VERSION 5.7 ;
  NOWIREEXTENSIONATPIN ON ;
  DIVIDERCHAR "/" ;
  BUSBITCHARS "[]" ;
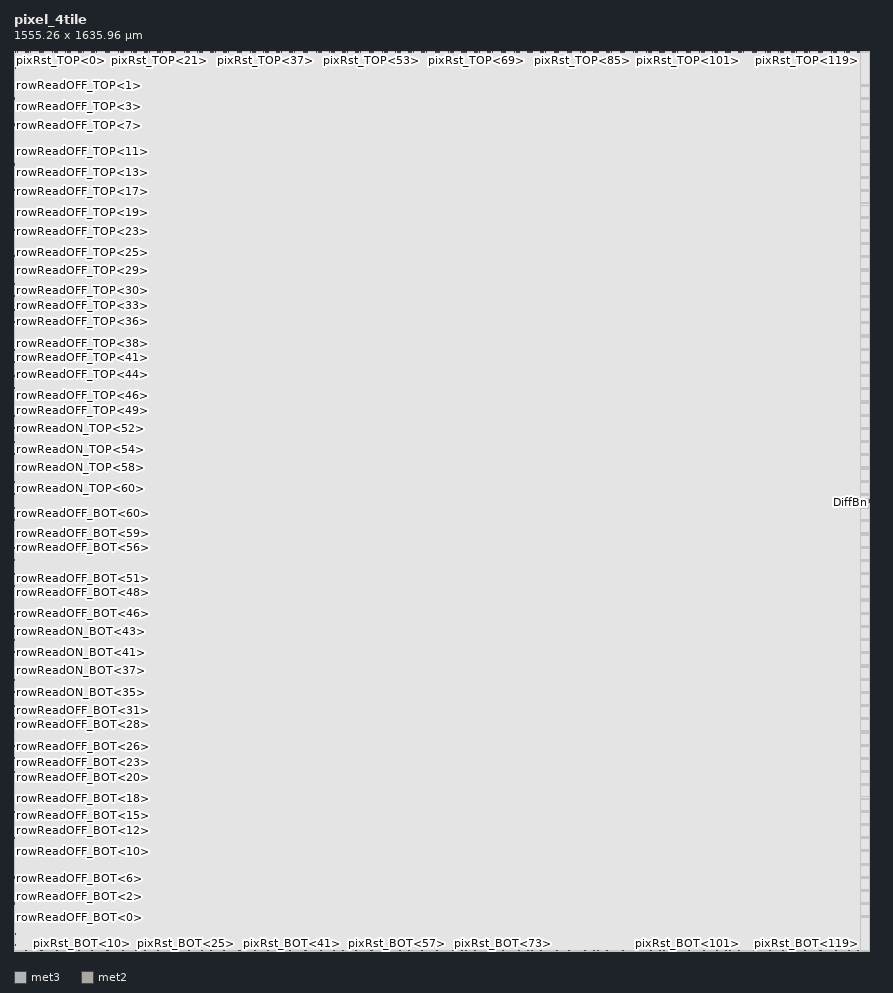
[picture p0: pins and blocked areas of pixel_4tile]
MACRO pixel_4tile
  CLASS BLOCK ;
  FOREIGN pixel_4tile ;
  ORIGIN -278.615 708.105 ;
  SIZE 1555.255 BY 1635.965 ;
  PIN OnBn
    ANTENNAGATEAREA 36864.000000 ;
    PORT
      LAYER met3 ;
        RECT 1832.880 113.885 1833.380 114.885 ;
    END
  END OnBn
  PIN PrBp
    ANTENNAGATEAREA 1228.799927 ;
    PORT
      LAYER met3 ;
        RECT 1832.880 110.885 1833.380 111.885 ;
    END
  END PrBp
  PIN RefrBp
    ANTENNAGATEAREA 10321.919922 ;
    PORT
      LAYER met3 ;
        RECT 1832.880 112.385 1833.380 113.385 ;
    END
  END RefrBp
  PIN OffBn
    ANTENNAGATEAREA 36864.000000 ;
    PORT
      LAYER met3 ;
        RECT 1832.880 107.885 1833.380 108.885 ;
    END
  END OffBn
  PIN PrSFBp
    ANTENNAGATEAREA 10321.919922 ;
    PORT
      LAYER met3 ;
        RECT 1832.880 109.385 1833.380 110.385 ;
    END
  END PrSFBp
  PIN DiffBn
    ANTENNAGATEAREA 36576.000000 ;
    PORT
      LAYER met3 ;
        RECT 1832.880 106.385 1833.380 107.385 ;
    END
  END DiffBn
  PIN VTHRESH
    ANTENNAGATEAREA 38.399998 ;
    PORT
      LAYER met3 ;
        RECT 1832.880 104.885 1833.380 105.885 ;
    END
  END VTHRESH
  PIN voutn_BOT<0>
    ANTENNADIFFAREA 0.870000 ;
    PORT
      LAYER met3 ;
        RECT 284.095 -707.875 284.865 -707.575 ;
    END
  END voutn_BOT<0>
  PIN voutn_BOT<1>
    ANTENNADIFFAREA 0.870000 ;
    PORT
      LAYER met3 ;
        RECT 300.215 -707.875 300.985 -707.575 ;
    END
  END voutn_BOT<1>
  PIN voutn_BOT<2>
    ANTENNADIFFAREA 0.870000 ;
    PORT
      LAYER met3 ;
        RECT 308.095 -707.875 308.865 -707.575 ;
    END
  END voutn_BOT<2>
  PIN voutn_BOT<3>
    ANTENNADIFFAREA 0.870000 ;
    PORT
      LAYER met3 ;
        RECT 324.215 -707.875 324.985 -707.575 ;
    END
  END voutn_BOT<3>
  PIN voutn_BOT<4>
    ANTENNADIFFAREA 0.870000 ;
    PORT
      LAYER met3 ;
        RECT 332.095 -707.875 332.865 -707.575 ;
    END
  END voutn_BOT<4>
  PIN voutn_BOT<5>
    ANTENNADIFFAREA 0.870000 ;
    PORT
      LAYER met3 ;
        RECT 348.215 -707.875 348.985 -707.575 ;
    END
  END voutn_BOT<5>
  PIN voutn_BOT<6>
    ANTENNADIFFAREA 0.870000 ;
    PORT
      LAYER met3 ;
        RECT 356.095 -707.875 356.865 -707.575 ;
    END
  END voutn_BOT<6>
  PIN voutn_BOT<7>
    ANTENNADIFFAREA 0.870000 ;
    PORT
      LAYER met3 ;
        RECT 372.215 -707.875 372.985 -707.575 ;
    END
  END voutn_BOT<7>
  PIN voutn_BOT<8>
    ANTENNADIFFAREA 0.870000 ;
    PORT
      LAYER met3 ;
        RECT 380.095 -707.875 380.865 -707.575 ;
    END
  END voutn_BOT<8>
  PIN voutn_BOT<9>
    ANTENNADIFFAREA 0.870000 ;
    PORT
      LAYER met3 ;
        RECT 396.215 -707.875 396.985 -707.575 ;
    END
  END voutn_BOT<9>
  PIN voutn_BOT<10>
    ANTENNADIFFAREA 0.870000 ;
    PORT
      LAYER met3 ;
        RECT 404.095 -707.875 404.865 -707.575 ;
    END
  END voutn_BOT<10>
  PIN voutn_BOT<11>
    ANTENNADIFFAREA 0.870000 ;
    PORT
      LAYER met3 ;
        RECT 420.215 -707.875 420.985 -707.575 ;
    END
  END voutn_BOT<11>
  PIN voutn_BOT<12>
    ANTENNADIFFAREA 0.870000 ;
    PORT
      LAYER met3 ;
        RECT 428.095 -707.875 428.865 -707.575 ;
    END
  END voutn_BOT<12>
  PIN voutn_BOT<13>
    ANTENNADIFFAREA 0.870000 ;
    PORT
      LAYER met3 ;
        RECT 444.215 -707.875 444.985 -707.575 ;
    END
  END voutn_BOT<13>
  PIN voutn_BOT<14>
    ANTENNADIFFAREA 0.870000 ;
    PORT
      LAYER met3 ;
        RECT 452.095 -707.875 452.865 -707.575 ;
    END
  END voutn_BOT<14>
  PIN voutn_BOT<15>
    ANTENNADIFFAREA 0.870000 ;
    PORT
      LAYER met3 ;
        RECT 468.215 -707.875 468.985 -707.575 ;
    END
  END voutn_BOT<15>
  PIN voutn_BOT<16>
    ANTENNADIFFAREA 0.870000 ;
    PORT
      LAYER met3 ;
        RECT 476.095 -707.875 476.865 -707.575 ;
    END
  END voutn_BOT<16>
  PIN voutn_BOT<17>
    ANTENNADIFFAREA 0.870000 ;
    PORT
      LAYER met3 ;
        RECT 492.215 -707.875 492.985 -707.575 ;
    END
  END voutn_BOT<17>
  PIN voutn_BOT<18>
    ANTENNADIFFAREA 0.870000 ;
    PORT
      LAYER met3 ;
        RECT 500.095 -707.875 500.865 -707.575 ;
    END
  END voutn_BOT<18>
  PIN voutn_BOT<19>
    ANTENNADIFFAREA 0.870000 ;
    PORT
      LAYER met3 ;
        RECT 516.215 -707.875 516.985 -707.575 ;
    END
  END voutn_BOT<19>
  PIN voutn_BOT<20>
    ANTENNADIFFAREA 0.870000 ;
    PORT
      LAYER met3 ;
        RECT 524.095 -707.875 524.865 -707.575 ;
    END
  END voutn_BOT<20>
  PIN voutn_BOT<21>
    ANTENNADIFFAREA 0.870000 ;
    PORT
      LAYER met3 ;
        RECT 540.215 -707.875 540.985 -707.575 ;
    END
  END voutn_BOT<21>
  PIN voutn_BOT<22>
    ANTENNADIFFAREA 0.870000 ;
    PORT
      LAYER met3 ;
        RECT 548.095 -707.875 548.865 -707.575 ;
    END
  END voutn_BOT<22>
  PIN voutn_BOT<23>
    ANTENNADIFFAREA 0.870000 ;
    PORT
      LAYER met3 ;
        RECT 564.215 -707.875 564.985 -707.575 ;
    END
  END voutn_BOT<23>
  PIN voutn_BOT<24>
    ANTENNADIFFAREA 0.870000 ;
    PORT
      LAYER met3 ;
        RECT 572.095 -707.875 572.865 -707.575 ;
    END
  END voutn_BOT<24>
  PIN voutn_BOT<25>
    ANTENNADIFFAREA 0.870000 ;
    PORT
      LAYER met3 ;
        RECT 588.215 -707.875 588.985 -707.575 ;
    END
  END voutn_BOT<25>
  PIN voutn_BOT<26>
    ANTENNADIFFAREA 0.870000 ;
    PORT
      LAYER met3 ;
        RECT 596.095 -707.875 596.865 -707.575 ;
    END
  END voutn_BOT<26>
  PIN voutn_BOT<27>
    ANTENNADIFFAREA 0.870000 ;
    PORT
      LAYER met3 ;
        RECT 612.215 -707.875 612.985 -707.575 ;
    END
  END voutn_BOT<27>
  PIN voutn_BOT<28>
    ANTENNADIFFAREA 0.870000 ;
    PORT
      LAYER met3 ;
        RECT 620.095 -707.875 620.865 -707.575 ;
    END
  END voutn_BOT<28>
  PIN voutn_BOT<29>
    ANTENNADIFFAREA 0.870000 ;
    PORT
      LAYER met3 ;
        RECT 636.215 -707.875 636.985 -707.575 ;
    END
  END voutn_BOT<29>
  PIN voutn_BOT<30>
    ANTENNADIFFAREA 0.870000 ;
    PORT
      LAYER met3 ;
        RECT 644.095 -707.875 644.865 -707.575 ;
    END
  END voutn_BOT<30>
  PIN voutn_BOT<31>
    ANTENNADIFFAREA 0.870000 ;
    PORT
      LAYER met3 ;
        RECT 660.215 -707.875 660.985 -707.575 ;
    END
  END voutn_BOT<31>
  PIN voutn_BOT<32>
    ANTENNADIFFAREA 0.870000 ;
    PORT
      LAYER met3 ;
        RECT 668.095 -707.875 668.865 -707.575 ;
    END
  END voutn_BOT<32>
  PIN voutn_BOT<33>
    ANTENNADIFFAREA 0.870000 ;
    PORT
      LAYER met3 ;
        RECT 684.215 -707.875 684.985 -707.575 ;
    END
  END voutn_BOT<33>
  PIN voutn_BOT<34>
    ANTENNADIFFAREA 0.870000 ;
    PORT
      LAYER met3 ;
        RECT 692.095 -707.875 692.865 -707.575 ;
    END
  END voutn_BOT<34>
  PIN voutn_BOT<35>
    ANTENNADIFFAREA 0.870000 ;
    PORT
      LAYER met3 ;
        RECT 708.215 -707.875 708.985 -707.575 ;
    END
  END voutn_BOT<35>
  PIN voutn_BOT<36>
    ANTENNADIFFAREA 0.870000 ;
    PORT
      LAYER met3 ;
        RECT 716.095 -707.875 716.865 -707.575 ;
    END
  END voutn_BOT<36>
  PIN voutn_BOT<37>
    ANTENNADIFFAREA 0.870000 ;
    PORT
      LAYER met3 ;
        RECT 732.215 -707.875 732.985 -707.575 ;
    END
  END voutn_BOT<37>
  PIN voutn_BOT<38>
    ANTENNADIFFAREA 0.870000 ;
    PORT
      LAYER met3 ;
        RECT 740.095 -707.875 740.865 -707.575 ;
    END
  END voutn_BOT<38>
  PIN voutn_BOT<39>
    ANTENNADIFFAREA 0.870000 ;
    PORT
      LAYER met3 ;
        RECT 756.215 -707.875 756.985 -707.575 ;
    END
  END voutn_BOT<39>
  PIN voutn_BOT<40>
    ANTENNADIFFAREA 0.870000 ;
    PORT
      LAYER met3 ;
        RECT 764.095 -707.875 764.865 -707.575 ;
    END
  END voutn_BOT<40>
  PIN voutn_BOT<41>
    ANTENNADIFFAREA 0.870000 ;
    PORT
      LAYER met3 ;
        RECT 780.215 -707.875 780.985 -707.575 ;
    END
  END voutn_BOT<41>
  PIN voutn_BOT<42>
    ANTENNADIFFAREA 0.870000 ;
    PORT
      LAYER met3 ;
        RECT 788.095 -707.875 788.865 -707.575 ;
    END
  END voutn_BOT<42>
  PIN voutn_BOT<43>
    ANTENNADIFFAREA 0.870000 ;
    PORT
      LAYER met3 ;
        RECT 804.215 -707.875 804.985 -707.575 ;
    END
  END voutn_BOT<43>
  PIN voutn_BOT<44>
    ANTENNADIFFAREA 0.870000 ;
    PORT
      LAYER met3 ;
        RECT 812.095 -707.875 812.865 -707.575 ;
    END
  END voutn_BOT<44>
  PIN voutn_BOT<45>
    ANTENNADIFFAREA 0.870000 ;
    PORT
      LAYER met3 ;
        RECT 828.215 -707.875 828.985 -707.575 ;
    END
  END voutn_BOT<45>
  PIN voutn_BOT<46>
    ANTENNADIFFAREA 0.870000 ;
    PORT
      LAYER met3 ;
        RECT 836.095 -707.875 836.865 -707.575 ;
    END
  END voutn_BOT<46>
  PIN voutn_BOT<47>
    ANTENNADIFFAREA 0.870000 ;
    PORT
      LAYER met3 ;
        RECT 852.215 -707.875 852.985 -707.575 ;
    END
  END voutn_BOT<47>
  PIN voutn_BOT<48>
    ANTENNADIFFAREA 0.870000 ;
    PORT
      LAYER met3 ;
        RECT 860.095 -707.875 860.865 -707.575 ;
    END
  END voutn_BOT<48>
  PIN voutn_BOT<49>
    ANTENNADIFFAREA 0.870000 ;
    PORT
      LAYER met3 ;
        RECT 876.215 -707.875 876.985 -707.575 ;
    END
  END voutn_BOT<49>
  PIN voutn_BOT<50>
    ANTENNADIFFAREA 0.870000 ;
    PORT
      LAYER met3 ;
        RECT 884.095 -707.875 884.865 -707.575 ;
    END
  END voutn_BOT<50>
  PIN voutn_BOT<51>
    ANTENNADIFFAREA 0.870000 ;
    PORT
      LAYER met3 ;
        RECT 900.215 -707.875 900.985 -707.575 ;
    END
  END voutn_BOT<51>
  PIN voutn_BOT<52>
    ANTENNADIFFAREA 0.870000 ;
    PORT
      LAYER met3 ;
        RECT 908.095 -707.875 908.865 -707.575 ;
    END
  END voutn_BOT<52>
  PIN voutn_BOT<53>
    ANTENNADIFFAREA 0.870000 ;
    PORT
      LAYER met3 ;
        RECT 924.215 -707.875 924.985 -707.575 ;
    END
  END voutn_BOT<53>
  PIN voutn_BOT<54>
    ANTENNADIFFAREA 0.870000 ;
    PORT
      LAYER met3 ;
        RECT 932.095 -707.875 932.865 -707.575 ;
    END
  END voutn_BOT<54>
  PIN voutn_BOT<55>
    ANTENNADIFFAREA 0.870000 ;
    PORT
      LAYER met3 ;
        RECT 948.215 -707.875 948.985 -707.575 ;
    END
  END voutn_BOT<55>
  PIN voutn_BOT<56>
    ANTENNADIFFAREA 0.870000 ;
    PORT
      LAYER met3 ;
        RECT 956.095 -707.875 956.865 -707.575 ;
    END
  END voutn_BOT<56>
  PIN voutn_BOT<57>
    ANTENNADIFFAREA 0.870000 ;
    PORT
      LAYER met3 ;
        RECT 972.215 -707.875 972.985 -707.575 ;
    END
  END voutn_BOT<57>
  PIN voutn_BOT<58>
    ANTENNADIFFAREA 0.870000 ;
    PORT
      LAYER met3 ;
        RECT 980.095 -707.875 980.865 -707.575 ;
    END
  END voutn_BOT<58>
  PIN voutn_BOT<59>
    ANTENNADIFFAREA 0.870000 ;
    PORT
      LAYER met3 ;
        RECT 996.215 -707.875 996.985 -707.575 ;
    END
  END voutn_BOT<59>
  PIN voutn_BOT<60>
    ANTENNADIFFAREA 0.870000 ;
    PORT
      LAYER met3 ;
        RECT 1004.095 -707.875 1004.865 -707.575 ;
    END
  END voutn_BOT<60>
  PIN voutn_BOT<61>
    ANTENNADIFFAREA 0.870000 ;
    PORT
      LAYER met3 ;
        RECT 1020.215 -707.875 1020.985 -707.575 ;
    END
  END voutn_BOT<61>
  PIN voutn_BOT<62>
    ANTENNADIFFAREA 0.870000 ;
    PORT
      LAYER met3 ;
        RECT 1028.095 -707.875 1028.865 -707.575 ;
    END
  END voutn_BOT<62>
  PIN voutn_BOT<63>
    ANTENNADIFFAREA 0.870000 ;
    PORT
      LAYER met3 ;
        RECT 1044.215 -707.875 1044.985 -707.575 ;
    END
  END voutn_BOT<63>
  PIN voutn_BOT<64>
    ANTENNADIFFAREA 0.870000 ;
    PORT
      LAYER met3 ;
        RECT 1052.095 -707.875 1052.865 -707.575 ;
    END
  END voutn_BOT<64>
  PIN voutn_BOT<65>
    ANTENNADIFFAREA 0.870000 ;
    PORT
      LAYER met3 ;
        RECT 1068.215 -707.875 1068.985 -707.575 ;
    END
  END voutn_BOT<65>
  PIN voutn_BOT<66>
    ANTENNADIFFAREA 0.870000 ;
    PORT
      LAYER met3 ;
        RECT 1076.095 -707.875 1076.865 -707.575 ;
    END
  END voutn_BOT<66>
  PIN voutn_BOT<67>
    ANTENNADIFFAREA 0.870000 ;
    PORT
      LAYER met3 ;
        RECT 1092.215 -707.875 1092.985 -707.575 ;
    END
  END voutn_BOT<67>
  PIN voutn_BOT<68>
    ANTENNADIFFAREA 0.870000 ;
    PORT
      LAYER met3 ;
        RECT 1100.095 -707.875 1100.865 -707.575 ;
    END
  END voutn_BOT<68>
  PIN voutn_BOT<69>
    ANTENNADIFFAREA 0.870000 ;
    PORT
      LAYER met3 ;
        RECT 1116.215 -707.875 1116.985 -707.575 ;
    END
  END voutn_BOT<69>
  PIN voutn_BOT<70>
    ANTENNADIFFAREA 0.870000 ;
    PORT
      LAYER met3 ;
        RECT 1124.095 -707.875 1124.865 -707.575 ;
    END
  END voutn_BOT<70>
  PIN voutn_BOT<71>
    ANTENNADIFFAREA 0.870000 ;
    PORT
      LAYER met3 ;
        RECT 1140.215 -707.875 1140.985 -707.575 ;
    END
  END voutn_BOT<71>
  PIN voutn_BOT<72>
    ANTENNADIFFAREA 0.870000 ;
    PORT
      LAYER met3 ;
        RECT 1148.095 -707.875 1148.865 -707.575 ;
    END
  END voutn_BOT<72>
  PIN voutn_BOT<73>
    ANTENNADIFFAREA 0.870000 ;
    PORT
      LAYER met3 ;
        RECT 1164.215 -707.875 1164.985 -707.575 ;
    END
  END voutn_BOT<73>
  PIN voutn_BOT<74>
    ANTENNADIFFAREA 0.870000 ;
    PORT
      LAYER met3 ;
        RECT 1172.095 -707.875 1172.865 -707.575 ;
    END
  END voutn_BOT<74>
  PIN voutn_BOT<75>
    ANTENNADIFFAREA 0.870000 ;
    PORT
      LAYER met3 ;
        RECT 1188.215 -707.875 1188.985 -707.575 ;
    END
  END voutn_BOT<75>
  PIN voutn_BOT<76>
    ANTENNADIFFAREA 0.870000 ;
    PORT
      LAYER met3 ;
        RECT 1196.095 -707.875 1196.865 -707.575 ;
    END
  END voutn_BOT<76>
  PIN voutn_BOT<77>
    ANTENNADIFFAREA 0.870000 ;
    PORT
      LAYER met3 ;
        RECT 1212.215 -707.875 1212.985 -707.575 ;
    END
  END voutn_BOT<77>
  PIN voutn_BOT<78>
    ANTENNADIFFAREA 0.870000 ;
    PORT
      LAYER met3 ;
        RECT 1220.095 -707.875 1220.865 -707.575 ;
    END
  END voutn_BOT<78>
  PIN voutn_BOT<79>
    ANTENNADIFFAREA 0.870000 ;
    PORT
      LAYER met3 ;
        RECT 1236.215 -707.875 1236.985 -707.575 ;
    END
  END voutn_BOT<79>
  PIN voutn_BOT<80>
    ANTENNADIFFAREA 0.870000 ;
    PORT
      LAYER met3 ;
        RECT 1244.095 -707.875 1244.865 -707.575 ;
    END
  END voutn_BOT<80>
  PIN voutn_BOT<81>
    ANTENNADIFFAREA 0.870000 ;
    PORT
      LAYER met3 ;
        RECT 1260.215 -707.875 1260.985 -707.575 ;
    END
  END voutn_BOT<81>
  PIN voutn_BOT<82>
    ANTENNADIFFAREA 0.870000 ;
    PORT
      LAYER met3 ;
        RECT 1268.095 -707.875 1268.865 -707.575 ;
    END
  END voutn_BOT<82>
  PIN voutn_BOT<83>
    ANTENNADIFFAREA 0.870000 ;
    PORT
      LAYER met3 ;
        RECT 1284.215 -707.875 1284.985 -707.575 ;
    END
  END voutn_BOT<83>
  PIN voutn_BOT<84>
    ANTENNADIFFAREA 0.870000 ;
    PORT
      LAYER met3 ;
        RECT 1292.095 -707.875 1292.865 -707.575 ;
    END
  END voutn_BOT<84>
  PIN voutn_BOT<85>
    ANTENNADIFFAREA 0.870000 ;
    PORT
      LAYER met3 ;
        RECT 1308.215 -707.875 1308.985 -707.575 ;
    END
  END voutn_BOT<85>
  PIN voutn_BOT<86>
    ANTENNADIFFAREA 0.870000 ;
    PORT
      LAYER met3 ;
        RECT 1316.095 -707.875 1316.865 -707.575 ;
    END
  END voutn_BOT<86>
  PIN voutn_BOT<87>
    ANTENNADIFFAREA 0.870000 ;
    PORT
      LAYER met3 ;
        RECT 1332.215 -707.875 1332.985 -707.575 ;
    END
  END voutn_BOT<87>
  PIN voutn_BOT<88>
    ANTENNADIFFAREA 0.870000 ;
    PORT
      LAYER met3 ;
        RECT 1340.095 -707.875 1340.865 -707.575 ;
    END
  END voutn_BOT<88>
  PIN voutn_BOT<89>
    ANTENNADIFFAREA 0.870000 ;
    PORT
      LAYER met3 ;
        RECT 1356.215 -707.875 1356.985 -707.575 ;
    END
  END voutn_BOT<89>
  PIN voutn_BOT<90>
    ANTENNADIFFAREA 0.870000 ;
    PORT
      LAYER met3 ;
        RECT 1364.095 -707.875 1364.865 -707.575 ;
    END
  END voutn_BOT<90>
  PIN voutn_BOT<91>
    ANTENNADIFFAREA 0.870000 ;
    PORT
      LAYER met3 ;
        RECT 1380.215 -707.875 1380.985 -707.575 ;
    END
  END voutn_BOT<91>
  PIN voutn_BOT<92>
    ANTENNADIFFAREA 0.870000 ;
    PORT
      LAYER met3 ;
        RECT 1388.095 -707.875 1388.865 -707.575 ;
    END
  END voutn_BOT<92>
  PIN voutn_BOT<93>
    ANTENNADIFFAREA 0.870000 ;
    PORT
      LAYER met3 ;
        RECT 1404.215 -707.875 1404.985 -707.575 ;
    END
  END voutn_BOT<93>
  PIN voutn_BOT<94>
    ANTENNADIFFAREA 0.870000 ;
    PORT
      LAYER met3 ;
        RECT 1412.095 -707.875 1412.865 -707.575 ;
    END
  END voutn_BOT<94>
  PIN voutn_BOT<95>
    ANTENNADIFFAREA 0.870000 ;
    PORT
      LAYER met3 ;
        RECT 1428.215 -707.875 1428.985 -707.575 ;
    END
  END voutn_BOT<95>
  PIN voutn_BOT<96>
    ANTENNADIFFAREA 0.870000 ;
    PORT
      LAYER met3 ;
        RECT 1436.095 -707.875 1436.865 -707.575 ;
    END
  END voutn_BOT<96>
  PIN voutn_BOT<97>
    ANTENNADIFFAREA 0.870000 ;
    PORT
      LAYER met3 ;
        RECT 1452.215 -707.875 1452.985 -707.575 ;
    END
  END voutn_BOT<97>
  PIN voutn_BOT<98>
    ANTENNADIFFAREA 0.870000 ;
    PORT
      LAYER met3 ;
        RECT 1460.095 -707.875 1460.865 -707.575 ;
    END
  END voutn_BOT<98>
  PIN voutn_BOT<99>
    ANTENNADIFFAREA 0.870000 ;
    PORT
      LAYER met3 ;
        RECT 1476.215 -707.875 1476.985 -707.575 ;
    END
  END voutn_BOT<99>
  PIN voutn_BOT<100>
    ANTENNADIFFAREA 0.870000 ;
    PORT
      LAYER met3 ;
        RECT 1484.095 -707.875 1484.865 -707.575 ;
    END
  END voutn_BOT<100>
  PIN voutn_BOT<101>
    ANTENNADIFFAREA 0.870000 ;
    PORT
      LAYER met3 ;
        RECT 1500.215 -707.875 1500.985 -707.575 ;
    END
  END voutn_BOT<101>
  PIN voutn_BOT<102>
    ANTENNADIFFAREA 0.870000 ;
    PORT
      LAYER met3 ;
        RECT 1508.095 -707.875 1508.865 -707.575 ;
    END
  END voutn_BOT<102>
  PIN voutn_BOT<103>
    ANTENNADIFFAREA 0.870000 ;
    PORT
      LAYER met3 ;
        RECT 1524.215 -707.875 1524.985 -707.575 ;
    END
  END voutn_BOT<103>
  PIN voutn_BOT<104>
    ANTENNADIFFAREA 0.870000 ;
    PORT
      LAYER met3 ;
        RECT 1532.095 -707.875 1532.865 -707.575 ;
    END
  END voutn_BOT<104>
  PIN voutn_BOT<105>
    ANTENNADIFFAREA 0.870000 ;
    PORT
      LAYER met3 ;
        RECT 1548.215 -707.875 1548.985 -707.575 ;
    END
  END voutn_BOT<105>
  PIN voutn_BOT<106>
    ANTENNADIFFAREA 0.870000 ;
    PORT
      LAYER met3 ;
        RECT 1556.095 -707.875 1556.865 -707.575 ;
    END
  END voutn_BOT<106>
  PIN voutn_BOT<107>
    ANTENNADIFFAREA 0.870000 ;
    PORT
      LAYER met3 ;
        RECT 1572.215 -707.875 1572.985 -707.575 ;
    END
  END voutn_BOT<107>
  PIN voutn_BOT<108>
    ANTENNADIFFAREA 0.870000 ;
    PORT
      LAYER met3 ;
        RECT 1580.095 -707.875 1580.865 -707.575 ;
    END
  END voutn_BOT<108>
  PIN voutn_BOT<109>
    ANTENNADIFFAREA 0.870000 ;
    PORT
      LAYER met3 ;
        RECT 1596.215 -707.875 1596.985 -707.575 ;
    END
  END voutn_BOT<109>
  PIN voutn_BOT<110>
    ANTENNADIFFAREA 0.870000 ;
    PORT
      LAYER met3 ;
        RECT 1604.095 -707.875 1604.865 -707.575 ;
    END
  END voutn_BOT<110>
  PIN voutn_BOT<111>
    ANTENNADIFFAREA 0.870000 ;
    PORT
      LAYER met3 ;
        RECT 1620.215 -707.875 1620.985 -707.575 ;
    END
  END voutn_BOT<111>
  PIN voutn_BOT<112>
    ANTENNADIFFAREA 0.870000 ;
    PORT
      LAYER met3 ;
        RECT 1628.095 -707.875 1628.865 -707.575 ;
    END
  END voutn_BOT<112>
  PIN voutn_BOT<113>
    ANTENNADIFFAREA 0.870000 ;
    PORT
      LAYER met3 ;
        RECT 1644.215 -707.875 1644.985 -707.575 ;
    END
  END voutn_BOT<113>
  PIN voutn_BOT<114>
    ANTENNADIFFAREA 0.870000 ;
    PORT
      LAYER met3 ;
        RECT 1652.095 -707.875 1652.865 -707.575 ;
    END
  END voutn_BOT<114>
  PIN voutn_BOT<115>
    ANTENNADIFFAREA 0.870000 ;
    PORT
      LAYER met3 ;
        RECT 1668.215 -707.875 1668.985 -707.575 ;
    END
  END voutn_BOT<115>
  PIN voutn_BOT<116>
    ANTENNADIFFAREA 0.870000 ;
    PORT
      LAYER met3 ;
        RECT 1676.095 -707.875 1676.865 -707.575 ;
    END
  END voutn_BOT<116>
  PIN voutn_BOT<117>
    ANTENNADIFFAREA 0.870000 ;
    PORT
      LAYER met3 ;
        RECT 1692.215 -707.875 1692.985 -707.575 ;
    END
  END voutn_BOT<117>
  PIN voutn_BOT<118>
    ANTENNADIFFAREA 0.870000 ;
    PORT
      LAYER met3 ;
        RECT 1700.095 -707.875 1700.865 -707.575 ;
    END
  END voutn_BOT<118>
  PIN voutn_BOT<119>
    ANTENNADIFFAREA 0.870000 ;
    PORT
      LAYER met3 ;
        RECT 1716.215 -707.875 1716.985 -707.575 ;
    END
  END voutn_BOT<119>
  PIN voutn_BOT<120>
    ANTENNADIFFAREA 0.870000 ;
    PORT
      LAYER met3 ;
        RECT 1724.095 -707.875 1724.865 -707.575 ;
    END
  END voutn_BOT<120>
  PIN voutn_BOT<121>
    ANTENNADIFFAREA 0.870000 ;
    PORT
      LAYER met3 ;
        RECT 1740.215 -707.875 1740.985 -707.575 ;
    END
  END voutn_BOT<121>
  PIN voutn_BOT<122>
    ANTENNADIFFAREA 0.870000 ;
    PORT
      LAYER met3 ;
        RECT 1748.095 -707.875 1748.865 -707.575 ;
    END
  END voutn_BOT<122>
  PIN voutn_BOT<123>
    ANTENNADIFFAREA 0.870000 ;
    PORT
      LAYER met3 ;
        RECT 1764.215 -707.875 1764.985 -707.575 ;
    END
  END voutn_BOT<123>
  PIN voutn_BOT<124>
    ANTENNADIFFAREA 0.870000 ;
    PORT
      LAYER met3 ;
        RECT 1772.095 -707.875 1772.865 -707.575 ;
    END
  END voutn_BOT<124>
  PIN voutn_BOT<125>
    ANTENNADIFFAREA 0.870000 ;
    PORT
      LAYER met3 ;
        RECT 1788.215 -707.875 1788.985 -707.575 ;
    END
  END voutn_BOT<125>
  PIN voutn_BOT<126>
    ANTENNADIFFAREA 0.870000 ;
    PORT
      LAYER met3 ;
        RECT 1796.095 -707.875 1796.865 -707.575 ;
    END
  END voutn_BOT<126>
  PIN voutn_BOT<127>
    ANTENNADIFFAREA 0.870000 ;
    PORT
      LAYER met3 ;
        RECT 1812.215 -707.875 1812.985 -707.575 ;
    END
  END voutn_BOT<127>
  PIN pixRst_BOT<0>
    ANTENNAGATEAREA 4.032000 ;
    PORT
      LAYER met3 ;
        RECT 281.350 -707.840 281.650 -707.540 ;
    END
  END pixRst_BOT<0>
  PIN pixRst_BOT<1>
    ANTENNAGATEAREA 4.032000 ;
    PORT
      LAYER met3 ;
        RECT 303.445 -707.755 303.745 -707.455 ;
    END
  END pixRst_BOT<1>
  PIN pixRst_BOT<2>
    ANTENNAGATEAREA 4.032000 ;
    PORT
      LAYER met3 ;
        RECT 305.350 -707.755 305.650 -707.455 ;
    END
  END pixRst_BOT<2>
  PIN pixRst_BOT<3>
    ANTENNAGATEAREA 4.032000 ;
    PORT
      LAYER met3 ;
        RECT 327.445 -707.755 327.745 -707.455 ;
    END
  END pixRst_BOT<3>
  PIN pixRst_BOT<4>
    ANTENNAGATEAREA 4.032000 ;
    PORT
      LAYER met3 ;
        RECT 329.350 -707.755 329.650 -707.455 ;
    END
  END pixRst_BOT<4>
  PIN pixRst_BOT<5>
    ANTENNAGATEAREA 4.032000 ;
    PORT
      LAYER met3 ;
        RECT 351.445 -707.755 351.745 -707.455 ;
    END
  END pixRst_BOT<5>
  PIN pixRst_BOT<6>
    ANTENNAGATEAREA 4.032000 ;
    PORT
      LAYER met3 ;
        RECT 353.350 -707.755 353.650 -707.455 ;
    END
  END pixRst_BOT<6>
  PIN pixRst_BOT<7>
    ANTENNAGATEAREA 4.032000 ;
    PORT
      LAYER met3 ;
        RECT 375.445 -707.755 375.745 -707.455 ;
    END
  END pixRst_BOT<7>
  PIN pixRst_BOT<8>
    ANTENNAGATEAREA 4.032000 ;
    PORT
      LAYER met3 ;
        RECT 377.350 -707.755 377.650 -707.455 ;
    END
  END pixRst_BOT<8>
  PIN pixRst_BOT<9>
    ANTENNAGATEAREA 4.032000 ;
    PORT
      LAYER met3 ;
        RECT 399.445 -707.755 399.745 -707.455 ;
    END
  END pixRst_BOT<9>
  PIN pixRst_BOT<10>
    ANTENNAGATEAREA 4.032000 ;
    PORT
      LAYER met3 ;
        RECT 401.350 -707.755 401.650 -707.455 ;
    END
  END pixRst_BOT<10>
  PIN pixRst_BOT<11>
    ANTENNAGATEAREA 4.032000 ;
    PORT
      LAYER met3 ;
        RECT 423.445 -707.755 423.745 -707.455 ;
    END
  END pixRst_BOT<11>
  PIN pixRst_BOT<12>
    ANTENNAGATEAREA 4.032000 ;
    PORT
      LAYER met3 ;
        RECT 425.350 -707.755 425.650 -707.455 ;
    END
  END pixRst_BOT<12>
  PIN pixRst_BOT<13>
    ANTENNAGATEAREA 4.032000 ;
    PORT
      LAYER met3 ;
        RECT 447.445 -707.755 447.745 -707.455 ;
    END
  END pixRst_BOT<13>
  PIN pixRst_BOT<14>
    ANTENNAGATEAREA 4.032000 ;
    PORT
      LAYER met3 ;
        RECT 449.350 -707.755 449.650 -707.455 ;
    END
  END pixRst_BOT<14>
  PIN pixRst_BOT<15>
    ANTENNAGATEAREA 4.032000 ;
    PORT
      LAYER met3 ;
        RECT 471.445 -707.755 471.745 -707.455 ;
    END
  END pixRst_BOT<15>
  PIN pixRst_BOT<16>
    ANTENNAGATEAREA 4.032000 ;
    PORT
      LAYER met3 ;
        RECT 473.350 -707.755 473.650 -707.455 ;
    END
  END pixRst_BOT<16>
  PIN pixRst_BOT<17>
    ANTENNAGATEAREA 4.032000 ;
    PORT
      LAYER met3 ;
        RECT 495.445 -707.755 495.745 -707.455 ;
    END
  END pixRst_BOT<17>
  PIN pixRst_BOT<18>
    ANTENNAGATEAREA 4.032000 ;
    PORT
      LAYER met3 ;
        RECT 497.350 -707.755 497.650 -707.455 ;
    END
  END pixRst_BOT<18>
  PIN pixRst_BOT<19>
    ANTENNAGATEAREA 4.032000 ;
    PORT
      LAYER met3 ;
        RECT 519.445 -707.755 519.745 -707.455 ;
    END
  END pixRst_BOT<19>
  PIN pixRst_BOT<20>
    ANTENNAGATEAREA 4.032000 ;
    PORT
      LAYER met3 ;
        RECT 521.350 -707.755 521.650 -707.455 ;
    END
  END pixRst_BOT<20>
  PIN pixRst_BOT<21>
    ANTENNAGATEAREA 4.032000 ;
    PORT
      LAYER met3 ;
        RECT 543.445 -707.755 543.745 -707.455 ;
    END
  END pixRst_BOT<21>
  PIN pixRst_BOT<22>
    ANTENNAGATEAREA 4.032000 ;
    PORT
      LAYER met3 ;
        RECT 545.350 -707.755 545.650 -707.455 ;
    END
  END pixRst_BOT<22>
  PIN pixRst_BOT<23>
    ANTENNAGATEAREA 4.032000 ;
    PORT
      LAYER met3 ;
        RECT 567.445 -707.755 567.745 -707.455 ;
    END
  END pixRst_BOT<23>
  PIN pixRst_BOT<24>
    ANTENNAGATEAREA 4.032000 ;
    PORT
      LAYER met3 ;
        RECT 569.350 -707.755 569.650 -707.455 ;
    END
  END pixRst_BOT<24>
  PIN pixRst_BOT<25>
    ANTENNAGATEAREA 4.032000 ;
    PORT
      LAYER met3 ;
        RECT 591.445 -707.755 591.745 -707.455 ;
    END
  END pixRst_BOT<25>
  PIN pixRst_BOT<26>
    ANTENNAGATEAREA 4.032000 ;
    PORT
      LAYER met3 ;
        RECT 593.350 -707.755 593.650 -707.455 ;
    END
  END pixRst_BOT<26>
  PIN pixRst_BOT<27>
    ANTENNAGATEAREA 4.032000 ;
    PORT
      LAYER met3 ;
        RECT 615.445 -707.755 615.745 -707.455 ;
    END
  END pixRst_BOT<27>
  PIN pixRst_BOT<28>
    ANTENNAGATEAREA 4.032000 ;
    PORT
      LAYER met3 ;
        RECT 617.350 -707.755 617.650 -707.455 ;
    END
  END pixRst_BOT<28>
  PIN pixRst_BOT<29>
    ANTENNAGATEAREA 4.032000 ;
    PORT
      LAYER met3 ;
        RECT 639.445 -707.755 639.745 -707.455 ;
    END
  END pixRst_BOT<29>
  PIN pixRst_BOT<30>
    ANTENNAGATEAREA 4.032000 ;
    PORT
      LAYER met3 ;
        RECT 641.350 -707.755 641.650 -707.455 ;
    END
  END pixRst_BOT<30>
  PIN pixRst_BOT<31>
    ANTENNAGATEAREA 4.032000 ;
    PORT
      LAYER met3 ;
        RECT 663.445 -707.755 663.745 -707.455 ;
    END
  END pixRst_BOT<31>
  PIN pixRst_BOT<32>
    ANTENNAGATEAREA 4.032000 ;
    PORT
      LAYER met3 ;
        RECT 665.350 -707.755 665.650 -707.455 ;
    END
  END pixRst_BOT<32>
  PIN pixRst_BOT<33>
    ANTENNAGATEAREA 4.032000 ;
    PORT
      LAYER met3 ;
        RECT 687.445 -707.755 687.745 -707.455 ;
    END
  END pixRst_BOT<33>
  PIN pixRst_BOT<34>
    ANTENNAGATEAREA 4.032000 ;
    PORT
      LAYER met3 ;
        RECT 689.350 -707.755 689.650 -707.455 ;
    END
  END pixRst_BOT<34>
  PIN pixRst_BOT<35>
    ANTENNAGATEAREA 4.032000 ;
    PORT
      LAYER met3 ;
        RECT 711.445 -707.755 711.745 -707.455 ;
    END
  END pixRst_BOT<35>
  PIN pixRst_BOT<36>
    ANTENNAGATEAREA 4.032000 ;
    PORT
      LAYER met3 ;
        RECT 713.350 -707.755 713.650 -707.455 ;
    END
  END pixRst_BOT<36>
  PIN pixRst_BOT<37>
    ANTENNAGATEAREA 4.032000 ;
    PORT
      LAYER met3 ;
        RECT 735.445 -707.755 735.745 -707.455 ;
    END
  END pixRst_BOT<37>
  PIN pixRst_BOT<38>
    ANTENNAGATEAREA 4.032000 ;
    PORT
      LAYER met3 ;
        RECT 737.350 -707.755 737.650 -707.455 ;
    END
  END pixRst_BOT<38>
  PIN pixRst_BOT<39>
    ANTENNAGATEAREA 4.032000 ;
    PORT
      LAYER met3 ;
        RECT 759.445 -707.755 759.745 -707.455 ;
    END
  END pixRst_BOT<39>
  PIN pixRst_BOT<40>
    ANTENNAGATEAREA 4.032000 ;
    PORT
      LAYER met3 ;
        RECT 761.350 -707.755 761.650 -707.455 ;
    END
  END pixRst_BOT<40>
  PIN pixRst_BOT<41>
    ANTENNAGATEAREA 4.032000 ;
    PORT
      LAYER met3 ;
        RECT 783.445 -707.755 783.745 -707.455 ;
    END
  END pixRst_BOT<41>
  PIN pixRst_BOT<42>
    ANTENNAGATEAREA 4.032000 ;
    PORT
      LAYER met3 ;
        RECT 785.350 -707.755 785.650 -707.455 ;
    END
  END pixRst_BOT<42>
  PIN pixRst_BOT<43>
    ANTENNAGATEAREA 4.032000 ;
    PORT
      LAYER met3 ;
        RECT 807.445 -707.755 807.745 -707.455 ;
    END
  END pixRst_BOT<43>
  PIN pixRst_BOT<44>
    ANTENNAGATEAREA 4.032000 ;
    PORT
      LAYER met3 ;
        RECT 809.350 -707.755 809.650 -707.455 ;
    END
  END pixRst_BOT<44>
  PIN pixRst_BOT<45>
    ANTENNAGATEAREA 4.032000 ;
    PORT
      LAYER met3 ;
        RECT 831.445 -707.755 831.745 -707.455 ;
    END
  END pixRst_BOT<45>
  PIN pixRst_BOT<46>
    ANTENNAGATEAREA 4.032000 ;
    PORT
      LAYER met3 ;
        RECT 833.350 -707.755 833.650 -707.455 ;
    END
  END pixRst_BOT<46>
  PIN pixRst_BOT<47>
    ANTENNAGATEAREA 4.032000 ;
    PORT
      LAYER met3 ;
        RECT 855.445 -707.755 855.745 -707.455 ;
    END
  END pixRst_BOT<47>
  PIN pixRst_BOT<48>
    ANTENNAGATEAREA 4.032000 ;
    PORT
      LAYER met3 ;
        RECT 857.350 -707.755 857.650 -707.455 ;
    END
  END pixRst_BOT<48>
  PIN pixRst_BOT<49>
    ANTENNAGATEAREA 4.032000 ;
    PORT
      LAYER met3 ;
        RECT 879.445 -707.755 879.745 -707.455 ;
    END
  END pixRst_BOT<49>
  PIN pixRst_BOT<50>
    ANTENNAGATEAREA 4.032000 ;
    PORT
      LAYER met3 ;
        RECT 881.350 -707.755 881.650 -707.455 ;
    END
  END pixRst_BOT<50>
  PIN pixRst_BOT<51>
    ANTENNAGATEAREA 4.032000 ;
    PORT
      LAYER met3 ;
        RECT 903.445 -707.755 903.745 -707.455 ;
    END
  END pixRst_BOT<51>
  PIN pixRst_BOT<52>
    ANTENNAGATEAREA 4.032000 ;
    PORT
      LAYER met3 ;
        RECT 905.350 -707.755 905.650 -707.455 ;
    END
  END pixRst_BOT<52>
  PIN pixRst_BOT<53>
    ANTENNAGATEAREA 4.032000 ;
    PORT
      LAYER met3 ;
        RECT 927.445 -707.755 927.745 -707.455 ;
    END
  END pixRst_BOT<53>
  PIN pixRst_BOT<54>
    ANTENNAGATEAREA 4.032000 ;
    PORT
      LAYER met3 ;
        RECT 929.350 -707.755 929.650 -707.455 ;
    END
  END pixRst_BOT<54>
  PIN pixRst_BOT<55>
    ANTENNAGATEAREA 4.032000 ;
    PORT
      LAYER met3 ;
        RECT 951.445 -707.755 951.745 -707.455 ;
    END
  END pixRst_BOT<55>
  PIN pixRst_BOT<56>
    ANTENNAGATEAREA 4.032000 ;
    PORT
      LAYER met3 ;
        RECT 953.350 -707.755 953.650 -707.455 ;
    END
  END pixRst_BOT<56>
  PIN pixRst_BOT<57>
    ANTENNAGATEAREA 4.032000 ;
    PORT
      LAYER met3 ;
        RECT 975.445 -707.755 975.745 -707.455 ;
    END
  END pixRst_BOT<57>
  PIN pixRst_BOT<58>
    ANTENNAGATEAREA 4.032000 ;
    PORT
      LAYER met3 ;
        RECT 977.350 -707.755 977.650 -707.455 ;
    END
  END pixRst_BOT<58>
  PIN pixRst_BOT<59>
    ANTENNAGATEAREA 4.032000 ;
    PORT
      LAYER met3 ;
        RECT 999.445 -707.755 999.745 -707.455 ;
    END
  END pixRst_BOT<59>
  PIN pixRst_BOT<60>
    ANTENNAGATEAREA 4.032000 ;
    PORT
      LAYER met3 ;
        RECT 1001.350 -707.755 1001.650 -707.455 ;
    END
  END pixRst_BOT<60>
  PIN pixRst_BOT<61>
    ANTENNAGATEAREA 4.032000 ;
    PORT
      LAYER met3 ;
        RECT 1023.445 -707.755 1023.745 -707.455 ;
    END
  END pixRst_BOT<61>
  PIN pixRst_BOT<62>
    ANTENNAGATEAREA 4.032000 ;
    PORT
      LAYER met3 ;
        RECT 1025.350 -707.755 1025.650 -707.455 ;
    END
  END pixRst_BOT<62>
  PIN pixRst_BOT<63>
    ANTENNAGATEAREA 4.032000 ;
    PORT
      LAYER met3 ;
        RECT 1047.445 -707.755 1047.745 -707.455 ;
    END
  END pixRst_BOT<63>
  PIN pixRst_BOT<64>
    ANTENNAGATEAREA 4.032000 ;
    PORT
      LAYER met3 ;
        RECT 1049.350 -707.840 1049.650 -707.540 ;
    END
  END pixRst_BOT<64>
  PIN pixRst_BOT<65>
    ANTENNAGATEAREA 4.032000 ;
    PORT
      LAYER met3 ;
        RECT 1071.445 -707.755 1071.745 -707.455 ;
    END
  END pixRst_BOT<65>
  PIN pixRst_BOT<66>
    ANTENNAGATEAREA 4.032000 ;
    PORT
      LAYER met3 ;
        RECT 1073.350 -707.755 1073.650 -707.455 ;
    END
  END pixRst_BOT<66>
  PIN pixRst_BOT<67>
    ANTENNAGATEAREA 4.032000 ;
    PORT
      LAYER met3 ;
        RECT 1095.445 -707.755 1095.745 -707.455 ;
    END
  END pixRst_BOT<67>
  PIN pixRst_BOT<68>
    ANTENNAGATEAREA 4.032000 ;
    PORT
      LAYER met3 ;
        RECT 1097.350 -707.755 1097.650 -707.455 ;
    END
  END pixRst_BOT<68>
  PIN pixRst_BOT<69>
    ANTENNAGATEAREA 4.032000 ;
    PORT
      LAYER met3 ;
        RECT 1119.445 -707.755 1119.745 -707.455 ;
    END
  END pixRst_BOT<69>
  PIN pixRst_BOT<70>
    ANTENNAGATEAREA 4.032000 ;
    PORT
      LAYER met3 ;
        RECT 1121.350 -707.755 1121.650 -707.455 ;
    END
  END pixRst_BOT<70>
  PIN pixRst_BOT<71>
    ANTENNAGATEAREA 4.032000 ;
    PORT
      LAYER met3 ;
        RECT 1143.445 -707.755 1143.745 -707.455 ;
    END
  END pixRst_BOT<71>
  PIN pixRst_BOT<72>
    ANTENNAGATEAREA 4.032000 ;
    PORT
      LAYER met3 ;
        RECT 1145.350 -707.755 1145.650 -707.455 ;
    END
  END pixRst_BOT<72>
  PIN pixRst_BOT<73>
    ANTENNAGATEAREA 4.032000 ;
    PORT
      LAYER met3 ;
        RECT 1167.445 -707.755 1167.745 -707.455 ;
    END
  END pixRst_BOT<73>
  PIN pixRst_BOT<74>
    ANTENNAGATEAREA 4.032000 ;
    PORT
      LAYER met3 ;
        RECT 1169.350 -707.755 1169.650 -707.455 ;
    END
  END pixRst_BOT<74>
  PIN pixRst_BOT<75>
    ANTENNAGATEAREA 4.032000 ;
    PORT
      LAYER met3 ;
        RECT 1191.445 -707.755 1191.745 -707.455 ;
    END
  END pixRst_BOT<75>
  PIN pixRst_BOT<76>
    ANTENNAGATEAREA 4.032000 ;
    PORT
      LAYER met3 ;
        RECT 1193.350 -707.755 1193.650 -707.455 ;
    END
  END pixRst_BOT<76>
  PIN pixRst_BOT<77>
    ANTENNAGATEAREA 4.032000 ;
    PORT
      LAYER met3 ;
        RECT 1215.445 -707.755 1215.745 -707.455 ;
    END
  END pixRst_BOT<77>
  PIN pixRst_BOT<78>
    ANTENNAGATEAREA 4.032000 ;
    PORT
      LAYER met3 ;
        RECT 1217.350 -707.755 1217.650 -707.455 ;
    END
  END pixRst_BOT<78>
  PIN pixRst_BOT<79>
    ANTENNAGATEAREA 4.032000 ;
    PORT
      LAYER met3 ;
        RECT 1239.445 -707.755 1239.745 -707.455 ;
    END
  END pixRst_BOT<79>
  PIN pixRst_BOT<80>
    ANTENNAGATEAREA 4.032000 ;
    PORT
      LAYER met3 ;
        RECT 1241.350 -707.755 1241.650 -707.455 ;
    END
  END pixRst_BOT<80>
  PIN pixRst_BOT<81>
    ANTENNAGATEAREA 4.032000 ;
    PORT
      LAYER met3 ;
        RECT 1263.445 -707.755 1263.745 -707.455 ;
    END
  END pixRst_BOT<81>
  PIN pixRst_BOT<82>
    ANTENNAGATEAREA 4.032000 ;
    PORT
      LAYER met3 ;
        RECT 1265.350 -707.755 1265.650 -707.455 ;
    END
  END pixRst_BOT<82>
  PIN pixRst_BOT<83>
    ANTENNAGATEAREA 4.032000 ;
    PORT
      LAYER met3 ;
        RECT 1287.445 -707.755 1287.745 -707.455 ;
    END
  END pixRst_BOT<83>
  PIN pixRst_BOT<84>
    ANTENNAGATEAREA 4.032000 ;
    PORT
      LAYER met3 ;
        RECT 1289.350 -707.755 1289.650 -707.455 ;
    END
  END pixRst_BOT<84>
  PIN pixRst_BOT<85>
    ANTENNAGATEAREA 4.032000 ;
    PORT
      LAYER met3 ;
        RECT 1311.445 -707.755 1311.745 -707.455 ;
    END
  END pixRst_BOT<85>
  PIN pixRst_BOT<86>
    ANTENNAGATEAREA 4.032000 ;
    PORT
      LAYER met3 ;
        RECT 1313.350 -707.755 1313.650 -707.455 ;
    END
  END pixRst_BOT<86>
  PIN pixRst_BOT<87>
    ANTENNAGATEAREA 4.032000 ;
    PORT
      LAYER met3 ;
        RECT 1335.445 -707.755 1335.745 -707.455 ;
    END
  END pixRst_BOT<87>
  PIN pixRst_BOT<88>
    ANTENNAGATEAREA 4.032000 ;
    PORT
      LAYER met3 ;
        RECT 1337.350 -707.755 1337.650 -707.455 ;
    END
  END pixRst_BOT<88>
  PIN pixRst_BOT<89>
    ANTENNAGATEAREA 4.032000 ;
    PORT
      LAYER met3 ;
        RECT 1359.445 -707.755 1359.745 -707.455 ;
    END
  END pixRst_BOT<89>
  PIN pixRst_BOT<90>
    ANTENNAGATEAREA 4.032000 ;
    PORT
      LAYER met3 ;
        RECT 1361.350 -707.755 1361.650 -707.455 ;
    END
  END pixRst_BOT<90>
  PIN pixRst_BOT<91>
    ANTENNAGATEAREA 4.032000 ;
    PORT
      LAYER met3 ;
        RECT 1383.445 -707.755 1383.745 -707.455 ;
    END
  END pixRst_BOT<91>
  PIN pixRst_BOT<92>
    ANTENNAGATEAREA 4.032000 ;
    PORT
      LAYER met3 ;
        RECT 1385.350 -707.755 1385.650 -707.455 ;
    END
  END pixRst_BOT<92>
  PIN pixRst_BOT<93>
    ANTENNAGATEAREA 4.032000 ;
    PORT
      LAYER met3 ;
        RECT 1407.445 -707.755 1407.745 -707.455 ;
    END
  END pixRst_BOT<93>
  PIN pixRst_BOT<94>
    ANTENNAGATEAREA 4.032000 ;
    PORT
      LAYER met3 ;
        RECT 1409.350 -707.755 1409.650 -707.455 ;
    END
  END pixRst_BOT<94>
  PIN pixRst_BOT<95>
    ANTENNAGATEAREA 4.032000 ;
    PORT
      LAYER met3 ;
        RECT 1431.445 -707.755 1431.745 -707.455 ;
    END
  END pixRst_BOT<95>
  PIN pixRst_BOT<96>
    ANTENNAGATEAREA 4.032000 ;
    PORT
      LAYER met3 ;
        RECT 1433.350 -707.755 1433.650 -707.455 ;
    END
  END pixRst_BOT<96>
  PIN pixRst_BOT<97>
    ANTENNAGATEAREA 4.032000 ;
    PORT
      LAYER met3 ;
        RECT 1455.445 -707.755 1455.745 -707.455 ;
    END
  END pixRst_BOT<97>
  PIN pixRst_BOT<98>
    ANTENNAGATEAREA 4.032000 ;
    PORT
      LAYER met3 ;
        RECT 1457.350 -707.755 1457.650 -707.455 ;
    END
  END pixRst_BOT<98>
  PIN pixRst_BOT<99>
    ANTENNAGATEAREA 4.032000 ;
    PORT
      LAYER met3 ;
        RECT 1479.445 -707.755 1479.745 -707.455 ;
    END
  END pixRst_BOT<99>
  PIN pixRst_BOT<100>
    ANTENNAGATEAREA 4.032000 ;
    PORT
      LAYER met3 ;
        RECT 1481.350 -707.755 1481.650 -707.455 ;
    END
  END pixRst_BOT<100>
  PIN pixRst_BOT<101>
    ANTENNAGATEAREA 4.032000 ;
    PORT
      LAYER met3 ;
        RECT 1503.445 -707.755 1503.745 -707.455 ;
    END
  END pixRst_BOT<101>
  PIN pixRst_BOT<102>
    ANTENNAGATEAREA 4.032000 ;
    PORT
      LAYER met3 ;
        RECT 1505.350 -707.755 1505.650 -707.455 ;
    END
  END pixRst_BOT<102>
  PIN pixRst_BOT<103>
    ANTENNAGATEAREA 4.032000 ;
    PORT
      LAYER met3 ;
        RECT 1527.445 -707.755 1527.745 -707.455 ;
    END
  END pixRst_BOT<103>
  PIN pixRst_BOT<104>
    ANTENNAGATEAREA 4.032000 ;
    PORT
      LAYER met3 ;
        RECT 1529.350 -707.755 1529.650 -707.455 ;
    END
  END pixRst_BOT<104>
  PIN pixRst_BOT<105>
    ANTENNAGATEAREA 4.032000 ;
    PORT
      LAYER met3 ;
        RECT 1551.445 -707.755 1551.745 -707.455 ;
    END
  END pixRst_BOT<105>
  PIN pixRst_BOT<106>
    ANTENNAGATEAREA 4.032000 ;
    PORT
      LAYER met3 ;
        RECT 1553.350 -707.755 1553.650 -707.455 ;
    END
  END pixRst_BOT<106>
  PIN pixRst_BOT<107>
    ANTENNAGATEAREA 4.032000 ;
    PORT
      LAYER met3 ;
        RECT 1575.445 -707.755 1575.745 -707.455 ;
    END
  END pixRst_BOT<107>
  PIN pixRst_BOT<108>
    ANTENNAGATEAREA 4.032000 ;
    PORT
      LAYER met3 ;
        RECT 1577.350 -707.755 1577.650 -707.455 ;
    END
  END pixRst_BOT<108>
  PIN pixRst_BOT<109>
    ANTENNAGATEAREA 4.032000 ;
    PORT
      LAYER met3 ;
        RECT 1599.445 -707.755 1599.745 -707.455 ;
    END
  END pixRst_BOT<109>
  PIN pixRst_BOT<110>
    ANTENNAGATEAREA 4.032000 ;
    PORT
      LAYER met3 ;
        RECT 1601.350 -707.755 1601.650 -707.455 ;
    END
  END pixRst_BOT<110>
  PIN pixRst_BOT<111>
    ANTENNAGATEAREA 4.032000 ;
    PORT
      LAYER met3 ;
        RECT 1623.445 -707.755 1623.745 -707.455 ;
    END
  END pixRst_BOT<111>
  PIN pixRst_BOT<112>
    ANTENNAGATEAREA 4.032000 ;
    PORT
      LAYER met3 ;
        RECT 1625.350 -707.755 1625.650 -707.455 ;
    END
  END pixRst_BOT<112>
  PIN pixRst_BOT<113>
    ANTENNAGATEAREA 4.032000 ;
    PORT
      LAYER met3 ;
        RECT 1647.445 -707.755 1647.745 -707.455 ;
    END
  END pixRst_BOT<113>
  PIN pixRst_BOT<114>
    ANTENNAGATEAREA 4.032000 ;
    PORT
      LAYER met3 ;
        RECT 1649.350 -707.755 1649.650 -707.455 ;
    END
  END pixRst_BOT<114>
  PIN pixRst_BOT<115>
    ANTENNAGATEAREA 4.032000 ;
    PORT
      LAYER met3 ;
        RECT 1671.445 -707.755 1671.745 -707.455 ;
    END
  END pixRst_BOT<115>
  PIN pixRst_BOT<116>
    ANTENNAGATEAREA 4.032000 ;
    PORT
      LAYER met3 ;
        RECT 1673.350 -707.755 1673.650 -707.455 ;
    END
  END pixRst_BOT<116>
  PIN pixRst_BOT<117>
    ANTENNAGATEAREA 4.032000 ;
    PORT
      LAYER met3 ;
        RECT 1695.445 -707.755 1695.745 -707.455 ;
    END
  END pixRst_BOT<117>
  PIN pixRst_BOT<118>
    ANTENNAGATEAREA 4.032000 ;
    PORT
      LAYER met3 ;
        RECT 1697.350 -707.755 1697.650 -707.455 ;
    END
  END pixRst_BOT<118>
  PIN pixRst_BOT<119>
    ANTENNAGATEAREA 4.032000 ;
    PORT
      LAYER met3 ;
        RECT 1719.445 -707.755 1719.745 -707.455 ;
    END
  END pixRst_BOT<119>
  PIN pixRst_BOT<120>
    ANTENNAGATEAREA 4.032000 ;
    PORT
      LAYER met3 ;
        RECT 1721.350 -707.755 1721.650 -707.455 ;
    END
  END pixRst_BOT<120>
  PIN pixRst_BOT<121>
    ANTENNAGATEAREA 4.032000 ;
    PORT
      LAYER met3 ;
        RECT 1743.445 -707.755 1743.745 -707.455 ;
    END
  END pixRst_BOT<121>
  PIN pixRst_BOT<122>
    ANTENNAGATEAREA 4.032000 ;
    PORT
      LAYER met3 ;
        RECT 1745.350 -707.755 1745.650 -707.455 ;
    END
  END pixRst_BOT<122>
  PIN pixRst_BOT<123>
    ANTENNAGATEAREA 4.032000 ;
    PORT
      LAYER met3 ;
        RECT 1767.445 -707.755 1767.745 -707.455 ;
    END
  END pixRst_BOT<123>
  PIN pixRst_BOT<124>
    ANTENNAGATEAREA 4.032000 ;
    PORT
      LAYER met3 ;
        RECT 1769.350 -707.755 1769.650 -707.455 ;
    END
  END pixRst_BOT<124>
  PIN pixRst_BOT<125>
    ANTENNAGATEAREA 4.032000 ;
    PORT
      LAYER met3 ;
        RECT 1791.445 -707.755 1791.745 -707.455 ;
    END
  END pixRst_BOT<125>
  PIN pixRst_BOT<126>
    ANTENNAGATEAREA 4.032000 ;
    PORT
      LAYER met3 ;
        RECT 1793.350 -707.755 1793.650 -707.455 ;
    END
  END pixRst_BOT<126>
  PIN pixRst_BOT<127>
    ANTENNAGATEAREA 4.032000 ;
    PORT
      LAYER met3 ;
        RECT 1815.445 -707.755 1815.745 -707.455 ;
    END
  END pixRst_BOT<127>
  PIN voutn_TOP<0>
    ANTENNADIFFAREA 0.870000 ;
    PORT
      LAYER met3 ;
        RECT 284.095 926.010 284.865 926.310 ;
    END
  END voutn_TOP<0>
  PIN voutn_TOP<1>
    ANTENNADIFFAREA 0.870000 ;
    PORT
      LAYER met3 ;
        RECT 300.215 926.010 300.985 926.310 ;
    END
  END voutn_TOP<1>
  PIN voutn_TOP<2>
    ANTENNADIFFAREA 0.870000 ;
    PORT
      LAYER met3 ;
        RECT 308.095 926.010 308.865 926.310 ;
    END
  END voutn_TOP<2>
  PIN voutn_TOP<3>
    ANTENNADIFFAREA 0.870000 ;
    PORT
      LAYER met3 ;
        RECT 324.215 926.010 324.985 926.310 ;
    END
  END voutn_TOP<3>
  PIN voutn_TOP<4>
    ANTENNADIFFAREA 0.870000 ;
    PORT
      LAYER met3 ;
        RECT 332.095 926.010 332.865 926.310 ;
    END
  END voutn_TOP<4>
  PIN voutn_TOP<5>
    ANTENNADIFFAREA 0.870000 ;
    PORT
      LAYER met3 ;
        RECT 348.215 926.010 348.985 926.310 ;
    END
  END voutn_TOP<5>
  PIN voutn_TOP<6>
    ANTENNADIFFAREA 0.870000 ;
    PORT
      LAYER met3 ;
        RECT 356.095 926.010 356.865 926.310 ;
    END
  END voutn_TOP<6>
  PIN voutn_TOP<7>
    ANTENNADIFFAREA 0.870000 ;
    PORT
      LAYER met3 ;
        RECT 372.215 926.010 372.985 926.310 ;
    END
  END voutn_TOP<7>
  PIN voutn_TOP<8>
    ANTENNADIFFAREA 0.870000 ;
    PORT
      LAYER met3 ;
        RECT 380.095 926.010 380.865 926.310 ;
    END
  END voutn_TOP<8>
  PIN voutn_TOP<9>
    ANTENNADIFFAREA 0.870000 ;
    PORT
      LAYER met3 ;
        RECT 396.215 926.010 396.985 926.310 ;
    END
  END voutn_TOP<9>
  PIN voutn_TOP<10>
    ANTENNADIFFAREA 0.870000 ;
    PORT
      LAYER met3 ;
        RECT 404.095 926.010 404.865 926.310 ;
    END
  END voutn_TOP<10>
  PIN voutn_TOP<11>
    ANTENNADIFFAREA 0.870000 ;
    PORT
      LAYER met3 ;
        RECT 420.215 926.010 420.985 926.310 ;
    END
  END voutn_TOP<11>
  PIN voutn_TOP<12>
    ANTENNADIFFAREA 0.870000 ;
    PORT
      LAYER met3 ;
        RECT 428.095 926.010 428.865 926.310 ;
    END
  END voutn_TOP<12>
  PIN voutn_TOP<13>
    ANTENNADIFFAREA 0.870000 ;
    PORT
      LAYER met3 ;
        RECT 444.215 926.010 444.985 926.310 ;
    END
  END voutn_TOP<13>
  PIN voutn_TOP<14>
    ANTENNADIFFAREA 0.870000 ;
    PORT
      LAYER met3 ;
        RECT 452.095 926.010 452.865 926.310 ;
    END
  END voutn_TOP<14>
  PIN voutn_TOP<15>
    ANTENNADIFFAREA 0.870000 ;
    PORT
      LAYER met3 ;
        RECT 468.215 926.010 468.985 926.310 ;
    END
  END voutn_TOP<15>
  PIN voutn_TOP<16>
    ANTENNADIFFAREA 0.870000 ;
    PORT
      LAYER met3 ;
        RECT 476.095 926.010 476.865 926.310 ;
    END
  END voutn_TOP<16>
  PIN voutn_TOP<17>
    ANTENNADIFFAREA 0.870000 ;
    PORT
      LAYER met3 ;
        RECT 492.215 926.010 492.985 926.310 ;
    END
  END voutn_TOP<17>
  PIN voutn_TOP<18>
    ANTENNADIFFAREA 0.870000 ;
    PORT
      LAYER met3 ;
        RECT 500.095 926.010 500.865 926.310 ;
    END
  END voutn_TOP<18>
  PIN voutn_TOP<19>
    ANTENNADIFFAREA 0.870000 ;
    PORT
      LAYER met3 ;
        RECT 516.215 926.010 516.985 926.310 ;
    END
  END voutn_TOP<19>
  PIN voutn_TOP<20>
    ANTENNADIFFAREA 0.870000 ;
    PORT
      LAYER met3 ;
        RECT 524.095 926.010 524.865 926.310 ;
    END
  END voutn_TOP<20>
  PIN voutn_TOP<21>
    ANTENNADIFFAREA 0.870000 ;
    PORT
      LAYER met3 ;
        RECT 540.215 926.010 540.985 926.310 ;
    END
  END voutn_TOP<21>
  PIN voutn_TOP<22>
    ANTENNADIFFAREA 0.870000 ;
    PORT
      LAYER met3 ;
        RECT 548.095 926.010 548.865 926.310 ;
    END
  END voutn_TOP<22>
  PIN voutn_TOP<23>
    ANTENNADIFFAREA 0.870000 ;
    PORT
      LAYER met3 ;
        RECT 564.215 926.010 564.985 926.310 ;
    END
  END voutn_TOP<23>
  PIN voutn_TOP<24>
    ANTENNADIFFAREA 0.870000 ;
    PORT
      LAYER met3 ;
        RECT 572.095 926.010 572.865 926.310 ;
    END
  END voutn_TOP<24>
  PIN voutn_TOP<25>
    ANTENNADIFFAREA 0.870000 ;
    PORT
      LAYER met3 ;
        RECT 588.215 926.010 588.985 926.310 ;
    END
  END voutn_TOP<25>
  PIN voutn_TOP<26>
    ANTENNADIFFAREA 0.870000 ;
    PORT
      LAYER met3 ;
        RECT 596.095 926.010 596.865 926.310 ;
    END
  END voutn_TOP<26>
  PIN voutn_TOP<27>
    ANTENNADIFFAREA 0.870000 ;
    PORT
      LAYER met3 ;
        RECT 612.215 926.010 612.985 926.310 ;
    END
  END voutn_TOP<27>
  PIN voutn_TOP<28>
    ANTENNADIFFAREA 0.870000 ;
    PORT
      LAYER met3 ;
        RECT 620.095 926.010 620.865 926.310 ;
    END
  END voutn_TOP<28>
  PIN voutn_TOP<29>
    ANTENNADIFFAREA 0.870000 ;
    PORT
      LAYER met3 ;
        RECT 636.215 926.010 636.985 926.310 ;
    END
  END voutn_TOP<29>
  PIN voutn_TOP<30>
    ANTENNADIFFAREA 0.870000 ;
    PORT
      LAYER met3 ;
        RECT 644.095 926.010 644.865 926.310 ;
    END
  END voutn_TOP<30>
  PIN voutn_TOP<31>
    ANTENNADIFFAREA 0.870000 ;
    PORT
      LAYER met3 ;
        RECT 660.215 926.010 660.985 926.310 ;
    END
  END voutn_TOP<31>
  PIN voutn_TOP<32>
    ANTENNADIFFAREA 0.870000 ;
    PORT
      LAYER met3 ;
        RECT 668.095 926.010 668.865 926.310 ;
    END
  END voutn_TOP<32>
  PIN voutn_TOP<33>
    ANTENNADIFFAREA 0.870000 ;
    PORT
      LAYER met3 ;
        RECT 684.215 926.010 684.985 926.310 ;
    END
  END voutn_TOP<33>
  PIN voutn_TOP<34>
    ANTENNADIFFAREA 0.870000 ;
    PORT
      LAYER met3 ;
        RECT 692.095 926.010 692.865 926.310 ;
    END
  END voutn_TOP<34>
  PIN voutn_TOP<35>
    ANTENNADIFFAREA 0.870000 ;
    PORT
      LAYER met3 ;
        RECT 708.215 926.010 708.985 926.310 ;
    END
  END voutn_TOP<35>
  PIN voutn_TOP<36>
    ANTENNADIFFAREA 0.870000 ;
    PORT
      LAYER met3 ;
        RECT 716.095 926.010 716.865 926.310 ;
    END
  END voutn_TOP<36>
  PIN voutn_TOP<37>
    ANTENNADIFFAREA 0.870000 ;
    PORT
      LAYER met3 ;
        RECT 732.215 926.010 732.985 926.310 ;
    END
  END voutn_TOP<37>
  PIN voutn_TOP<38>
    ANTENNADIFFAREA 0.870000 ;
    PORT
      LAYER met3 ;
        RECT 740.095 926.010 740.865 926.310 ;
    END
  END voutn_TOP<38>
  PIN voutn_TOP<39>
    ANTENNADIFFAREA 0.870000 ;
    PORT
      LAYER met3 ;
        RECT 756.215 926.010 756.985 926.310 ;
    END
  END voutn_TOP<39>
  PIN voutn_TOP<40>
    ANTENNADIFFAREA 0.870000 ;
    PORT
      LAYER met3 ;
        RECT 764.095 926.010 764.865 926.310 ;
    END
  END voutn_TOP<40>
  PIN voutn_TOP<41>
    ANTENNADIFFAREA 0.870000 ;
    PORT
      LAYER met3 ;
        RECT 780.215 926.010 780.985 926.310 ;
    END
  END voutn_TOP<41>
  PIN voutn_TOP<42>
    ANTENNADIFFAREA 0.870000 ;
    PORT
      LAYER met3 ;
        RECT 788.095 926.010 788.865 926.310 ;
    END
  END voutn_TOP<42>
  PIN voutn_TOP<43>
    ANTENNADIFFAREA 0.870000 ;
    PORT
      LAYER met3 ;
        RECT 804.215 926.010 804.985 926.310 ;
    END
  END voutn_TOP<43>
  PIN voutn_TOP<44>
    ANTENNADIFFAREA 0.870000 ;
    PORT
      LAYER met3 ;
        RECT 812.095 926.010 812.865 926.310 ;
    END
  END voutn_TOP<44>
  PIN voutn_TOP<45>
    ANTENNADIFFAREA 0.870000 ;
    PORT
      LAYER met3 ;
        RECT 828.215 926.010 828.985 926.310 ;
    END
  END voutn_TOP<45>
  PIN voutn_TOP<46>
    ANTENNADIFFAREA 0.870000 ;
    PORT
      LAYER met3 ;
        RECT 836.095 926.010 836.865 926.310 ;
    END
  END voutn_TOP<46>
  PIN voutn_TOP<47>
    ANTENNADIFFAREA 0.870000 ;
    PORT
      LAYER met3 ;
        RECT 852.215 926.010 852.985 926.310 ;
    END
  END voutn_TOP<47>
  PIN voutn_TOP<48>
    ANTENNADIFFAREA 0.870000 ;
    PORT
      LAYER met3 ;
        RECT 860.095 926.010 860.865 926.310 ;
    END
  END voutn_TOP<48>
  PIN voutn_TOP<49>
    ANTENNADIFFAREA 0.870000 ;
    PORT
      LAYER met3 ;
        RECT 876.215 926.010 876.985 926.310 ;
    END
  END voutn_TOP<49>
  PIN voutn_TOP<50>
    ANTENNADIFFAREA 0.870000 ;
    PORT
      LAYER met3 ;
        RECT 884.095 926.010 884.865 926.310 ;
    END
  END voutn_TOP<50>
  PIN voutn_TOP<51>
    ANTENNADIFFAREA 0.870000 ;
    PORT
      LAYER met3 ;
        RECT 900.215 926.010 900.985 926.310 ;
    END
  END voutn_TOP<51>
  PIN voutn_TOP<52>
    ANTENNADIFFAREA 0.870000 ;
    PORT
      LAYER met3 ;
        RECT 908.095 926.010 908.865 926.310 ;
    END
  END voutn_TOP<52>
  PIN voutn_TOP<53>
    ANTENNADIFFAREA 0.870000 ;
    PORT
      LAYER met3 ;
        RECT 924.215 926.010 924.985 926.310 ;
    END
  END voutn_TOP<53>
  PIN voutn_TOP<54>
    ANTENNADIFFAREA 0.870000 ;
    PORT
      LAYER met3 ;
        RECT 932.095 926.010 932.865 926.310 ;
    END
  END voutn_TOP<54>
  PIN voutn_TOP<55>
    ANTENNADIFFAREA 0.870000 ;
    PORT
      LAYER met3 ;
        RECT 948.215 926.010 948.985 926.310 ;
    END
  END voutn_TOP<55>
  PIN voutn_TOP<56>
    ANTENNADIFFAREA 0.870000 ;
    PORT
      LAYER met3 ;
        RECT 956.095 926.010 956.865 926.310 ;
    END
  END voutn_TOP<56>
  PIN voutn_TOP<57>
    ANTENNADIFFAREA 0.870000 ;
    PORT
      LAYER met3 ;
        RECT 972.215 926.010 972.985 926.310 ;
    END
  END voutn_TOP<57>
  PIN voutn_TOP<58>
    ANTENNADIFFAREA 0.870000 ;
    PORT
      LAYER met3 ;
        RECT 980.095 926.010 980.865 926.310 ;
    END
  END voutn_TOP<58>
  PIN voutn_TOP<59>
    ANTENNADIFFAREA 0.870000 ;
    PORT
      LAYER met3 ;
        RECT 996.215 926.010 996.985 926.310 ;
    END
  END voutn_TOP<59>
  PIN voutn_TOP<60>
    ANTENNADIFFAREA 0.870000 ;
    PORT
      LAYER met3 ;
        RECT 1004.095 926.010 1004.865 926.310 ;
    END
  END voutn_TOP<60>
  PIN voutn_TOP<61>
    ANTENNADIFFAREA 0.870000 ;
    PORT
      LAYER met3 ;
        RECT 1020.215 926.010 1020.985 926.310 ;
    END
  END voutn_TOP<61>
  PIN voutn_TOP<62>
    ANTENNADIFFAREA 0.870000 ;
    PORT
      LAYER met3 ;
        RECT 1028.095 926.010 1028.865 926.310 ;
    END
  END voutn_TOP<62>
  PIN voutn_TOP<63>
    ANTENNADIFFAREA 0.870000 ;
    PORT
      LAYER met3 ;
        RECT 1044.215 926.010 1044.985 926.310 ;
    END
  END voutn_TOP<63>
  PIN voutn_TOP<64>
    ANTENNADIFFAREA 0.870000 ;
    PORT
      LAYER met3 ;
        RECT 1052.095 926.010 1052.865 926.310 ;
    END
  END voutn_TOP<64>
  PIN voutn_TOP<65>
    ANTENNADIFFAREA 0.870000 ;
    PORT
      LAYER met3 ;
        RECT 1068.215 926.010 1068.985 926.310 ;
    END
  END voutn_TOP<65>
  PIN voutn_TOP<66>
    ANTENNADIFFAREA 0.870000 ;
    PORT
      LAYER met3 ;
        RECT 1076.095 926.010 1076.865 926.310 ;
    END
  END voutn_TOP<66>
  PIN voutn_TOP<67>
    ANTENNADIFFAREA 0.870000 ;
    PORT
      LAYER met3 ;
        RECT 1092.215 926.010 1092.985 926.310 ;
    END
  END voutn_TOP<67>
  PIN voutn_TOP<68>
    ANTENNADIFFAREA 0.870000 ;
    PORT
      LAYER met3 ;
        RECT 1100.095 926.010 1100.865 926.310 ;
    END
  END voutn_TOP<68>
  PIN voutn_TOP<69>
    ANTENNADIFFAREA 0.870000 ;
    PORT
      LAYER met3 ;
        RECT 1116.215 926.010 1116.985 926.310 ;
    END
  END voutn_TOP<69>
  PIN voutn_TOP<70>
    ANTENNADIFFAREA 0.870000 ;
    PORT
      LAYER met3 ;
        RECT 1124.095 926.010 1124.865 926.310 ;
    END
  END voutn_TOP<70>
  PIN voutn_TOP<71>
    ANTENNADIFFAREA 0.870000 ;
    PORT
      LAYER met3 ;
        RECT 1140.215 926.010 1140.985 926.310 ;
    END
  END voutn_TOP<71>
  PIN voutn_TOP<72>
    ANTENNADIFFAREA 0.870000 ;
    PORT
      LAYER met3 ;
        RECT 1148.095 926.010 1148.865 926.310 ;
    END
  END voutn_TOP<72>
  PIN voutn_TOP<73>
    ANTENNADIFFAREA 0.870000 ;
    PORT
      LAYER met3 ;
        RECT 1164.215 926.010 1164.985 926.310 ;
    END
  END voutn_TOP<73>
  PIN voutn_TOP<74>
    ANTENNADIFFAREA 0.870000 ;
    PORT
      LAYER met3 ;
        RECT 1172.095 926.010 1172.865 926.310 ;
    END
  END voutn_TOP<74>
  PIN voutn_TOP<75>
    ANTENNADIFFAREA 0.870000 ;
    PORT
      LAYER met3 ;
        RECT 1188.215 926.010 1188.985 926.310 ;
    END
  END voutn_TOP<75>
  PIN voutn_TOP<76>
    ANTENNADIFFAREA 0.870000 ;
    PORT
      LAYER met3 ;
        RECT 1196.095 926.010 1196.865 926.310 ;
    END
  END voutn_TOP<76>
  PIN voutn_TOP<77>
    ANTENNADIFFAREA 0.870000 ;
    PORT
      LAYER met3 ;
        RECT 1212.215 926.010 1212.985 926.310 ;
    END
  END voutn_TOP<77>
  PIN voutn_TOP<78>
    ANTENNADIFFAREA 0.870000 ;
    PORT
      LAYER met3 ;
        RECT 1220.095 926.010 1220.865 926.310 ;
    END
  END voutn_TOP<78>
  PIN voutn_TOP<79>
    ANTENNADIFFAREA 0.870000 ;
    PORT
      LAYER met3 ;
        RECT 1236.215 926.010 1236.985 926.310 ;
    END
  END voutn_TOP<79>
  PIN voutn_TOP<80>
    ANTENNADIFFAREA 0.870000 ;
    PORT
      LAYER met3 ;
        RECT 1244.095 926.010 1244.865 926.310 ;
    END
  END voutn_TOP<80>
  PIN voutn_TOP<81>
    ANTENNADIFFAREA 0.870000 ;
    PORT
      LAYER met3 ;
        RECT 1260.215 926.010 1260.985 926.310 ;
    END
  END voutn_TOP<81>
  PIN voutn_TOP<82>
    ANTENNADIFFAREA 0.870000 ;
    PORT
      LAYER met3 ;
        RECT 1268.095 926.010 1268.865 926.310 ;
    END
  END voutn_TOP<82>
  PIN voutn_TOP<83>
    ANTENNADIFFAREA 0.870000 ;
    PORT
      LAYER met3 ;
        RECT 1284.215 926.010 1284.985 926.310 ;
    END
  END voutn_TOP<83>
  PIN voutn_TOP<84>
    ANTENNADIFFAREA 0.870000 ;
    PORT
      LAYER met3 ;
        RECT 1292.095 926.010 1292.865 926.310 ;
    END
  END voutn_TOP<84>
  PIN voutn_TOP<85>
    ANTENNADIFFAREA 0.870000 ;
    PORT
      LAYER met3 ;
        RECT 1308.215 926.010 1308.985 926.310 ;
    END
  END voutn_TOP<85>
  PIN voutn_TOP<86>
    ANTENNADIFFAREA 0.870000 ;
    PORT
      LAYER met3 ;
        RECT 1316.095 926.010 1316.865 926.310 ;
    END
  END voutn_TOP<86>
  PIN voutn_TOP<87>
    ANTENNADIFFAREA 0.870000 ;
    PORT
      LAYER met3 ;
        RECT 1332.215 926.010 1332.985 926.310 ;
    END
  END voutn_TOP<87>
  PIN voutn_TOP<88>
    ANTENNADIFFAREA 0.870000 ;
    PORT
      LAYER met3 ;
        RECT 1340.095 926.010 1340.865 926.310 ;
    END
  END voutn_TOP<88>
  PIN voutn_TOP<89>
    ANTENNADIFFAREA 0.870000 ;
    PORT
      LAYER met3 ;
        RECT 1356.215 926.010 1356.985 926.310 ;
    END
  END voutn_TOP<89>
  PIN voutn_TOP<90>
    ANTENNADIFFAREA 0.870000 ;
    PORT
      LAYER met3 ;
        RECT 1364.095 926.010 1364.865 926.310 ;
    END
  END voutn_TOP<90>
  PIN voutn_TOP<91>
    ANTENNADIFFAREA 0.870000 ;
    PORT
      LAYER met3 ;
        RECT 1380.215 926.010 1380.985 926.310 ;
    END
  END voutn_TOP<91>
  PIN voutn_TOP<92>
    ANTENNADIFFAREA 0.870000 ;
    PORT
      LAYER met3 ;
        RECT 1388.095 926.010 1388.865 926.310 ;
    END
  END voutn_TOP<92>
  PIN voutn_TOP<93>
    ANTENNADIFFAREA 0.870000 ;
    PORT
      LAYER met3 ;
        RECT 1404.215 926.010 1404.985 926.310 ;
    END
  END voutn_TOP<93>
  PIN voutn_TOP<94>
    ANTENNADIFFAREA 0.870000 ;
    PORT
      LAYER met3 ;
        RECT 1412.095 926.010 1412.865 926.310 ;
    END
  END voutn_TOP<94>
  PIN voutn_TOP<95>
    ANTENNADIFFAREA 0.870000 ;
    PORT
      LAYER met3 ;
        RECT 1428.215 926.010 1428.985 926.310 ;
    END
  END voutn_TOP<95>
  PIN voutn_TOP<96>
    ANTENNADIFFAREA 0.870000 ;
    PORT
      LAYER met3 ;
        RECT 1436.095 926.010 1436.865 926.310 ;
    END
  END voutn_TOP<96>
  PIN voutn_TOP<97>
    ANTENNADIFFAREA 0.870000 ;
    PORT
      LAYER met3 ;
        RECT 1452.215 926.010 1452.985 926.310 ;
    END
  END voutn_TOP<97>
  PIN voutn_TOP<98>
    ANTENNADIFFAREA 0.870000 ;
    PORT
      LAYER met3 ;
        RECT 1460.095 926.010 1460.865 926.310 ;
    END
  END voutn_TOP<98>
  PIN voutn_TOP<99>
    ANTENNADIFFAREA 0.870000 ;
    PORT
      LAYER met3 ;
        RECT 1476.215 926.010 1476.985 926.310 ;
    END
  END voutn_TOP<99>
  PIN voutn_TOP<100>
    ANTENNADIFFAREA 0.870000 ;
    PORT
      LAYER met3 ;
        RECT 1484.095 926.010 1484.865 926.310 ;
    END
  END voutn_TOP<100>
  PIN voutn_TOP<101>
    ANTENNADIFFAREA 0.870000 ;
    PORT
      LAYER met3 ;
        RECT 1500.215 926.010 1500.985 926.310 ;
    END
  END voutn_TOP<101>
  PIN voutn_TOP<102>
    ANTENNADIFFAREA 0.870000 ;
    PORT
      LAYER met3 ;
        RECT 1508.095 926.010 1508.865 926.310 ;
    END
  END voutn_TOP<102>
  PIN voutn_TOP<103>
    ANTENNADIFFAREA 0.870000 ;
    PORT
      LAYER met3 ;
        RECT 1524.215 926.010 1524.985 926.310 ;
    END
  END voutn_TOP<103>
  PIN voutn_TOP<104>
    ANTENNADIFFAREA 0.870000 ;
    PORT
      LAYER met3 ;
        RECT 1532.095 926.010 1532.865 926.310 ;
    END
  END voutn_TOP<104>
  PIN voutn_TOP<105>
    ANTENNADIFFAREA 0.870000 ;
    PORT
      LAYER met3 ;
        RECT 1548.215 926.010 1548.985 926.310 ;
    END
  END voutn_TOP<105>
  PIN voutn_TOP<106>
    ANTENNADIFFAREA 0.870000 ;
    PORT
      LAYER met3 ;
        RECT 1556.095 926.010 1556.865 926.310 ;
    END
  END voutn_TOP<106>
  PIN voutn_TOP<107>
    ANTENNADIFFAREA 0.870000 ;
    PORT
      LAYER met3 ;
        RECT 1572.215 926.010 1572.985 926.310 ;
    END
  END voutn_TOP<107>
  PIN voutn_TOP<108>
    ANTENNADIFFAREA 0.870000 ;
    PORT
      LAYER met3 ;
        RECT 1580.095 926.010 1580.865 926.310 ;
    END
  END voutn_TOP<108>
  PIN voutn_TOP<109>
    ANTENNADIFFAREA 0.870000 ;
    PORT
      LAYER met3 ;
        RECT 1596.215 926.010 1596.985 926.310 ;
    END
  END voutn_TOP<109>
  PIN voutn_TOP<110>
    ANTENNADIFFAREA 0.870000 ;
    PORT
      LAYER met3 ;
        RECT 1604.095 926.010 1604.865 926.310 ;
    END
  END voutn_TOP<110>
  PIN voutn_TOP<111>
    ANTENNADIFFAREA 0.870000 ;
    PORT
      LAYER met3 ;
        RECT 1620.215 926.010 1620.985 926.310 ;
    END
  END voutn_TOP<111>
  PIN voutn_TOP<112>
    ANTENNADIFFAREA 0.870000 ;
    PORT
      LAYER met3 ;
        RECT 1628.095 926.010 1628.865 926.310 ;
    END
  END voutn_TOP<112>
  PIN voutn_TOP<113>
    ANTENNADIFFAREA 0.870000 ;
    PORT
      LAYER met3 ;
        RECT 1644.215 926.010 1644.985 926.310 ;
    END
  END voutn_TOP<113>
  PIN voutn_TOP<114>
    ANTENNADIFFAREA 0.870000 ;
    PORT
      LAYER met3 ;
        RECT 1652.095 926.010 1652.865 926.310 ;
    END
  END voutn_TOP<114>
  PIN voutn_TOP<115>
    ANTENNADIFFAREA 0.870000 ;
    PORT
      LAYER met3 ;
        RECT 1668.215 926.010 1668.985 926.310 ;
    END
  END voutn_TOP<115>
  PIN voutn_TOP<116>
    ANTENNADIFFAREA 0.870000 ;
    PORT
      LAYER met3 ;
        RECT 1676.095 926.010 1676.865 926.310 ;
    END
  END voutn_TOP<116>
  PIN voutn_TOP<117>
    ANTENNADIFFAREA 0.870000 ;
    PORT
      LAYER met3 ;
        RECT 1692.215 926.010 1692.985 926.310 ;
    END
  END voutn_TOP<117>
  PIN voutn_TOP<118>
    ANTENNADIFFAREA 0.870000 ;
    PORT
      LAYER met3 ;
        RECT 1700.095 926.010 1700.865 926.310 ;
    END
  END voutn_TOP<118>
  PIN voutn_TOP<119>
    ANTENNADIFFAREA 0.870000 ;
    PORT
      LAYER met3 ;
        RECT 1716.215 926.010 1716.985 926.310 ;
    END
  END voutn_TOP<119>
  PIN voutn_TOP<120>
    ANTENNADIFFAREA 0.870000 ;
    PORT
      LAYER met3 ;
        RECT 1724.095 926.010 1724.865 926.310 ;
    END
  END voutn_TOP<120>
  PIN voutn_TOP<121>
    ANTENNADIFFAREA 0.870000 ;
    PORT
      LAYER met3 ;
        RECT 1740.215 926.010 1740.985 926.310 ;
    END
  END voutn_TOP<121>
  PIN voutn_TOP<122>
    ANTENNADIFFAREA 0.870000 ;
    PORT
      LAYER met3 ;
        RECT 1748.095 926.010 1748.865 926.310 ;
    END
  END voutn_TOP<122>
  PIN voutn_TOP<123>
    ANTENNADIFFAREA 0.870000 ;
    PORT
      LAYER met3 ;
        RECT 1764.215 926.010 1764.985 926.310 ;
    END
  END voutn_TOP<123>
  PIN voutn_TOP<124>
    ANTENNADIFFAREA 0.870000 ;
    PORT
      LAYER met3 ;
        RECT 1772.095 926.010 1772.865 926.310 ;
    END
  END voutn_TOP<124>
  PIN voutn_TOP<125>
    ANTENNADIFFAREA 0.870000 ;
    PORT
      LAYER met3 ;
        RECT 1788.215 926.010 1788.985 926.310 ;
    END
  END voutn_TOP<125>
  PIN voutn_TOP<126>
    ANTENNADIFFAREA 0.870000 ;
    PORT
      LAYER met3 ;
        RECT 1796.095 926.010 1796.865 926.310 ;
    END
  END voutn_TOP<126>
  PIN voutn_TOP<127>
    ANTENNADIFFAREA 0.870000 ;
    PORT
      LAYER met3 ;
        RECT 1812.215 926.010 1812.985 926.310 ;
    END
  END voutn_TOP<127>
  PIN pixRst_TOP<0>
    ANTENNAGATEAREA 4.032000 ;
    PORT
      LAYER met3 ;
        RECT 281.350 925.890 281.650 926.190 ;
    END
  END pixRst_TOP<0>
  PIN pixRst_TOP<1>
    ANTENNAGATEAREA 4.032000 ;
    PORT
      LAYER met3 ;
        RECT 303.445 925.890 303.745 926.190 ;
    END
  END pixRst_TOP<1>
  PIN pixRst_TOP<2>
    ANTENNAGATEAREA 4.032000 ;
    PORT
      LAYER met3 ;
        RECT 305.350 925.890 305.650 926.190 ;
    END
  END pixRst_TOP<2>
  PIN pixRst_TOP<3>
    ANTENNAGATEAREA 4.032000 ;
    PORT
      LAYER met3 ;
        RECT 327.445 925.890 327.745 926.190 ;
    END
  END pixRst_TOP<3>
  PIN pixRst_TOP<4>
    ANTENNAGATEAREA 4.032000 ;
    PORT
      LAYER met3 ;
        RECT 329.350 925.890 329.650 926.190 ;
    END
  END pixRst_TOP<4>
  PIN pixRst_TOP<5>
    ANTENNAGATEAREA 4.032000 ;
    PORT
      LAYER met3 ;
        RECT 351.445 925.890 351.745 926.190 ;
    END
  END pixRst_TOP<5>
  PIN pixRst_TOP<6>
    ANTENNAGATEAREA 4.032000 ;
    PORT
      LAYER met3 ;
        RECT 353.350 925.890 353.650 926.190 ;
    END
  END pixRst_TOP<6>
  PIN pixRst_TOP<7>
    ANTENNAGATEAREA 4.032000 ;
    PORT
      LAYER met3 ;
        RECT 375.445 925.890 375.745 926.190 ;
    END
  END pixRst_TOP<7>
  PIN pixRst_TOP<8>
    ANTENNAGATEAREA 4.032000 ;
    PORT
      LAYER met3 ;
        RECT 377.350 925.890 377.650 926.190 ;
    END
  END pixRst_TOP<8>
  PIN pixRst_TOP<9>
    ANTENNAGATEAREA 4.032000 ;
    PORT
      LAYER met3 ;
        RECT 399.445 925.890 399.745 926.190 ;
    END
  END pixRst_TOP<9>
  PIN pixRst_TOP<10>
    ANTENNAGATEAREA 4.032000 ;
    PORT
      LAYER met3 ;
        RECT 401.350 925.890 401.650 926.190 ;
    END
  END pixRst_TOP<10>
  PIN pixRst_TOP<11>
    ANTENNAGATEAREA 4.032000 ;
    PORT
      LAYER met3 ;
        RECT 423.445 925.890 423.745 926.190 ;
    END
  END pixRst_TOP<11>
  PIN pixRst_TOP<12>
    ANTENNAGATEAREA 4.032000 ;
    PORT
      LAYER met3 ;
        RECT 425.350 925.890 425.650 926.190 ;
    END
  END pixRst_TOP<12>
  PIN pixRst_TOP<13>
    ANTENNAGATEAREA 4.032000 ;
    PORT
      LAYER met3 ;
        RECT 447.445 925.890 447.745 926.190 ;
    END
  END pixRst_TOP<13>
  PIN pixRst_TOP<14>
    ANTENNAGATEAREA 4.032000 ;
    PORT
      LAYER met3 ;
        RECT 449.350 925.890 449.650 926.190 ;
    END
  END pixRst_TOP<14>
  PIN pixRst_TOP<15>
    ANTENNAGATEAREA 4.032000 ;
    PORT
      LAYER met3 ;
        RECT 471.445 925.890 471.745 926.190 ;
    END
  END pixRst_TOP<15>
  PIN pixRst_TOP<16>
    ANTENNAGATEAREA 4.032000 ;
    PORT
      LAYER met3 ;
        RECT 473.350 925.890 473.650 926.190 ;
    END
  END pixRst_TOP<16>
  PIN pixRst_TOP<17>
    ANTENNAGATEAREA 4.032000 ;
    PORT
      LAYER met3 ;
        RECT 495.445 925.890 495.745 926.190 ;
    END
  END pixRst_TOP<17>
  PIN pixRst_TOP<18>
    ANTENNAGATEAREA 4.032000 ;
    PORT
      LAYER met3 ;
        RECT 497.350 925.890 497.650 926.190 ;
    END
  END pixRst_TOP<18>
  PIN pixRst_TOP<19>
    ANTENNAGATEAREA 4.032000 ;
    PORT
      LAYER met3 ;
        RECT 519.445 925.890 519.745 926.190 ;
    END
  END pixRst_TOP<19>
  PIN pixRst_TOP<20>
    ANTENNAGATEAREA 4.032000 ;
    PORT
      LAYER met3 ;
        RECT 521.350 925.890 521.650 926.190 ;
    END
  END pixRst_TOP<20>
  PIN pixRst_TOP<21>
    ANTENNAGATEAREA 4.032000 ;
    PORT
      LAYER met3 ;
        RECT 543.445 925.890 543.745 926.190 ;
    END
  END pixRst_TOP<21>
  PIN pixRst_TOP<22>
    ANTENNAGATEAREA 4.032000 ;
    PORT
      LAYER met3 ;
        RECT 545.350 925.890 545.650 926.190 ;
    END
  END pixRst_TOP<22>
  PIN pixRst_TOP<23>
    ANTENNAGATEAREA 4.032000 ;
    PORT
      LAYER met3 ;
        RECT 567.445 925.890 567.745 926.190 ;
    END
  END pixRst_TOP<23>
  PIN pixRst_TOP<24>
    ANTENNAGATEAREA 4.032000 ;
    PORT
      LAYER met3 ;
        RECT 569.350 925.890 569.650 926.190 ;
    END
  END pixRst_TOP<24>
  PIN pixRst_TOP<25>
    ANTENNAGATEAREA 4.032000 ;
    PORT
      LAYER met3 ;
        RECT 591.445 925.890 591.745 926.190 ;
    END
  END pixRst_TOP<25>
  PIN pixRst_TOP<26>
    ANTENNAGATEAREA 4.032000 ;
    PORT
      LAYER met3 ;
        RECT 593.350 925.890 593.650 926.190 ;
    END
  END pixRst_TOP<26>
  PIN pixRst_TOP<27>
    ANTENNAGATEAREA 4.032000 ;
    PORT
      LAYER met3 ;
        RECT 615.445 925.890 615.745 926.190 ;
    END
  END pixRst_TOP<27>
  PIN pixRst_TOP<28>
    ANTENNAGATEAREA 4.032000 ;
    PORT
      LAYER met3 ;
        RECT 617.350 925.890 617.650 926.190 ;
    END
  END pixRst_TOP<28>
  PIN pixRst_TOP<29>
    ANTENNAGATEAREA 4.032000 ;
    PORT
      LAYER met3 ;
        RECT 639.445 925.890 639.745 926.190 ;
    END
  END pixRst_TOP<29>
  PIN pixRst_TOP<30>
    ANTENNAGATEAREA 4.032000 ;
    PORT
      LAYER met3 ;
        RECT 641.350 925.890 641.650 926.190 ;
    END
  END pixRst_TOP<30>
  PIN pixRst_TOP<31>
    ANTENNAGATEAREA 4.032000 ;
    PORT
      LAYER met3 ;
        RECT 663.445 925.890 663.745 926.190 ;
    END
  END pixRst_TOP<31>
  PIN pixRst_TOP<32>
    ANTENNAGATEAREA 4.032000 ;
    PORT
      LAYER met3 ;
        RECT 665.350 925.890 665.650 926.190 ;
    END
  END pixRst_TOP<32>
  PIN pixRst_TOP<33>
    ANTENNAGATEAREA 4.032000 ;
    PORT
      LAYER met3 ;
        RECT 687.445 925.890 687.745 926.190 ;
    END
  END pixRst_TOP<33>
  PIN pixRst_TOP<34>
    ANTENNAGATEAREA 4.032000 ;
    PORT
      LAYER met3 ;
        RECT 689.350 925.890 689.650 926.190 ;
    END
  END pixRst_TOP<34>
  PIN pixRst_TOP<35>
    ANTENNAGATEAREA 4.032000 ;
    PORT
      LAYER met3 ;
        RECT 711.445 925.890 711.745 926.190 ;
    END
  END pixRst_TOP<35>
  PIN pixRst_TOP<36>
    ANTENNAGATEAREA 4.032000 ;
    PORT
      LAYER met3 ;
        RECT 713.350 925.890 713.650 926.190 ;
    END
  END pixRst_TOP<36>
  PIN pixRst_TOP<37>
    ANTENNAGATEAREA 4.032000 ;
    PORT
      LAYER met3 ;
        RECT 735.445 925.890 735.745 926.190 ;
    END
  END pixRst_TOP<37>
  PIN pixRst_TOP<38>
    ANTENNAGATEAREA 4.032000 ;
    PORT
      LAYER met3 ;
        RECT 737.350 925.890 737.650 926.190 ;
    END
  END pixRst_TOP<38>
  PIN pixRst_TOP<39>
    ANTENNAGATEAREA 4.032000 ;
    PORT
      LAYER met3 ;
        RECT 759.445 925.890 759.745 926.190 ;
    END
  END pixRst_TOP<39>
  PIN pixRst_TOP<40>
    ANTENNAGATEAREA 4.032000 ;
    PORT
      LAYER met3 ;
        RECT 761.350 925.890 761.650 926.190 ;
    END
  END pixRst_TOP<40>
  PIN pixRst_TOP<41>
    ANTENNAGATEAREA 4.032000 ;
    PORT
      LAYER met3 ;
        RECT 783.445 925.890 783.745 926.190 ;
    END
  END pixRst_TOP<41>
  PIN pixRst_TOP<42>
    ANTENNAGATEAREA 4.032000 ;
    PORT
      LAYER met3 ;
        RECT 785.350 925.890 785.650 926.190 ;
    END
  END pixRst_TOP<42>
  PIN pixRst_TOP<43>
    ANTENNAGATEAREA 4.032000 ;
    PORT
      LAYER met3 ;
        RECT 807.445 925.890 807.745 926.190 ;
    END
  END pixRst_TOP<43>
  PIN pixRst_TOP<44>
    ANTENNAGATEAREA 4.032000 ;
    PORT
      LAYER met3 ;
        RECT 809.350 925.890 809.650 926.190 ;
    END
  END pixRst_TOP<44>
  PIN pixRst_TOP<45>
    ANTENNAGATEAREA 4.032000 ;
    PORT
      LAYER met3 ;
        RECT 831.445 925.890 831.745 926.190 ;
    END
  END pixRst_TOP<45>
  PIN pixRst_TOP<46>
    ANTENNAGATEAREA 4.032000 ;
    PORT
      LAYER met3 ;
        RECT 833.350 925.890 833.650 926.190 ;
    END
  END pixRst_TOP<46>
  PIN pixRst_TOP<47>
    ANTENNAGATEAREA 4.032000 ;
    PORT
      LAYER met3 ;
        RECT 855.445 925.890 855.745 926.190 ;
    END
  END pixRst_TOP<47>
  PIN pixRst_TOP<48>
    ANTENNAGATEAREA 4.032000 ;
    PORT
      LAYER met3 ;
        RECT 857.350 925.890 857.650 926.190 ;
    END
  END pixRst_TOP<48>
  PIN pixRst_TOP<49>
    ANTENNAGATEAREA 4.032000 ;
    PORT
      LAYER met3 ;
        RECT 879.445 925.890 879.745 926.190 ;
    END
  END pixRst_TOP<49>
  PIN pixRst_TOP<50>
    ANTENNAGATEAREA 4.032000 ;
    PORT
      LAYER met3 ;
        RECT 881.350 925.890 881.650 926.190 ;
    END
  END pixRst_TOP<50>
  PIN pixRst_TOP<51>
    ANTENNAGATEAREA 4.032000 ;
    PORT
      LAYER met3 ;
        RECT 903.445 925.890 903.745 926.190 ;
    END
  END pixRst_TOP<51>
  PIN pixRst_TOP<52>
    ANTENNAGATEAREA 4.032000 ;
    PORT
      LAYER met3 ;
        RECT 905.350 925.890 905.650 926.190 ;
    END
  END pixRst_TOP<52>
  PIN pixRst_TOP<53>
    ANTENNAGATEAREA 4.032000 ;
    PORT
      LAYER met3 ;
        RECT 927.445 925.890 927.745 926.190 ;
    END
  END pixRst_TOP<53>
  PIN pixRst_TOP<54>
    ANTENNAGATEAREA 4.032000 ;
    PORT
      LAYER met3 ;
        RECT 929.350 925.890 929.650 926.190 ;
    END
  END pixRst_TOP<54>
  PIN pixRst_TOP<55>
    ANTENNAGATEAREA 4.032000 ;
    PORT
      LAYER met3 ;
        RECT 951.445 925.890 951.745 926.190 ;
    END
  END pixRst_TOP<55>
  PIN pixRst_TOP<56>
    ANTENNAGATEAREA 4.032000 ;
    PORT
      LAYER met3 ;
        RECT 953.350 925.890 953.650 926.190 ;
    END
  END pixRst_TOP<56>
  PIN pixRst_TOP<57>
    ANTENNAGATEAREA 4.032000 ;
    PORT
      LAYER met3 ;
        RECT 975.445 925.890 975.745 926.190 ;
    END
  END pixRst_TOP<57>
  PIN pixRst_TOP<58>
    ANTENNAGATEAREA 4.032000 ;
    PORT
      LAYER met3 ;
        RECT 977.350 925.890 977.650 926.190 ;
    END
  END pixRst_TOP<58>
  PIN pixRst_TOP<59>
    ANTENNAGATEAREA 4.032000 ;
    PORT
      LAYER met3 ;
        RECT 999.445 925.890 999.745 926.190 ;
    END
  END pixRst_TOP<59>
  PIN pixRst_TOP<60>
    ANTENNAGATEAREA 4.032000 ;
    PORT
      LAYER met3 ;
        RECT 1001.350 925.890 1001.650 926.190 ;
    END
  END pixRst_TOP<60>
  PIN pixRst_TOP<61>
    ANTENNAGATEAREA 4.032000 ;
    PORT
      LAYER met3 ;
        RECT 1023.445 925.890 1023.745 926.190 ;
    END
  END pixRst_TOP<61>
  PIN pixRst_TOP<62>
    ANTENNAGATEAREA 4.032000 ;
    PORT
      LAYER met3 ;
        RECT 1025.350 925.890 1025.650 926.190 ;
    END
  END pixRst_TOP<62>
  PIN pixRst_TOP<63>
    ANTENNAGATEAREA 4.032000 ;
    PORT
      LAYER met3 ;
        RECT 1047.445 925.890 1047.745 926.190 ;
    END
  END pixRst_TOP<63>
  PIN pixRst_TOP<64>
    ANTENNAGATEAREA 4.032000 ;
    PORT
      LAYER met3 ;
        RECT 1049.350 925.890 1049.650 926.190 ;
    END
  END pixRst_TOP<64>
  PIN pixRst_TOP<65>
    ANTENNAGATEAREA 4.032000 ;
    PORT
      LAYER met3 ;
        RECT 1071.445 925.890 1071.745 926.190 ;
    END
  END pixRst_TOP<65>
  PIN pixRst_TOP<66>
    ANTENNAGATEAREA 4.032000 ;
    PORT
      LAYER met3 ;
        RECT 1073.350 925.890 1073.650 926.190 ;
    END
  END pixRst_TOP<66>
  PIN pixRst_TOP<67>
    ANTENNAGATEAREA 4.032000 ;
    PORT
      LAYER met3 ;
        RECT 1095.445 925.890 1095.745 926.190 ;
    END
  END pixRst_TOP<67>
  PIN pixRst_TOP<68>
    ANTENNAGATEAREA 4.032000 ;
    PORT
      LAYER met3 ;
        RECT 1097.350 925.890 1097.650 926.190 ;
    END
  END pixRst_TOP<68>
  PIN pixRst_TOP<69>
    ANTENNAGATEAREA 4.032000 ;
    PORT
      LAYER met3 ;
        RECT 1119.445 925.890 1119.745 926.190 ;
    END
  END pixRst_TOP<69>
  PIN pixRst_TOP<70>
    ANTENNAGATEAREA 4.032000 ;
    PORT
      LAYER met3 ;
        RECT 1121.350 925.890 1121.650 926.190 ;
    END
  END pixRst_TOP<70>
  PIN pixRst_TOP<71>
    ANTENNAGATEAREA 4.032000 ;
    PORT
      LAYER met3 ;
        RECT 1143.445 925.890 1143.745 926.190 ;
    END
  END pixRst_TOP<71>
  PIN pixRst_TOP<72>
    ANTENNAGATEAREA 4.032000 ;
    PORT
      LAYER met3 ;
        RECT 1145.350 925.890 1145.650 926.190 ;
    END
  END pixRst_TOP<72>
  PIN pixRst_TOP<73>
    ANTENNAGATEAREA 4.032000 ;
    PORT
      LAYER met3 ;
        RECT 1167.445 925.890 1167.745 926.190 ;
    END
  END pixRst_TOP<73>
  PIN pixRst_TOP<74>
    ANTENNAGATEAREA 4.032000 ;
    PORT
      LAYER met3 ;
        RECT 1169.350 925.890 1169.650 926.190 ;
    END
  END pixRst_TOP<74>
  PIN pixRst_TOP<75>
    ANTENNAGATEAREA 4.032000 ;
    PORT
      LAYER met3 ;
        RECT 1191.445 925.890 1191.745 926.190 ;
    END
  END pixRst_TOP<75>
  PIN pixRst_TOP<76>
    ANTENNAGATEAREA 4.032000 ;
    PORT
      LAYER met3 ;
        RECT 1193.350 925.890 1193.650 926.190 ;
    END
  END pixRst_TOP<76>
  PIN pixRst_TOP<77>
    ANTENNAGATEAREA 4.032000 ;
    PORT
      LAYER met3 ;
        RECT 1215.445 925.890 1215.745 926.190 ;
    END
  END pixRst_TOP<77>
  PIN pixRst_TOP<78>
    ANTENNAGATEAREA 4.032000 ;
    PORT
      LAYER met3 ;
        RECT 1217.350 925.890 1217.650 926.190 ;
    END
  END pixRst_TOP<78>
  PIN pixRst_TOP<79>
    ANTENNAGATEAREA 4.032000 ;
    PORT
      LAYER met3 ;
        RECT 1239.445 925.890 1239.745 926.190 ;
    END
  END pixRst_TOP<79>
  PIN pixRst_TOP<80>
    ANTENNAGATEAREA 4.032000 ;
    PORT
      LAYER met3 ;
        RECT 1241.350 925.890 1241.650 926.190 ;
    END
  END pixRst_TOP<80>
  PIN pixRst_TOP<81>
    ANTENNAGATEAREA 4.032000 ;
    PORT
      LAYER met3 ;
        RECT 1263.445 925.890 1263.745 926.190 ;
    END
  END pixRst_TOP<81>
  PIN pixRst_TOP<82>
    ANTENNAGATEAREA 4.032000 ;
    PORT
      LAYER met3 ;
        RECT 1265.350 925.890 1265.650 926.190 ;
    END
  END pixRst_TOP<82>
  PIN pixRst_TOP<83>
    ANTENNAGATEAREA 4.032000 ;
    PORT
      LAYER met3 ;
        RECT 1287.445 925.890 1287.745 926.190 ;
    END
  END pixRst_TOP<83>
  PIN pixRst_TOP<84>
    ANTENNAGATEAREA 4.032000 ;
    PORT
      LAYER met3 ;
        RECT 1289.350 925.890 1289.650 926.190 ;
    END
  END pixRst_TOP<84>
  PIN pixRst_TOP<85>
    ANTENNAGATEAREA 4.032000 ;
    PORT
      LAYER met3 ;
        RECT 1311.445 925.890 1311.745 926.190 ;
    END
  END pixRst_TOP<85>
  PIN pixRst_TOP<86>
    ANTENNAGATEAREA 4.032000 ;
    PORT
      LAYER met3 ;
        RECT 1313.350 925.890 1313.650 926.190 ;
    END
  END pixRst_TOP<86>
  PIN pixRst_TOP<87>
    ANTENNAGATEAREA 4.032000 ;
    PORT
      LAYER met3 ;
        RECT 1335.445 925.890 1335.745 926.190 ;
    END
  END pixRst_TOP<87>
  PIN pixRst_TOP<88>
    ANTENNAGATEAREA 4.032000 ;
    PORT
      LAYER met3 ;
        RECT 1337.350 925.890 1337.650 926.190 ;
    END
  END pixRst_TOP<88>
  PIN pixRst_TOP<89>
    ANTENNAGATEAREA 4.032000 ;
    PORT
      LAYER met3 ;
        RECT 1359.445 925.890 1359.745 926.190 ;
    END
  END pixRst_TOP<89>
  PIN pixRst_TOP<90>
    ANTENNAGATEAREA 4.032000 ;
    PORT
      LAYER met3 ;
        RECT 1361.350 925.890 1361.650 926.190 ;
    END
  END pixRst_TOP<90>
  PIN pixRst_TOP<91>
    ANTENNAGATEAREA 4.032000 ;
    PORT
      LAYER met3 ;
        RECT 1383.445 925.890 1383.745 926.190 ;
    END
  END pixRst_TOP<91>
  PIN pixRst_TOP<92>
    ANTENNAGATEAREA 4.032000 ;
    PORT
      LAYER met3 ;
        RECT 1385.350 925.890 1385.650 926.190 ;
    END
  END pixRst_TOP<92>
  PIN pixRst_TOP<93>
    ANTENNAGATEAREA 4.032000 ;
    PORT
      LAYER met3 ;
        RECT 1407.445 925.890 1407.745 926.190 ;
    END
  END pixRst_TOP<93>
  PIN pixRst_TOP<94>
    ANTENNAGATEAREA 4.032000 ;
    PORT
      LAYER met3 ;
        RECT 1409.350 925.890 1409.650 926.190 ;
    END
  END pixRst_TOP<94>
  PIN pixRst_TOP<95>
    ANTENNAGATEAREA 4.032000 ;
    PORT
      LAYER met3 ;
        RECT 1431.445 925.890 1431.745 926.190 ;
    END
  END pixRst_TOP<95>
  PIN pixRst_TOP<96>
    ANTENNAGATEAREA 4.032000 ;
    PORT
      LAYER met3 ;
        RECT 1433.350 925.890 1433.650 926.190 ;
    END
  END pixRst_TOP<96>
  PIN pixRst_TOP<97>
    ANTENNAGATEAREA 4.032000 ;
    PORT
      LAYER met3 ;
        RECT 1455.445 925.890 1455.745 926.190 ;
    END
  END pixRst_TOP<97>
  PIN pixRst_TOP<98>
    ANTENNAGATEAREA 4.032000 ;
    PORT
      LAYER met3 ;
        RECT 1457.350 925.890 1457.650 926.190 ;
    END
  END pixRst_TOP<98>
  PIN pixRst_TOP<99>
    ANTENNAGATEAREA 4.032000 ;
    PORT
      LAYER met3 ;
        RECT 1479.445 925.890 1479.745 926.190 ;
    END
  END pixRst_TOP<99>
  PIN pixRst_TOP<100>
    ANTENNAGATEAREA 4.032000 ;
    PORT
      LAYER met3 ;
        RECT 1481.350 925.890 1481.650 926.190 ;
    END
  END pixRst_TOP<100>
  PIN pixRst_TOP<101>
    ANTENNAGATEAREA 4.032000 ;
    PORT
      LAYER met3 ;
        RECT 1503.445 925.890 1503.745 926.190 ;
    END
  END pixRst_TOP<101>
  PIN pixRst_TOP<102>
    ANTENNAGATEAREA 4.032000 ;
    PORT
      LAYER met3 ;
        RECT 1505.350 925.890 1505.650 926.190 ;
    END
  END pixRst_TOP<102>
  PIN pixRst_TOP<103>
    ANTENNAGATEAREA 4.032000 ;
    PORT
      LAYER met3 ;
        RECT 1527.445 925.890 1527.745 926.190 ;
    END
  END pixRst_TOP<103>
  PIN pixRst_TOP<104>
    ANTENNAGATEAREA 4.032000 ;
    PORT
      LAYER met3 ;
        RECT 1529.350 925.890 1529.650 926.190 ;
    END
  END pixRst_TOP<104>
  PIN pixRst_TOP<105>
    ANTENNAGATEAREA 4.032000 ;
    PORT
      LAYER met3 ;
        RECT 1551.445 925.890 1551.745 926.190 ;
    END
  END pixRst_TOP<105>
  PIN pixRst_TOP<106>
    ANTENNAGATEAREA 4.032000 ;
    PORT
      LAYER met3 ;
        RECT 1553.350 925.890 1553.650 926.190 ;
    END
  END pixRst_TOP<106>
  PIN pixRst_TOP<107>
    ANTENNAGATEAREA 4.032000 ;
    PORT
      LAYER met3 ;
        RECT 1575.445 925.890 1575.745 926.190 ;
    END
  END pixRst_TOP<107>
  PIN pixRst_TOP<108>
    ANTENNAGATEAREA 4.032000 ;
    PORT
      LAYER met3 ;
        RECT 1577.350 925.890 1577.650 926.190 ;
    END
  END pixRst_TOP<108>
  PIN pixRst_TOP<109>
    ANTENNAGATEAREA 4.032000 ;
    PORT
      LAYER met3 ;
        RECT 1599.445 925.890 1599.745 926.190 ;
    END
  END pixRst_TOP<109>
  PIN pixRst_TOP<110>
    ANTENNAGATEAREA 4.032000 ;
    PORT
      LAYER met3 ;
        RECT 1601.350 925.890 1601.650 926.190 ;
    END
  END pixRst_TOP<110>
  PIN pixRst_TOP<111>
    ANTENNAGATEAREA 4.032000 ;
    PORT
      LAYER met3 ;
        RECT 1623.445 925.890 1623.745 926.190 ;
    END
  END pixRst_TOP<111>
  PIN pixRst_TOP<112>
    ANTENNAGATEAREA 4.032000 ;
    PORT
      LAYER met3 ;
        RECT 1625.350 925.890 1625.650 926.190 ;
    END
  END pixRst_TOP<112>
  PIN pixRst_TOP<113>
    ANTENNAGATEAREA 4.032000 ;
    PORT
      LAYER met3 ;
        RECT 1647.445 925.890 1647.745 926.190 ;
    END
  END pixRst_TOP<113>
  PIN pixRst_TOP<114>
    ANTENNAGATEAREA 4.032000 ;
    PORT
      LAYER met3 ;
        RECT 1649.350 925.890 1649.650 926.190 ;
    END
  END pixRst_TOP<114>
  PIN pixRst_TOP<115>
    ANTENNAGATEAREA 4.032000 ;
    PORT
      LAYER met3 ;
        RECT 1671.445 925.890 1671.745 926.190 ;
    END
  END pixRst_TOP<115>
  PIN pixRst_TOP<116>
    ANTENNAGATEAREA 4.032000 ;
    PORT
      LAYER met3 ;
        RECT 1673.350 925.890 1673.650 926.190 ;
    END
  END pixRst_TOP<116>
  PIN pixRst_TOP<117>
    ANTENNAGATEAREA 4.032000 ;
    PORT
      LAYER met3 ;
        RECT 1695.445 925.890 1695.745 926.190 ;
    END
  END pixRst_TOP<117>
  PIN pixRst_TOP<118>
    ANTENNAGATEAREA 4.032000 ;
    PORT
      LAYER met3 ;
        RECT 1697.350 925.890 1697.650 926.190 ;
    END
  END pixRst_TOP<118>
  PIN pixRst_TOP<119>
    ANTENNAGATEAREA 4.032000 ;
    PORT
      LAYER met3 ;
        RECT 1719.445 925.890 1719.745 926.190 ;
    END
  END pixRst_TOP<119>
  PIN pixRst_TOP<120>
    ANTENNAGATEAREA 4.032000 ;
    PORT
      LAYER met3 ;
        RECT 1721.350 925.890 1721.650 926.190 ;
    END
  END pixRst_TOP<120>
  PIN pixRst_TOP<121>
    ANTENNAGATEAREA 4.032000 ;
    PORT
      LAYER met3 ;
        RECT 1743.445 925.890 1743.745 926.190 ;
    END
  END pixRst_TOP<121>
  PIN pixRst_TOP<122>
    ANTENNAGATEAREA 4.032000 ;
    PORT
      LAYER met3 ;
        RECT 1745.350 925.890 1745.650 926.190 ;
    END
  END pixRst_TOP<122>
  PIN pixRst_TOP<123>
    ANTENNAGATEAREA 4.032000 ;
    PORT
      LAYER met3 ;
        RECT 1767.445 925.890 1767.745 926.190 ;
    END
  END pixRst_TOP<123>
  PIN pixRst_TOP<124>
    ANTENNAGATEAREA 4.032000 ;
    PORT
      LAYER met3 ;
        RECT 1769.350 925.890 1769.650 926.190 ;
    END
  END pixRst_TOP<124>
  PIN pixRst_TOP<125>
    ANTENNAGATEAREA 4.032000 ;
    PORT
      LAYER met3 ;
        RECT 1791.445 925.890 1791.745 926.190 ;
    END
  END pixRst_TOP<125>
  PIN pixRst_TOP<126>
    ANTENNAGATEAREA 4.032000 ;
    PORT
      LAYER met3 ;
        RECT 1793.350 925.890 1793.650 926.190 ;
    END
  END pixRst_TOP<126>
  PIN pixRst_TOP<127>
    ANTENNAGATEAREA 4.032000 ;
    PORT
      LAYER met3 ;
        RECT 1815.445 925.890 1815.745 926.190 ;
    END
  END pixRst_TOP<127>
  PIN rowReadOFF_TOP<0>
    ANTENNAGATEAREA 8.064000 ;
    PORT
      LAYER met3 ;
        RECT 279.055 867.125 279.385 867.455 ;
    END
  END rowReadOFF_TOP<0>
  PIN rowReadOFF_TOP<1>
    ANTENNAGATEAREA 8.064000 ;
    PORT
      LAYER met3 ;
        RECT 279.055 864.315 279.385 864.645 ;
    END
  END rowReadOFF_TOP<1>
  PIN rowReadOFF_TOP<2>
    ANTENNAGATEAREA 8.064000 ;
    PORT
      LAYER met3 ;
        RECT 279.055 843.125 279.385 843.455 ;
    END
  END rowReadOFF_TOP<2>
  PIN rowReadOFF_TOP<3>
    ANTENNAGATEAREA 8.064000 ;
    PORT
      LAYER met3 ;
        RECT 279.055 840.315 279.385 840.645 ;
    END
  END rowReadOFF_TOP<3>
  PIN rowReadOFF_TOP<4>
    ANTENNAGATEAREA 8.064000 ;
    PORT
      LAYER met3 ;
        RECT 279.055 819.125 279.385 819.455 ;
    END
  END rowReadOFF_TOP<4>
  PIN rowReadOFF_TOP<5>
    ANTENNAGATEAREA 8.064000 ;
    PORT
      LAYER met3 ;
        RECT 279.055 816.315 279.385 816.645 ;
    END
  END rowReadOFF_TOP<5>
  PIN rowReadOFF_TOP<6>
    ANTENNAGATEAREA 8.064000 ;
    PORT
      LAYER met3 ;
        RECT 279.055 795.125 279.385 795.455 ;
    END
  END rowReadOFF_TOP<6>
  PIN rowReadOFF_TOP<7>
    ANTENNAGATEAREA 8.064000 ;
    PORT
      LAYER met3 ;
        RECT 279.055 792.315 279.385 792.645 ;
    END
  END rowReadOFF_TOP<7>
  PIN rowReadOFF_TOP<8>
    ANTENNAGATEAREA 8.064000 ;
    PORT
      LAYER met3 ;
        RECT 279.055 771.125 279.385 771.455 ;
    END
  END rowReadOFF_TOP<8>
  PIN rowReadOFF_TOP<9>
    ANTENNAGATEAREA 8.064000 ;
    PORT
      LAYER met3 ;
        RECT 279.055 768.315 279.385 768.645 ;
    END
  END rowReadOFF_TOP<9>
  PIN rowReadOFF_TOP<10>
    ANTENNAGATEAREA 8.064000 ;
    PORT
      LAYER met3 ;
        RECT 279.055 747.125 279.385 747.455 ;
    END
  END rowReadOFF_TOP<10>
  PIN rowReadOFF_TOP<11>
    ANTENNAGATEAREA 8.064000 ;
    PORT
      LAYER met3 ;
        RECT 279.055 744.315 279.385 744.645 ;
    END
  END rowReadOFF_TOP<11>
  PIN rowReadOFF_TOP<12>
    ANTENNAGATEAREA 8.064000 ;
    PORT
      LAYER met3 ;
        RECT 279.055 723.125 279.385 723.455 ;
    END
  END rowReadOFF_TOP<12>
  PIN rowReadOFF_TOP<13>
    ANTENNAGATEAREA 8.064000 ;
    PORT
      LAYER met3 ;
        RECT 279.055 720.315 279.385 720.645 ;
    END
  END rowReadOFF_TOP<13>
  PIN rowReadOFF_TOP<14>
    ANTENNAGATEAREA 8.064000 ;
    PORT
      LAYER met3 ;
        RECT 279.055 699.125 279.385 699.455 ;
    END
  END rowReadOFF_TOP<14>
  PIN rowReadOFF_TOP<15>
    ANTENNAGATEAREA 8.064000 ;
    PORT
      LAYER met3 ;
        RECT 279.055 696.315 279.385 696.645 ;
    END
  END rowReadOFF_TOP<15>
  PIN rowReadOFF_TOP<16>
    ANTENNAGATEAREA 8.064000 ;
    PORT
      LAYER met3 ;
        RECT 279.055 675.125 279.385 675.455 ;
    END
  END rowReadOFF_TOP<16>
  PIN rowReadOFF_TOP<17>
    ANTENNAGATEAREA 8.064000 ;
    PORT
      LAYER met3 ;
        RECT 279.055 672.315 279.385 672.645 ;
    END
  END rowReadOFF_TOP<17>
  PIN rowReadOFF_TOP<18>
    ANTENNAGATEAREA 8.064000 ;
    PORT
      LAYER met3 ;
        RECT 279.055 651.125 279.385 651.455 ;
    END
  END rowReadOFF_TOP<18>
  PIN rowReadOFF_TOP<19>
    ANTENNAGATEAREA 8.064000 ;
    PORT
      LAYER met3 ;
        RECT 279.055 648.315 279.385 648.645 ;
    END
  END rowReadOFF_TOP<19>
  PIN rowReadOFF_TOP<20>
    ANTENNAGATEAREA 8.064000 ;
    PORT
      LAYER met3 ;
        RECT 279.055 627.125 279.385 627.455 ;
    END
  END rowReadOFF_TOP<20>
  PIN rowReadOFF_TOP<21>
    ANTENNAGATEAREA 8.064000 ;
    PORT
      LAYER met3 ;
        RECT 279.055 624.315 279.385 624.645 ;
    END
  END rowReadOFF_TOP<21>
  PIN rowReadOFF_TOP<22>
    ANTENNAGATEAREA 8.064000 ;
    PORT
      LAYER met3 ;
        RECT 279.055 603.125 279.385 603.455 ;
    END
  END rowReadOFF_TOP<22>
  PIN rowReadOFF_TOP<23>
    ANTENNAGATEAREA 8.064000 ;
    PORT
      LAYER met3 ;
        RECT 279.055 600.315 279.385 600.645 ;
    END
  END rowReadOFF_TOP<23>
  PIN rowReadOFF_TOP<24>
    ANTENNAGATEAREA 8.064000 ;
    PORT
      LAYER met3 ;
        RECT 279.055 579.125 279.385 579.455 ;
    END
  END rowReadOFF_TOP<24>
  PIN rowReadOFF_TOP<25>
    ANTENNAGATEAREA 8.064000 ;
    PORT
      LAYER met3 ;
        RECT 279.055 576.315 279.385 576.645 ;
    END
  END rowReadOFF_TOP<25>
  PIN rowReadOFF_TOP<26>
    ANTENNAGATEAREA 8.064000 ;
    PORT
      LAYER met3 ;
        RECT 279.055 555.125 279.385 555.455 ;
    END
  END rowReadOFF_TOP<26>
  PIN rowReadOFF_TOP<27>
    ANTENNAGATEAREA 8.064000 ;
    PORT
      LAYER met3 ;
        RECT 279.055 552.315 279.385 552.645 ;
    END
  END rowReadOFF_TOP<27>
  PIN rowReadOFF_TOP<28>
    ANTENNAGATEAREA 8.064000 ;
    PORT
      LAYER met3 ;
        RECT 279.055 531.125 279.385 531.455 ;
    END
  END rowReadOFF_TOP<28>
  PIN rowReadOFF_TOP<29>
    ANTENNAGATEAREA 8.064000 ;
    PORT
      LAYER met3 ;
        RECT 279.055 528.315 279.385 528.645 ;
    END
  END rowReadOFF_TOP<29>
  PIN rowReadOFF_TOP<30>
    ANTENNAGATEAREA 8.064000 ;
    PORT
      LAYER met3 ;
        RECT 279.055 507.125 279.385 507.455 ;
    END
  END rowReadOFF_TOP<30>
  PIN rowReadOFF_TOP<31>
    ANTENNAGATEAREA 8.064000 ;
    PORT
      LAYER met3 ;
        RECT 279.055 504.315 279.385 504.645 ;
    END
  END rowReadOFF_TOP<31>
  PIN rowReadOFF_TOP<32>
    ANTENNAGATEAREA 8.064000 ;
    PORT
      LAYER met3 ;
        RECT 279.055 483.125 279.385 483.455 ;
    END
  END rowReadOFF_TOP<32>
  PIN rowReadOFF_TOP<33>
    ANTENNAGATEAREA 8.064000 ;
    PORT
      LAYER met3 ;
        RECT 279.055 480.315 279.385 480.645 ;
    END
  END rowReadOFF_TOP<33>
  PIN rowReadOFF_TOP<34>
    ANTENNAGATEAREA 8.064000 ;
    PORT
      LAYER met3 ;
        RECT 279.055 459.125 279.385 459.455 ;
    END
  END rowReadOFF_TOP<34>
  PIN rowReadOFF_TOP<35>
    ANTENNAGATEAREA 8.064000 ;
    PORT
      LAYER met3 ;
        RECT 279.055 456.315 279.385 456.645 ;
    END
  END rowReadOFF_TOP<35>
  PIN rowReadOFF_TOP<36>
    ANTENNAGATEAREA 8.064000 ;
    PORT
      LAYER met3 ;
        RECT 279.055 435.125 279.385 435.455 ;
    END
  END rowReadOFF_TOP<36>
  PIN rowReadOFF_TOP<37>
    ANTENNAGATEAREA 8.064000 ;
    PORT
      LAYER met3 ;
        RECT 279.055 432.315 279.385 432.645 ;
    END
  END rowReadOFF_TOP<37>
  PIN rowReadOFF_TOP<38>
    ANTENNAGATEAREA 8.064000 ;
    PORT
      LAYER met3 ;
        RECT 279.055 411.125 279.385 411.455 ;
    END
  END rowReadOFF_TOP<38>
  PIN rowReadOFF_TOP<39>
    ANTENNAGATEAREA 8.064000 ;
    PORT
      LAYER met3 ;
        RECT 279.055 408.315 279.385 408.645 ;
    END
  END rowReadOFF_TOP<39>
  PIN rowReadOFF_TOP<40>
    ANTENNAGATEAREA 8.064000 ;
    PORT
      LAYER met3 ;
        RECT 279.055 387.125 279.385 387.455 ;
    END
  END rowReadOFF_TOP<40>
  PIN rowReadOFF_TOP<41>
    ANTENNAGATEAREA 8.064000 ;
    PORT
      LAYER met3 ;
        RECT 279.055 384.315 279.385 384.645 ;
    END
  END rowReadOFF_TOP<41>
  PIN rowReadOFF_TOP<42>
    ANTENNAGATEAREA 8.064000 ;
    PORT
      LAYER met3 ;
        RECT 279.055 363.125 279.385 363.455 ;
    END
  END rowReadOFF_TOP<42>
  PIN rowReadOFF_TOP<43>
    ANTENNAGATEAREA 8.064000 ;
    PORT
      LAYER met3 ;
        RECT 279.055 360.315 279.385 360.645 ;
    END
  END rowReadOFF_TOP<43>
  PIN rowReadOFF_TOP<44>
    ANTENNAGATEAREA 8.064000 ;
    PORT
      LAYER met3 ;
        RECT 279.055 339.125 279.385 339.455 ;
    END
  END rowReadOFF_TOP<44>
  PIN rowReadOFF_TOP<45>
    ANTENNAGATEAREA 8.064000 ;
    PORT
      LAYER met3 ;
        RECT 279.055 336.315 279.385 336.645 ;
    END
  END rowReadOFF_TOP<45>
  PIN rowReadOFF_TOP<46>
    ANTENNAGATEAREA 8.064000 ;
    PORT
      LAYER met3 ;
        RECT 279.055 315.125 279.385 315.455 ;
    END
  END rowReadOFF_TOP<46>
  PIN rowReadOFF_TOP<47>
    ANTENNAGATEAREA 8.064000 ;
    PORT
      LAYER met3 ;
        RECT 279.055 312.315 279.385 312.645 ;
    END
  END rowReadOFF_TOP<47>
  PIN rowReadOFF_TOP<48>
    ANTENNAGATEAREA 8.064000 ;
    PORT
      LAYER met3 ;
        RECT 279.055 291.125 279.385 291.455 ;
    END
  END rowReadOFF_TOP<48>
  PIN rowReadOFF_TOP<49>
    ANTENNAGATEAREA 8.064000 ;
    PORT
      LAYER met3 ;
        RECT 279.055 288.315 279.385 288.645 ;
    END
  END rowReadOFF_TOP<49>
  PIN rowReadOFF_TOP<50>
    ANTENNAGATEAREA 8.064000 ;
    PORT
      LAYER met3 ;
        RECT 279.055 267.125 279.385 267.455 ;
    END
  END rowReadOFF_TOP<50>
  PIN rowReadOFF_TOP<51>
    ANTENNAGATEAREA 8.064000 ;
    PORT
      LAYER met3 ;
        RECT 279.055 264.315 279.385 264.645 ;
    END
  END rowReadOFF_TOP<51>
  PIN rowReadOFF_TOP<52>
    ANTENNAGATEAREA 8.064000 ;
    PORT
      LAYER met3 ;
        RECT 279.055 243.125 279.385 243.455 ;
    END
  END rowReadOFF_TOP<52>
  PIN rowReadOFF_TOP<53>
    ANTENNAGATEAREA 8.064000 ;
    PORT
      LAYER met3 ;
        RECT 279.055 240.315 279.385 240.645 ;
    END
  END rowReadOFF_TOP<53>
  PIN rowReadOFF_TOP<54>
    ANTENNAGATEAREA 8.064000 ;
    PORT
      LAYER met3 ;
        RECT 279.055 219.125 279.385 219.455 ;
    END
  END rowReadOFF_TOP<54>
  PIN rowReadOFF_TOP<55>
    ANTENNAGATEAREA 8.064000 ;
    PORT
      LAYER met3 ;
        RECT 279.055 216.315 279.385 216.645 ;
    END
  END rowReadOFF_TOP<55>
  PIN rowReadOFF_TOP<56>
    ANTENNAGATEAREA 8.064000 ;
    PORT
      LAYER met3 ;
        RECT 279.055 195.125 279.385 195.455 ;
    END
  END rowReadOFF_TOP<56>
  PIN rowReadOFF_TOP<57>
    ANTENNAGATEAREA 8.064000 ;
    PORT
      LAYER met3 ;
        RECT 279.055 192.315 279.385 192.645 ;
    END
  END rowReadOFF_TOP<57>
  PIN rowReadOFF_TOP<58>
    ANTENNAGATEAREA 8.064000 ;
    PORT
      LAYER met3 ;
        RECT 279.055 171.125 279.385 171.455 ;
    END
  END rowReadOFF_TOP<58>
  PIN rowReadOFF_TOP<59>
    ANTENNAGATEAREA 8.064000 ;
    PORT
      LAYER met3 ;
        RECT 279.055 168.315 279.385 168.645 ;
    END
  END rowReadOFF_TOP<59>
  PIN rowReadOFF_TOP<60>
    ANTENNAGATEAREA 8.064000 ;
    PORT
      LAYER met3 ;
        RECT 279.055 147.125 279.385 147.455 ;
    END
  END rowReadOFF_TOP<60>
  PIN rowReadOFF_TOP<61>
    ANTENNAGATEAREA 8.064000 ;
    PORT
      LAYER met3 ;
        RECT 279.055 144.315 279.385 144.645 ;
    END
  END rowReadOFF_TOP<61>
  PIN rowReadOFF_TOP<62>
    ANTENNAGATEAREA 8.064000 ;
    PORT
      LAYER met3 ;
        RECT 279.055 123.125 279.385 123.455 ;
    END
  END rowReadOFF_TOP<62>
  PIN rowReadOFF_TOP<63>
    ANTENNAGATEAREA 8.064000 ;
    PORT
      LAYER met3 ;
        RECT 279.055 120.315 279.385 120.645 ;
    END
  END rowReadOFF_TOP<63>
  PIN rowReadOFF_BOT<0>
    ANTENNAGATEAREA 8.064000 ;
    PORT
      LAYER met3 ;
        RECT 279.055 -647.685 279.385 -647.355 ;
    END
  END rowReadOFF_BOT<0>
  PIN rowReadOFF_BOT<1>
    ANTENNAGATEAREA 8.064000 ;
    PORT
      LAYER met3 ;
        RECT 279.055 -644.875 279.385 -644.545 ;
    END
  END rowReadOFF_BOT<1>
  PIN rowReadOFF_BOT<2>
    ANTENNAGATEAREA 8.064000 ;
    PORT
      LAYER met3 ;
        RECT 279.055 -623.685 279.385 -623.355 ;
    END
  END rowReadOFF_BOT<2>
  PIN rowReadOFF_BOT<3>
    ANTENNAGATEAREA 8.064000 ;
    PORT
      LAYER met3 ;
        RECT 279.055 -620.875 279.385 -620.545 ;
    END
  END rowReadOFF_BOT<3>
  PIN rowReadOFF_BOT<4>
    ANTENNAGATEAREA 8.064000 ;
    PORT
      LAYER met3 ;
        RECT 279.055 -599.685 279.385 -599.355 ;
    END
  END rowReadOFF_BOT<4>
  PIN rowReadOFF_BOT<5>
    ANTENNAGATEAREA 8.064000 ;
    PORT
      LAYER met3 ;
        RECT 279.055 -596.875 279.385 -596.545 ;
    END
  END rowReadOFF_BOT<5>
  PIN rowReadOFF_BOT<6>
    ANTENNAGATEAREA 8.064000 ;
    PORT
      LAYER met3 ;
        RECT 279.055 -575.685 279.385 -575.355 ;
    END
  END rowReadOFF_BOT<6>
  PIN rowReadOFF_BOT<7>
    ANTENNAGATEAREA 8.064000 ;
    PORT
      LAYER met3 ;
        RECT 279.055 -572.875 279.385 -572.545 ;
    END
  END rowReadOFF_BOT<7>
  PIN rowReadOFF_BOT<8>
    ANTENNAGATEAREA 8.064000 ;
    PORT
      LAYER met3 ;
        RECT 279.055 -551.685 279.385 -551.355 ;
    END
  END rowReadOFF_BOT<8>
  PIN rowReadOFF_BOT<9>
    ANTENNAGATEAREA 8.064000 ;
    PORT
      LAYER met3 ;
        RECT 279.055 -548.875 279.385 -548.545 ;
    END
  END rowReadOFF_BOT<9>
  PIN rowReadOFF_BOT<10>
    ANTENNAGATEAREA 8.064000 ;
    PORT
      LAYER met3 ;
        RECT 279.055 -527.685 279.385 -527.355 ;
    END
  END rowReadOFF_BOT<10>
  PIN rowReadOFF_BOT<11>
    ANTENNAGATEAREA 8.064000 ;
    PORT
      LAYER met3 ;
        RECT 279.055 -524.875 279.385 -524.545 ;
    END
  END rowReadOFF_BOT<11>
  PIN rowReadOFF_BOT<12>
    ANTENNAGATEAREA 8.064000 ;
    PORT
      LAYER met3 ;
        RECT 279.055 -503.685 279.385 -503.355 ;
    END
  END rowReadOFF_BOT<12>
  PIN rowReadOFF_BOT<13>
    ANTENNAGATEAREA 8.064000 ;
    PORT
      LAYER met3 ;
        RECT 279.055 -500.875 279.385 -500.545 ;
    END
  END rowReadOFF_BOT<13>
  PIN rowReadOFF_BOT<14>
    ANTENNAGATEAREA 8.064000 ;
    PORT
      LAYER met3 ;
        RECT 279.055 -479.685 279.385 -479.355 ;
    END
  END rowReadOFF_BOT<14>
  PIN rowReadOFF_BOT<15>
    ANTENNAGATEAREA 8.064000 ;
    PORT
      LAYER met3 ;
        RECT 279.055 -476.875 279.385 -476.545 ;
    END
  END rowReadOFF_BOT<15>
  PIN rowReadOFF_BOT<16>
    ANTENNAGATEAREA 8.064000 ;
    PORT
      LAYER met3 ;
        RECT 279.055 -455.685 279.385 -455.355 ;
    END
  END rowReadOFF_BOT<16>
  PIN rowReadOFF_BOT<17>
    ANTENNAGATEAREA 8.064000 ;
    PORT
      LAYER met3 ;
        RECT 279.055 -452.875 279.385 -452.545 ;
    END
  END rowReadOFF_BOT<17>
  PIN rowReadOFF_BOT<18>
    ANTENNAGATEAREA 8.064000 ;
    PORT
      LAYER met3 ;
        RECT 279.055 -431.685 279.385 -431.355 ;
    END
  END rowReadOFF_BOT<18>
  PIN rowReadOFF_BOT<19>
    ANTENNAGATEAREA 8.064000 ;
    PORT
      LAYER met3 ;
        RECT 279.055 -428.875 279.385 -428.545 ;
    END
  END rowReadOFF_BOT<19>
  PIN rowReadOFF_BOT<20>
    ANTENNAGATEAREA 8.064000 ;
    PORT
      LAYER met3 ;
        RECT 279.055 -407.685 279.385 -407.355 ;
    END
  END rowReadOFF_BOT<20>
  PIN rowReadOFF_BOT<21>
    ANTENNAGATEAREA 8.064000 ;
    PORT
      LAYER met3 ;
        RECT 279.055 -404.875 279.385 -404.545 ;
    END
  END rowReadOFF_BOT<21>
  PIN rowReadOFF_BOT<22>
    ANTENNAGATEAREA 8.064000 ;
    PORT
      LAYER met3 ;
        RECT 279.055 -383.685 279.385 -383.355 ;
    END
  END rowReadOFF_BOT<22>
  PIN rowReadOFF_BOT<23>
    ANTENNAGATEAREA 8.064000 ;
    PORT
      LAYER met3 ;
        RECT 279.055 -380.875 279.385 -380.545 ;
    END
  END rowReadOFF_BOT<23>
  PIN rowReadOFF_BOT<24>
    ANTENNAGATEAREA 8.064000 ;
    PORT
      LAYER met3 ;
        RECT 279.055 -359.685 279.385 -359.355 ;
    END
  END rowReadOFF_BOT<24>
  PIN rowReadOFF_BOT<25>
    ANTENNAGATEAREA 8.064000 ;
    PORT
      LAYER met3 ;
        RECT 279.055 -356.875 279.385 -356.545 ;
    END
  END rowReadOFF_BOT<25>
  PIN rowReadOFF_BOT<26>
    ANTENNAGATEAREA 8.064000 ;
    PORT
      LAYER met3 ;
        RECT 279.055 -335.685 279.385 -335.355 ;
    END
  END rowReadOFF_BOT<26>
  PIN rowReadOFF_BOT<27>
    ANTENNAGATEAREA 8.064000 ;
    PORT
      LAYER met3 ;
        RECT 279.055 -332.875 279.385 -332.545 ;
    END
  END rowReadOFF_BOT<27>
  PIN rowReadOFF_BOT<28>
    ANTENNAGATEAREA 8.064000 ;
    PORT
      LAYER met3 ;
        RECT 279.055 -311.685 279.385 -311.355 ;
    END
  END rowReadOFF_BOT<28>
  PIN rowReadOFF_BOT<29>
    ANTENNAGATEAREA 8.064000 ;
    PORT
      LAYER met3 ;
        RECT 279.055 -308.875 279.385 -308.545 ;
    END
  END rowReadOFF_BOT<29>
  PIN rowReadOFF_BOT<30>
    ANTENNAGATEAREA 8.064000 ;
    PORT
      LAYER met3 ;
        RECT 279.055 -287.685 279.385 -287.355 ;
    END
  END rowReadOFF_BOT<30>
  PIN rowReadOFF_BOT<31>
    ANTENNAGATEAREA 8.064000 ;
    PORT
      LAYER met3 ;
        RECT 279.055 -284.875 279.385 -284.545 ;
    END
  END rowReadOFF_BOT<31>
  PIN rowReadOFF_BOT<32>
    ANTENNAGATEAREA 8.064000 ;
    PORT
      LAYER met3 ;
        RECT 279.055 -263.685 279.385 -263.355 ;
    END
  END rowReadOFF_BOT<32>
  PIN rowReadOFF_BOT<33>
    ANTENNAGATEAREA 8.064000 ;
    PORT
      LAYER met3 ;
        RECT 279.055 -260.875 279.385 -260.545 ;
    END
  END rowReadOFF_BOT<33>
  PIN rowReadOFF_BOT<34>
    ANTENNAGATEAREA 8.064000 ;
    PORT
      LAYER met3 ;
        RECT 279.055 -239.685 279.385 -239.355 ;
    END
  END rowReadOFF_BOT<34>
  PIN rowReadOFF_BOT<35>
    ANTENNAGATEAREA 8.064000 ;
    PORT
      LAYER met3 ;
        RECT 279.055 -236.875 279.385 -236.545 ;
    END
  END rowReadOFF_BOT<35>
  PIN rowReadOFF_BOT<36>
    ANTENNAGATEAREA 8.064000 ;
    PORT
      LAYER met3 ;
        RECT 279.055 -215.685 279.385 -215.355 ;
    END
  END rowReadOFF_BOT<36>
  PIN rowReadOFF_BOT<37>
    ANTENNAGATEAREA 8.064000 ;
    PORT
      LAYER met3 ;
        RECT 279.055 -212.875 279.385 -212.545 ;
    END
  END rowReadOFF_BOT<37>
  PIN rowReadOFF_BOT<38>
    ANTENNAGATEAREA 8.064000 ;
    PORT
      LAYER met3 ;
        RECT 279.055 -191.685 279.385 -191.355 ;
    END
  END rowReadOFF_BOT<38>
  PIN rowReadOFF_BOT<39>
    ANTENNAGATEAREA 8.064000 ;
    PORT
      LAYER met3 ;
        RECT 279.055 -188.875 279.385 -188.545 ;
    END
  END rowReadOFF_BOT<39>
  PIN rowReadOFF_BOT<40>
    ANTENNAGATEAREA 8.064000 ;
    PORT
      LAYER met3 ;
        RECT 279.055 -167.685 279.385 -167.355 ;
    END
  END rowReadOFF_BOT<40>
  PIN rowReadOFF_BOT<41>
    ANTENNAGATEAREA 8.064000 ;
    PORT
      LAYER met3 ;
        RECT 279.055 -164.875 279.385 -164.545 ;
    END
  END rowReadOFF_BOT<41>
  PIN rowReadOFF_BOT<42>
    ANTENNAGATEAREA 8.064000 ;
    PORT
      LAYER met3 ;
        RECT 279.055 -143.685 279.385 -143.355 ;
    END
  END rowReadOFF_BOT<42>
  PIN rowReadOFF_BOT<43>
    ANTENNAGATEAREA 8.064000 ;
    PORT
      LAYER met3 ;
        RECT 279.055 -140.875 279.385 -140.545 ;
    END
  END rowReadOFF_BOT<43>
  PIN rowReadOFF_BOT<44>
    ANTENNAGATEAREA 8.064000 ;
    PORT
      LAYER met3 ;
        RECT 279.055 -119.685 279.385 -119.355 ;
    END
  END rowReadOFF_BOT<44>
  PIN rowReadOFF_BOT<45>
    ANTENNAGATEAREA 8.064000 ;
    PORT
      LAYER met3 ;
        RECT 279.055 -116.875 279.385 -116.545 ;
    END
  END rowReadOFF_BOT<45>
  PIN rowReadOFF_BOT<46>
    ANTENNAGATEAREA 8.064000 ;
    PORT
      LAYER met3 ;
        RECT 279.055 -95.685 279.385 -95.355 ;
    END
  END rowReadOFF_BOT<46>
  PIN rowReadOFF_BOT<47>
    ANTENNAGATEAREA 8.064000 ;
    PORT
      LAYER met3 ;
        RECT 279.055 -92.875 279.385 -92.545 ;
    END
  END rowReadOFF_BOT<47>
  PIN rowReadOFF_BOT<48>
    ANTENNAGATEAREA 8.064000 ;
    PORT
      LAYER met3 ;
        RECT 279.055 -71.685 279.385 -71.355 ;
    END
  END rowReadOFF_BOT<48>
  PIN rowReadOFF_BOT<49>
    ANTENNAGATEAREA 8.064000 ;
    PORT
      LAYER met3 ;
        RECT 279.055 -68.875 279.385 -68.545 ;
    END
  END rowReadOFF_BOT<49>
  PIN rowReadOFF_BOT<50>
    ANTENNAGATEAREA 8.064000 ;
    PORT
      LAYER met3 ;
        RECT 279.055 -47.685 279.385 -47.355 ;
    END
  END rowReadOFF_BOT<50>
  PIN rowReadOFF_BOT<51>
    ANTENNAGATEAREA 8.064000 ;
    PORT
      LAYER met3 ;
        RECT 279.055 -44.875 279.385 -44.545 ;
    END
  END rowReadOFF_BOT<51>
  PIN rowReadOFF_BOT<52>
    ANTENNAGATEAREA 8.064000 ;
    PORT
      LAYER met3 ;
        RECT 279.055 -23.685 279.385 -23.355 ;
    END
  END rowReadOFF_BOT<52>
  PIN rowReadOFF_BOT<53>
    ANTENNAGATEAREA 8.064000 ;
    PORT
      LAYER met3 ;
        RECT 279.055 -20.875 279.385 -20.545 ;
    END
  END rowReadOFF_BOT<53>
  PIN rowReadOFF_BOT<54>
    ANTENNAGATEAREA 8.064000 ;
    PORT
      LAYER met3 ;
        RECT 279.055 0.315 279.385 0.645 ;
    END
  END rowReadOFF_BOT<54>
  PIN rowReadOFF_BOT<55>
    ANTENNAGATEAREA 8.064000 ;
    PORT
      LAYER met3 ;
        RECT 279.055 3.125 279.385 3.455 ;
    END
  END rowReadOFF_BOT<55>
  PIN rowReadOFF_BOT<56>
    ANTENNAGATEAREA 8.064000 ;
    PORT
      LAYER met3 ;
        RECT 279.055 24.315 279.385 24.645 ;
    END
  END rowReadOFF_BOT<56>
  PIN rowReadOFF_BOT<57>
    ANTENNAGATEAREA 8.064000 ;
    PORT
      LAYER met3 ;
        RECT 279.055 27.125 279.385 27.455 ;
    END
  END rowReadOFF_BOT<57>
  PIN rowReadOFF_BOT<58>
    ANTENNAGATEAREA 8.064000 ;
    PORT
      LAYER met3 ;
        RECT 279.055 48.315 279.385 48.645 ;
    END
  END rowReadOFF_BOT<58>
  PIN rowReadOFF_BOT<59>
    ANTENNAGATEAREA 8.064000 ;
    PORT
      LAYER met3 ;
        RECT 279.055 51.125 279.385 51.455 ;
    END
  END rowReadOFF_BOT<59>
  PIN rowReadOFF_BOT<60>
    ANTENNAGATEAREA 8.064000 ;
    PORT
      LAYER met3 ;
        RECT 279.055 72.315 279.385 72.645 ;
    END
  END rowReadOFF_BOT<60>
  PIN rowReadOFF_BOT<61>
    ANTENNAGATEAREA 8.064000 ;
    PORT
      LAYER met3 ;
        RECT 279.055 75.125 279.385 75.455 ;
    END
  END rowReadOFF_BOT<61>
  PIN rowReadOFF_BOT<62>
    ANTENNAGATEAREA 8.064000 ;
    PORT
      LAYER met3 ;
        RECT 279.055 96.315 279.385 96.645 ;
    END
  END rowReadOFF_BOT<62>
  PIN rowReadOFF_BOT<63>
    ANTENNAGATEAREA 8.064000 ;
    PORT
      LAYER met3 ;
        RECT 279.055 99.125 279.385 99.455 ;
    END
  END rowReadOFF_BOT<63>
  PIN rowReadON_TOP<0>
    ANTENNAGATEAREA 16.128000 ;
    PORT
      LAYER met3 ;
        RECT 279.055 866.395 279.385 866.725 ;
    END
  END rowReadON_TOP<0>
  PIN rowReadON_TOP<1>
    ANTENNAGATEAREA 16.128000 ;
    PORT
      LAYER met3 ;
        RECT 279.055 865.045 279.385 865.375 ;
    END
  END rowReadON_TOP<1>
  PIN rowReadON_TOP<2>
    ANTENNAGATEAREA 16.128000 ;
    PORT
      LAYER met3 ;
        RECT 279.055 842.395 279.385 842.725 ;
    END
  END rowReadON_TOP<2>
  PIN rowReadON_TOP<3>
    ANTENNAGATEAREA 16.128000 ;
    PORT
      LAYER met3 ;
        RECT 279.055 841.045 279.385 841.375 ;
    END
  END rowReadON_TOP<3>
  PIN rowReadON_TOP<4>
    ANTENNAGATEAREA 16.128000 ;
    PORT
      LAYER met3 ;
        RECT 279.055 818.395 279.385 818.725 ;
    END
  END rowReadON_TOP<4>
  PIN rowReadON_TOP<5>
    ANTENNAGATEAREA 16.128000 ;
    PORT
      LAYER met3 ;
        RECT 279.055 817.045 279.385 817.375 ;
    END
  END rowReadON_TOP<5>
  PIN rowReadON_TOP<6>
    ANTENNAGATEAREA 16.128000 ;
    PORT
      LAYER met3 ;
        RECT 279.055 794.395 279.385 794.725 ;
    END
  END rowReadON_TOP<6>
  PIN rowReadON_TOP<7>
    ANTENNAGATEAREA 16.128000 ;
    PORT
      LAYER met3 ;
        RECT 279.055 793.045 279.385 793.375 ;
    END
  END rowReadON_TOP<7>
  PIN rowReadON_TOP<8>
    ANTENNAGATEAREA 16.128000 ;
    PORT
      LAYER met3 ;
        RECT 279.055 770.395 279.385 770.725 ;
    END
  END rowReadON_TOP<8>
  PIN rowReadON_TOP<9>
    ANTENNAGATEAREA 16.128000 ;
    PORT
      LAYER met3 ;
        RECT 279.055 769.045 279.385 769.375 ;
    END
  END rowReadON_TOP<9>
  PIN rowReadON_TOP<10>
    ANTENNAGATEAREA 16.128000 ;
    PORT
      LAYER met3 ;
        RECT 279.055 746.395 279.385 746.725 ;
    END
  END rowReadON_TOP<10>
  PIN rowReadON_TOP<11>
    ANTENNAGATEAREA 16.128000 ;
    PORT
      LAYER met3 ;
        RECT 279.055 745.045 279.385 745.375 ;
    END
  END rowReadON_TOP<11>
  PIN rowReadON_TOP<12>
    ANTENNAGATEAREA 16.128000 ;
    PORT
      LAYER met3 ;
        RECT 279.055 722.395 279.385 722.725 ;
    END
  END rowReadON_TOP<12>
  PIN rowReadON_TOP<13>
    ANTENNAGATEAREA 16.128000 ;
    PORT
      LAYER met3 ;
        RECT 279.055 721.045 279.385 721.375 ;
    END
  END rowReadON_TOP<13>
  PIN rowReadON_TOP<14>
    ANTENNAGATEAREA 16.128000 ;
    PORT
      LAYER met3 ;
        RECT 279.055 698.395 279.385 698.725 ;
    END
  END rowReadON_TOP<14>
  PIN rowReadON_TOP<15>
    ANTENNAGATEAREA 16.128000 ;
    PORT
      LAYER met3 ;
        RECT 279.055 697.045 279.385 697.375 ;
    END
  END rowReadON_TOP<15>
  PIN rowReadON_TOP<16>
    ANTENNAGATEAREA 16.128000 ;
    PORT
      LAYER met3 ;
        RECT 279.055 674.395 279.385 674.725 ;
    END
  END rowReadON_TOP<16>
  PIN rowReadON_TOP<17>
    ANTENNAGATEAREA 16.128000 ;
    PORT
      LAYER met3 ;
        RECT 279.055 673.045 279.385 673.375 ;
    END
  END rowReadON_TOP<17>
  PIN rowReadON_TOP<18>
    ANTENNAGATEAREA 16.128000 ;
    PORT
      LAYER met3 ;
        RECT 279.055 650.395 279.385 650.725 ;
    END
  END rowReadON_TOP<18>
  PIN rowReadON_TOP<19>
    ANTENNAGATEAREA 16.128000 ;
    PORT
      LAYER met3 ;
        RECT 279.055 649.045 279.385 649.375 ;
    END
  END rowReadON_TOP<19>
  PIN rowReadON_TOP<20>
    ANTENNAGATEAREA 16.128000 ;
    PORT
      LAYER met3 ;
        RECT 279.055 626.395 279.385 626.725 ;
    END
  END rowReadON_TOP<20>
  PIN rowReadON_TOP<21>
    ANTENNAGATEAREA 16.128000 ;
    PORT
      LAYER met3 ;
        RECT 279.055 625.045 279.385 625.375 ;
    END
  END rowReadON_TOP<21>
  PIN rowReadON_TOP<22>
    ANTENNAGATEAREA 16.128000 ;
    PORT
      LAYER met3 ;
        RECT 279.055 602.395 279.385 602.725 ;
    END
  END rowReadON_TOP<22>
  PIN rowReadON_TOP<23>
    ANTENNAGATEAREA 16.128000 ;
    PORT
      LAYER met3 ;
        RECT 279.055 601.045 279.385 601.375 ;
    END
  END rowReadON_TOP<23>
  PIN rowReadON_TOP<24>
    ANTENNAGATEAREA 16.128000 ;
    PORT
      LAYER met3 ;
        RECT 279.055 578.395 279.385 578.725 ;
    END
  END rowReadON_TOP<24>
  PIN rowReadON_TOP<25>
    ANTENNAGATEAREA 16.128000 ;
    PORT
      LAYER met3 ;
        RECT 279.055 577.045 279.385 577.375 ;
    END
  END rowReadON_TOP<25>
  PIN rowReadON_TOP<26>
    ANTENNAGATEAREA 16.128000 ;
    PORT
      LAYER met3 ;
        RECT 279.055 554.395 279.385 554.725 ;
    END
  END rowReadON_TOP<26>
  PIN rowReadON_TOP<27>
    ANTENNAGATEAREA 16.128000 ;
    PORT
      LAYER met3 ;
        RECT 279.055 553.045 279.385 553.375 ;
    END
  END rowReadON_TOP<27>
  PIN rowReadON_TOP<28>
    ANTENNAGATEAREA 16.128000 ;
    PORT
      LAYER met3 ;
        RECT 279.055 530.395 279.385 530.725 ;
    END
  END rowReadON_TOP<28>
  PIN rowReadON_TOP<29>
    ANTENNAGATEAREA 16.128000 ;
    PORT
      LAYER met3 ;
        RECT 279.055 529.045 279.385 529.375 ;
    END
  END rowReadON_TOP<29>
  PIN rowReadON_TOP<30>
    ANTENNAGATEAREA 16.128000 ;
    PORT
      LAYER met3 ;
        RECT 279.055 506.395 279.385 506.725 ;
    END
  END rowReadON_TOP<30>
  PIN rowReadON_TOP<31>
    ANTENNAGATEAREA 16.128000 ;
    PORT
      LAYER met3 ;
        RECT 279.055 505.045 279.385 505.375 ;
    END
  END rowReadON_TOP<31>
  PIN rowReadON_TOP<32>
    ANTENNAGATEAREA 16.128000 ;
    PORT
      LAYER met3 ;
        RECT 279.055 482.395 279.385 482.725 ;
    END
  END rowReadON_TOP<32>
  PIN rowReadON_TOP<33>
    ANTENNAGATEAREA 16.128000 ;
    PORT
      LAYER met3 ;
        RECT 279.055 481.045 279.385 481.375 ;
    END
  END rowReadON_TOP<33>
  PIN rowReadON_TOP<34>
    ANTENNAGATEAREA 16.128000 ;
    PORT
      LAYER met3 ;
        RECT 279.055 458.395 279.385 458.725 ;
    END
  END rowReadON_TOP<34>
  PIN rowReadON_TOP<35>
    ANTENNAGATEAREA 16.128000 ;
    PORT
      LAYER met3 ;
        RECT 279.055 457.045 279.385 457.375 ;
    END
  END rowReadON_TOP<35>
  PIN rowReadON_TOP<36>
    ANTENNAGATEAREA 16.128000 ;
    PORT
      LAYER met3 ;
        RECT 279.055 434.395 279.385 434.725 ;
    END
  END rowReadON_TOP<36>
  PIN rowReadON_TOP<37>
    ANTENNAGATEAREA 16.128000 ;
    PORT
      LAYER met3 ;
        RECT 279.055 433.045 279.385 433.375 ;
    END
  END rowReadON_TOP<37>
  PIN rowReadON_TOP<38>
    ANTENNAGATEAREA 16.128000 ;
    PORT
      LAYER met3 ;
        RECT 279.055 410.395 279.385 410.725 ;
    END
  END rowReadON_TOP<38>
  PIN rowReadON_TOP<39>
    ANTENNAGATEAREA 16.128000 ;
    PORT
      LAYER met3 ;
        RECT 279.055 409.045 279.385 409.375 ;
    END
  END rowReadON_TOP<39>
  PIN rowReadON_TOP<40>
    ANTENNAGATEAREA 16.128000 ;
    PORT
      LAYER met3 ;
        RECT 279.055 386.395 279.385 386.725 ;
    END
  END rowReadON_TOP<40>
  PIN rowReadON_TOP<41>
    ANTENNAGATEAREA 16.128000 ;
    PORT
      LAYER met3 ;
        RECT 279.055 385.045 279.385 385.375 ;
    END
  END rowReadON_TOP<41>
  PIN rowReadON_TOP<42>
    ANTENNAGATEAREA 16.128000 ;
    PORT
      LAYER met3 ;
        RECT 279.055 362.395 279.385 362.725 ;
    END
  END rowReadON_TOP<42>
  PIN rowReadON_TOP<43>
    ANTENNAGATEAREA 16.128000 ;
    PORT
      LAYER met3 ;
        RECT 279.055 361.045 279.385 361.375 ;
    END
  END rowReadON_TOP<43>
  PIN rowReadON_TOP<44>
    ANTENNAGATEAREA 16.128000 ;
    PORT
      LAYER met3 ;
        RECT 279.055 338.395 279.385 338.725 ;
    END
  END rowReadON_TOP<44>
  PIN rowReadON_TOP<45>
    ANTENNAGATEAREA 16.128000 ;
    PORT
      LAYER met3 ;
        RECT 279.055 337.045 279.385 337.375 ;
    END
  END rowReadON_TOP<45>
  PIN rowReadON_TOP<46>
    ANTENNAGATEAREA 16.128000 ;
    PORT
      LAYER met3 ;
        RECT 279.055 314.395 279.385 314.725 ;
    END
  END rowReadON_TOP<46>
  PIN rowReadON_TOP<47>
    ANTENNAGATEAREA 16.128000 ;
    PORT
      LAYER met3 ;
        RECT 279.055 313.045 279.385 313.375 ;
    END
  END rowReadON_TOP<47>
  PIN rowReadON_TOP<48>
    ANTENNAGATEAREA 16.128000 ;
    PORT
      LAYER met3 ;
        RECT 279.055 290.395 279.385 290.725 ;
    END
  END rowReadON_TOP<48>
  PIN rowReadON_TOP<49>
    ANTENNAGATEAREA 16.128000 ;
    PORT
      LAYER met3 ;
        RECT 279.055 289.045 279.385 289.375 ;
    END
  END rowReadON_TOP<49>
  PIN rowReadON_TOP<50>
    ANTENNAGATEAREA 16.128000 ;
    PORT
      LAYER met3 ;
        RECT 279.055 266.395 279.385 266.725 ;
    END
  END rowReadON_TOP<50>
  PIN rowReadON_TOP<51>
    ANTENNAGATEAREA 16.128000 ;
    PORT
      LAYER met3 ;
        RECT 279.055 265.045 279.385 265.375 ;
    END
  END rowReadON_TOP<51>
  PIN rowReadON_TOP<52>
    ANTENNAGATEAREA 16.128000 ;
    PORT
      LAYER met3 ;
        RECT 279.055 242.395 279.385 242.725 ;
    END
  END rowReadON_TOP<52>
  PIN rowReadON_TOP<53>
    ANTENNAGATEAREA 16.128000 ;
    PORT
      LAYER met3 ;
        RECT 279.055 241.045 279.385 241.375 ;
    END
  END rowReadON_TOP<53>
  PIN rowReadON_TOP<54>
    ANTENNAGATEAREA 16.128000 ;
    PORT
      LAYER met3 ;
        RECT 279.055 218.395 279.385 218.725 ;
    END
  END rowReadON_TOP<54>
  PIN rowReadON_TOP<55>
    ANTENNAGATEAREA 16.128000 ;
    PORT
      LAYER met3 ;
        RECT 279.055 217.045 279.385 217.375 ;
    END
  END rowReadON_TOP<55>
  PIN rowReadON_TOP<56>
    ANTENNAGATEAREA 16.128000 ;
    PORT
      LAYER met3 ;
        RECT 279.055 194.395 279.385 194.725 ;
    END
  END rowReadON_TOP<56>
  PIN rowReadON_TOP<57>
    ANTENNAGATEAREA 16.128000 ;
    PORT
      LAYER met3 ;
        RECT 279.055 193.045 279.385 193.375 ;
    END
  END rowReadON_TOP<57>
  PIN rowReadON_TOP<58>
    ANTENNAGATEAREA 16.128000 ;
    PORT
      LAYER met3 ;
        RECT 279.055 170.395 279.385 170.725 ;
    END
  END rowReadON_TOP<58>
  PIN rowReadON_TOP<59>
    ANTENNAGATEAREA 16.128000 ;
    PORT
      LAYER met3 ;
        RECT 279.055 169.045 279.385 169.375 ;
    END
  END rowReadON_TOP<59>
  PIN rowReadON_TOP<60>
    ANTENNAGATEAREA 16.128000 ;
    PORT
      LAYER met3 ;
        RECT 279.055 146.395 279.385 146.725 ;
    END
  END rowReadON_TOP<60>
  PIN rowReadON_TOP<61>
    ANTENNAGATEAREA 16.128000 ;
    PORT
      LAYER met3 ;
        RECT 279.055 145.045 279.385 145.375 ;
    END
  END rowReadON_TOP<61>
  PIN rowReadON_TOP<62>
    ANTENNAGATEAREA 16.128000 ;
    PORT
      LAYER met3 ;
        RECT 279.055 122.395 279.385 122.725 ;
    END
  END rowReadON_TOP<62>
  PIN rowReadON_TOP<63>
    ANTENNAGATEAREA 16.128000 ;
    PORT
      LAYER met3 ;
        RECT 279.055 121.045 279.385 121.375 ;
    END
  END rowReadON_TOP<63>
  PIN rowReadON_BOT<0>
    ANTENNAGATEAREA 16.128000 ;
    PORT
      LAYER met3 ;
        RECT 279.055 -646.955 279.385 -646.625 ;
    END
  END rowReadON_BOT<0>
  PIN rowReadON_BOT<1>
    ANTENNAGATEAREA 16.128000 ;
    PORT
      LAYER met3 ;
        RECT 279.055 -645.605 279.385 -645.275 ;
    END
  END rowReadON_BOT<1>
  PIN rowReadON_BOT<2>
    ANTENNAGATEAREA 16.128000 ;
    PORT
      LAYER met3 ;
        RECT 279.055 -622.955 279.385 -622.625 ;
    END
  END rowReadON_BOT<2>
  PIN rowReadON_BOT<3>
    ANTENNAGATEAREA 16.128000 ;
    PORT
      LAYER met3 ;
        RECT 279.055 -621.605 279.385 -621.275 ;
    END
  END rowReadON_BOT<3>
  PIN rowReadON_BOT<4>
    ANTENNAGATEAREA 16.128000 ;
    PORT
      LAYER met3 ;
        RECT 279.055 -598.955 279.385 -598.625 ;
    END
  END rowReadON_BOT<4>
  PIN rowReadON_BOT<5>
    ANTENNAGATEAREA 16.128000 ;
    PORT
      LAYER met3 ;
        RECT 279.055 -597.605 279.385 -597.275 ;
    END
  END rowReadON_BOT<5>
  PIN rowReadON_BOT<6>
    ANTENNAGATEAREA 16.128000 ;
    PORT
      LAYER met3 ;
        RECT 279.055 -574.955 279.385 -574.625 ;
    END
  END rowReadON_BOT<6>
  PIN rowReadON_BOT<7>
    ANTENNAGATEAREA 16.128000 ;
    PORT
      LAYER met3 ;
        RECT 279.055 -573.605 279.385 -573.275 ;
    END
  END rowReadON_BOT<7>
  PIN rowReadON_BOT<8>
    ANTENNAGATEAREA 16.128000 ;
    PORT
      LAYER met3 ;
        RECT 279.055 -550.955 279.385 -550.625 ;
    END
  END rowReadON_BOT<8>
  PIN rowReadON_BOT<9>
    ANTENNAGATEAREA 16.128000 ;
    PORT
      LAYER met3 ;
        RECT 279.055 -549.605 279.385 -549.275 ;
    END
  END rowReadON_BOT<9>
  PIN rowReadON_BOT<10>
    ANTENNAGATEAREA 16.128000 ;
    PORT
      LAYER met3 ;
        RECT 279.055 -526.955 279.385 -526.625 ;
    END
  END rowReadON_BOT<10>
  PIN rowReadON_BOT<11>
    ANTENNAGATEAREA 16.128000 ;
    PORT
      LAYER met3 ;
        RECT 279.055 -525.605 279.385 -525.275 ;
    END
  END rowReadON_BOT<11>
  PIN rowReadON_BOT<12>
    ANTENNAGATEAREA 16.128000 ;
    PORT
      LAYER met3 ;
        RECT 279.055 -502.955 279.385 -502.625 ;
    END
  END rowReadON_BOT<12>
  PIN rowReadON_BOT<13>
    ANTENNAGATEAREA 16.128000 ;
    PORT
      LAYER met3 ;
        RECT 279.055 -501.605 279.385 -501.275 ;
    END
  END rowReadON_BOT<13>
  PIN rowReadON_BOT<14>
    ANTENNAGATEAREA 16.128000 ;
    PORT
      LAYER met3 ;
        RECT 279.055 -478.955 279.385 -478.625 ;
    END
  END rowReadON_BOT<14>
  PIN rowReadON_BOT<15>
    ANTENNAGATEAREA 16.128000 ;
    PORT
      LAYER met3 ;
        RECT 279.055 -477.605 279.385 -477.275 ;
    END
  END rowReadON_BOT<15>
  PIN rowReadON_BOT<16>
    ANTENNAGATEAREA 16.128000 ;
    PORT
      LAYER met3 ;
        RECT 279.055 -454.955 279.385 -454.625 ;
    END
  END rowReadON_BOT<16>
  PIN rowReadON_BOT<17>
    ANTENNAGATEAREA 16.128000 ;
    PORT
      LAYER met3 ;
        RECT 279.055 -453.605 279.385 -453.275 ;
    END
  END rowReadON_BOT<17>
  PIN rowReadON_BOT<18>
    ANTENNAGATEAREA 16.128000 ;
    PORT
      LAYER met3 ;
        RECT 279.055 -430.955 279.385 -430.625 ;
    END
  END rowReadON_BOT<18>
  PIN rowReadON_BOT<19>
    ANTENNAGATEAREA 16.128000 ;
    PORT
      LAYER met3 ;
        RECT 279.055 -429.605 279.385 -429.275 ;
    END
  END rowReadON_BOT<19>
  PIN rowReadON_BOT<20>
    ANTENNAGATEAREA 16.128000 ;
    PORT
      LAYER met3 ;
        RECT 279.055 -406.955 279.385 -406.625 ;
    END
  END rowReadON_BOT<20>
  PIN rowReadON_BOT<21>
    ANTENNAGATEAREA 16.128000 ;
    PORT
      LAYER met3 ;
        RECT 279.055 -405.605 279.385 -405.275 ;
    END
  END rowReadON_BOT<21>
  PIN rowReadON_BOT<22>
    ANTENNAGATEAREA 16.128000 ;
    PORT
      LAYER met3 ;
        RECT 279.055 -382.955 279.385 -382.625 ;
    END
  END rowReadON_BOT<22>
  PIN rowReadON_BOT<23>
    ANTENNAGATEAREA 16.128000 ;
    PORT
      LAYER met3 ;
        RECT 279.055 -381.605 279.385 -381.275 ;
    END
  END rowReadON_BOT<23>
  PIN rowReadON_BOT<24>
    ANTENNAGATEAREA 16.128000 ;
    PORT
      LAYER met3 ;
        RECT 279.055 -358.955 279.385 -358.625 ;
    END
  END rowReadON_BOT<24>
  PIN rowReadON_BOT<25>
    ANTENNAGATEAREA 16.128000 ;
    PORT
      LAYER met3 ;
        RECT 279.055 -357.605 279.385 -357.275 ;
    END
  END rowReadON_BOT<25>
  PIN rowReadON_BOT<26>
    ANTENNAGATEAREA 16.128000 ;
    PORT
      LAYER met3 ;
        RECT 279.055 -334.955 279.385 -334.625 ;
    END
  END rowReadON_BOT<26>
  PIN rowReadON_BOT<27>
    ANTENNAGATEAREA 16.128000 ;
    PORT
      LAYER met3 ;
        RECT 279.055 -333.605 279.385 -333.275 ;
    END
  END rowReadON_BOT<27>
  PIN rowReadON_BOT<28>
    ANTENNAGATEAREA 16.128000 ;
    PORT
      LAYER met3 ;
        RECT 279.055 -310.955 279.385 -310.625 ;
    END
  END rowReadON_BOT<28>
  PIN rowReadON_BOT<29>
    ANTENNAGATEAREA 16.128000 ;
    PORT
      LAYER met3 ;
        RECT 279.055 -309.605 279.385 -309.275 ;
    END
  END rowReadON_BOT<29>
  PIN rowReadON_BOT<30>
    ANTENNAGATEAREA 16.128000 ;
    PORT
      LAYER met3 ;
        RECT 279.055 -286.955 279.385 -286.625 ;
    END
  END rowReadON_BOT<30>
  PIN rowReadON_BOT<31>
    ANTENNAGATEAREA 16.128000 ;
    PORT
      LAYER met3 ;
        RECT 279.055 -285.605 279.385 -285.275 ;
    END
  END rowReadON_BOT<31>
  PIN rowReadON_BOT<32>
    ANTENNAGATEAREA 16.128000 ;
    PORT
      LAYER met3 ;
        RECT 279.055 -262.955 279.385 -262.625 ;
    END
  END rowReadON_BOT<32>
  PIN rowReadON_BOT<33>
    ANTENNAGATEAREA 16.128000 ;
    PORT
      LAYER met3 ;
        RECT 279.055 -261.605 279.385 -261.275 ;
    END
  END rowReadON_BOT<33>
  PIN rowReadON_BOT<34>
    ANTENNAGATEAREA 16.128000 ;
    PORT
      LAYER met3 ;
        RECT 279.055 -238.955 279.385 -238.625 ;
    END
  END rowReadON_BOT<34>
  PIN rowReadON_BOT<35>
    ANTENNAGATEAREA 16.128000 ;
    PORT
      LAYER met3 ;
        RECT 279.055 -237.605 279.385 -237.275 ;
    END
  END rowReadON_BOT<35>
  PIN rowReadON_BOT<36>
    ANTENNAGATEAREA 16.128000 ;
    PORT
      LAYER met3 ;
        RECT 279.055 -214.955 279.385 -214.625 ;
    END
  END rowReadON_BOT<36>
  PIN rowReadON_BOT<37>
    ANTENNAGATEAREA 16.128000 ;
    PORT
      LAYER met3 ;
        RECT 279.055 -213.605 279.385 -213.275 ;
    END
  END rowReadON_BOT<37>
  PIN rowReadON_BOT<38>
    ANTENNAGATEAREA 16.128000 ;
    PORT
      LAYER met3 ;
        RECT 279.055 -190.955 279.385 -190.625 ;
    END
  END rowReadON_BOT<38>
  PIN rowReadON_BOT<39>
    ANTENNAGATEAREA 16.128000 ;
    PORT
      LAYER met3 ;
        RECT 279.055 -189.605 279.385 -189.275 ;
    END
  END rowReadON_BOT<39>
  PIN rowReadON_BOT<40>
    ANTENNAGATEAREA 16.128000 ;
    PORT
      LAYER met3 ;
        RECT 279.055 -166.955 279.385 -166.625 ;
    END
  END rowReadON_BOT<40>
  PIN rowReadON_BOT<41>
    ANTENNAGATEAREA 16.128000 ;
    PORT
      LAYER met3 ;
        RECT 279.055 -165.605 279.385 -165.275 ;
    END
  END rowReadON_BOT<41>
  PIN rowReadON_BOT<42>
    ANTENNAGATEAREA 16.128000 ;
    PORT
      LAYER met3 ;
        RECT 279.055 -142.955 279.385 -142.625 ;
    END
  END rowReadON_BOT<42>
  PIN rowReadON_BOT<43>
    ANTENNAGATEAREA 16.128000 ;
    PORT
      LAYER met3 ;
        RECT 279.055 -141.605 279.385 -141.275 ;
    END
  END rowReadON_BOT<43>
  PIN rowReadON_BOT<44>
    ANTENNAGATEAREA 16.128000 ;
    PORT
      LAYER met3 ;
        RECT 279.055 -118.955 279.385 -118.625 ;
    END
  END rowReadON_BOT<44>
  PIN rowReadON_BOT<45>
    ANTENNAGATEAREA 16.128000 ;
    PORT
      LAYER met3 ;
        RECT 279.055 -117.605 279.385 -117.275 ;
    END
  END rowReadON_BOT<45>
  PIN rowReadON_BOT<46>
    ANTENNAGATEAREA 16.128000 ;
    PORT
      LAYER met3 ;
        RECT 279.055 -94.955 279.385 -94.625 ;
    END
  END rowReadON_BOT<46>
  PIN rowReadON_BOT<47>
    ANTENNAGATEAREA 16.128000 ;
    PORT
      LAYER met3 ;
        RECT 279.055 -93.605 279.385 -93.275 ;
    END
  END rowReadON_BOT<47>
  PIN rowReadON_BOT<48>
    ANTENNAGATEAREA 16.128000 ;
    PORT
      LAYER met3 ;
        RECT 279.055 -70.955 279.385 -70.625 ;
    END
  END rowReadON_BOT<48>
  PIN rowReadON_BOT<49>
    ANTENNAGATEAREA 16.128000 ;
    PORT
      LAYER met3 ;
        RECT 279.055 -69.605 279.385 -69.275 ;
    END
  END rowReadON_BOT<49>
  PIN rowReadON_BOT<50>
    ANTENNAGATEAREA 16.128000 ;
    PORT
      LAYER met3 ;
        RECT 279.055 -46.955 279.385 -46.625 ;
    END
  END rowReadON_BOT<50>
  PIN rowReadON_BOT<51>
    ANTENNAGATEAREA 16.128000 ;
    PORT
      LAYER met3 ;
        RECT 279.055 -45.605 279.385 -45.275 ;
    END
  END rowReadON_BOT<51>
  PIN rowReadON_BOT<52>
    ANTENNAGATEAREA 16.128000 ;
    PORT
      LAYER met3 ;
        RECT 279.055 -22.955 279.385 -22.625 ;
    END
  END rowReadON_BOT<52>
  PIN rowReadON_BOT<53>
    ANTENNAGATEAREA 16.128000 ;
    PORT
      LAYER met3 ;
        RECT 279.055 -21.605 279.385 -21.275 ;
    END
  END rowReadON_BOT<53>
  PIN rowReadON_BOT<54>
    ANTENNAGATEAREA 16.128000 ;
    PORT
      LAYER met3 ;
        RECT 279.055 1.045 279.385 1.375 ;
    END
  END rowReadON_BOT<54>
  PIN rowReadON_BOT<55>
    ANTENNAGATEAREA 16.128000 ;
    PORT
      LAYER met3 ;
        RECT 279.055 2.395 279.385 2.725 ;
    END
  END rowReadON_BOT<55>
  PIN rowReadON_BOT<56>
    ANTENNAGATEAREA 16.128000 ;
    PORT
      LAYER met3 ;
        RECT 279.055 25.045 279.385 25.375 ;
    END
  END rowReadON_BOT<56>
  PIN rowReadON_BOT<57>
    ANTENNAGATEAREA 16.128000 ;
    PORT
      LAYER met3 ;
        RECT 279.055 26.395 279.385 26.725 ;
    END
  END rowReadON_BOT<57>
  PIN rowReadON_BOT<58>
    ANTENNAGATEAREA 16.128000 ;
    PORT
      LAYER met3 ;
        RECT 279.055 49.045 279.385 49.375 ;
    END
  END rowReadON_BOT<58>
  PIN rowReadON_BOT<59>
    ANTENNAGATEAREA 16.128000 ;
    PORT
      LAYER met3 ;
        RECT 279.055 50.395 279.385 50.725 ;
    END
  END rowReadON_BOT<59>
  PIN rowReadON_BOT<60>
    ANTENNAGATEAREA 16.128000 ;
    PORT
      LAYER met3 ;
        RECT 279.055 73.045 279.385 73.375 ;
    END
  END rowReadON_BOT<60>
  PIN rowReadON_BOT<61>
    ANTENNAGATEAREA 16.128000 ;
    PORT
      LAYER met3 ;
        RECT 279.055 74.395 279.385 74.725 ;
    END
  END rowReadON_BOT<61>
  PIN rowReadON_BOT<62>
    ANTENNAGATEAREA 16.128000 ;
    PORT
      LAYER met3 ;
        RECT 279.055 97.045 279.385 97.375 ;
    END
  END rowReadON_BOT<62>
  PIN rowReadON_BOT<63>
    ANTENNAGATEAREA 16.128000 ;
    PORT
      LAYER met3 ;
        RECT 279.055 98.395 279.385 98.725 ;
    END
  END rowReadON_BOT<63>
  PIN NCHARGE_TOP
    ANTENNAGATEAREA 1024.000000 ;
    PORT
      LAYER met2 ;
        RECT 280.540 896.875 280.840 897.885 ;
    END
  END NCHARGE_TOP
  PIN nDETECT_TOP
    ANTENNAGATEAREA 64.000000 ;
    PORT
      LAYER met2 ;
        RECT 280.540 916.965 280.840 917.965 ;
    END
  END nDETECT_TOP
  PIN DETECT_TOP
    ANTENNAGATEAREA 147.199997 ;
    PORT
      LAYER met2 ;
        RECT 280.540 908.435 280.840 909.435 ;
    END
  END DETECT_TOP
  PIN nDETECT_BOT
    ANTENNAGATEAREA 64.000000 ;
    PORT
      LAYER met2 ;
        RECT 280.540 -698.195 280.840 -697.195 ;
    END
  END nDETECT_BOT
  PIN DETECT_BOT
    ANTENNAGATEAREA 147.199997 ;
    PORT
      LAYER met2 ;
        RECT 280.540 -689.665 280.840 -688.665 ;
    END
  END DETECT_BOT
  PIN NCHARGE_BOT
    ANTENNAGATEAREA 1024.000000 ;
    PORT
      LAYER met2 ;
        RECT 280.540 -678.115 280.840 -677.105 ;
    END
  END NCHARGE_BOT
  OBS
      LAYER nwell ;
        RECT 280.260 -708.090 1816.820 927.860 ;
      LAYER li1 ;
        RECT 280.375 -707.960 1816.705 927.730 ;
      LAYER met1 ;
        RECT 280.220 -708.105 1820.800 927.790 ;
      LAYER met2 ;
        RECT 278.615 918.245 1833.870 927.645 ;
        RECT 278.615 916.685 280.260 918.245 ;
        RECT 281.120 916.685 1833.870 918.245 ;
        RECT 278.615 909.715 1833.870 916.685 ;
        RECT 278.615 908.155 280.260 909.715 ;
        RECT 281.120 908.155 1833.870 909.715 ;
        RECT 278.615 898.165 1833.870 908.155 ;
        RECT 278.615 896.595 280.260 898.165 ;
        RECT 281.120 896.595 1833.870 898.165 ;
        RECT 278.615 -676.825 1833.870 896.595 ;
        RECT 278.615 -678.395 280.260 -676.825 ;
        RECT 281.120 -678.395 1833.870 -676.825 ;
        RECT 278.615 -688.385 1833.870 -678.395 ;
        RECT 278.615 -689.945 280.260 -688.385 ;
        RECT 281.120 -689.945 1833.870 -688.385 ;
        RECT 278.615 -696.915 1833.870 -689.945 ;
        RECT 278.615 -698.475 280.260 -696.915 ;
        RECT 281.120 -698.475 1833.870 -696.915 ;
        RECT 278.615 -707.790 1833.870 -698.475 ;
      LAYER met3 ;
        RECT 278.615 926.710 1833.870 927.730 ;
        RECT 278.615 926.590 283.695 926.710 ;
        RECT 278.615 925.490 280.950 926.590 ;
        RECT 282.050 925.610 283.695 926.590 ;
        RECT 285.265 925.610 299.815 926.710 ;
        RECT 301.385 926.590 307.695 926.710 ;
        RECT 301.385 925.610 303.045 926.590 ;
        RECT 282.050 925.490 303.045 925.610 ;
        RECT 304.145 925.490 304.950 926.590 ;
        RECT 306.050 925.610 307.695 926.590 ;
        RECT 309.265 925.610 323.815 926.710 ;
        RECT 325.385 926.590 331.695 926.710 ;
        RECT 325.385 925.610 327.045 926.590 ;
        RECT 306.050 925.490 327.045 925.610 ;
        RECT 328.145 925.490 328.950 926.590 ;
        RECT 330.050 925.610 331.695 926.590 ;
        RECT 333.265 925.610 347.815 926.710 ;
        RECT 349.385 926.590 355.695 926.710 ;
        RECT 349.385 925.610 351.045 926.590 ;
        RECT 330.050 925.490 351.045 925.610 ;
        RECT 352.145 925.490 352.950 926.590 ;
        RECT 354.050 925.610 355.695 926.590 ;
        RECT 357.265 925.610 371.815 926.710 ;
        RECT 373.385 926.590 379.695 926.710 ;
        RECT 373.385 925.610 375.045 926.590 ;
        RECT 354.050 925.490 375.045 925.610 ;
        RECT 376.145 925.490 376.950 926.590 ;
        RECT 378.050 925.610 379.695 926.590 ;
        RECT 381.265 925.610 395.815 926.710 ;
        RECT 397.385 926.590 403.695 926.710 ;
        RECT 397.385 925.610 399.045 926.590 ;
        RECT 378.050 925.490 399.045 925.610 ;
        RECT 400.145 925.490 400.950 926.590 ;
        RECT 402.050 925.610 403.695 926.590 ;
        RECT 405.265 925.610 419.815 926.710 ;
        RECT 421.385 926.590 427.695 926.710 ;
        RECT 421.385 925.610 423.045 926.590 ;
        RECT 402.050 925.490 423.045 925.610 ;
        RECT 424.145 925.490 424.950 926.590 ;
        RECT 426.050 925.610 427.695 926.590 ;
        RECT 429.265 925.610 443.815 926.710 ;
        RECT 445.385 926.590 451.695 926.710 ;
        RECT 445.385 925.610 447.045 926.590 ;
        RECT 426.050 925.490 447.045 925.610 ;
        RECT 448.145 925.490 448.950 926.590 ;
        RECT 450.050 925.610 451.695 926.590 ;
        RECT 453.265 925.610 467.815 926.710 ;
        RECT 469.385 926.590 475.695 926.710 ;
        RECT 469.385 925.610 471.045 926.590 ;
        RECT 450.050 925.490 471.045 925.610 ;
        RECT 472.145 925.490 472.950 926.590 ;
        RECT 474.050 925.610 475.695 926.590 ;
        RECT 477.265 925.610 491.815 926.710 ;
        RECT 493.385 926.590 499.695 926.710 ;
        RECT 493.385 925.610 495.045 926.590 ;
        RECT 474.050 925.490 495.045 925.610 ;
        RECT 496.145 925.490 496.950 926.590 ;
        RECT 498.050 925.610 499.695 926.590 ;
        RECT 501.265 925.610 515.815 926.710 ;
        RECT 517.385 926.590 523.695 926.710 ;
        RECT 517.385 925.610 519.045 926.590 ;
        RECT 498.050 925.490 519.045 925.610 ;
        RECT 520.145 925.490 520.950 926.590 ;
        RECT 522.050 925.610 523.695 926.590 ;
        RECT 525.265 925.610 539.815 926.710 ;
        RECT 541.385 926.590 547.695 926.710 ;
        RECT 541.385 925.610 543.045 926.590 ;
        RECT 522.050 925.490 543.045 925.610 ;
        RECT 544.145 925.490 544.950 926.590 ;
        RECT 546.050 925.610 547.695 926.590 ;
        RECT 549.265 925.610 563.815 926.710 ;
        RECT 565.385 926.590 571.695 926.710 ;
        RECT 565.385 925.610 567.045 926.590 ;
        RECT 546.050 925.490 567.045 925.610 ;
        RECT 568.145 925.490 568.950 926.590 ;
        RECT 570.050 925.610 571.695 926.590 ;
        RECT 573.265 925.610 587.815 926.710 ;
        RECT 589.385 926.590 595.695 926.710 ;
        RECT 589.385 925.610 591.045 926.590 ;
        RECT 570.050 925.490 591.045 925.610 ;
        RECT 592.145 925.490 592.950 926.590 ;
        RECT 594.050 925.610 595.695 926.590 ;
        RECT 597.265 925.610 611.815 926.710 ;
        RECT 613.385 926.590 619.695 926.710 ;
        RECT 613.385 925.610 615.045 926.590 ;
        RECT 594.050 925.490 615.045 925.610 ;
        RECT 616.145 925.490 616.950 926.590 ;
        RECT 618.050 925.610 619.695 926.590 ;
        RECT 621.265 925.610 635.815 926.710 ;
        RECT 637.385 926.590 643.695 926.710 ;
        RECT 637.385 925.610 639.045 926.590 ;
        RECT 618.050 925.490 639.045 925.610 ;
        RECT 640.145 925.490 640.950 926.590 ;
        RECT 642.050 925.610 643.695 926.590 ;
        RECT 645.265 925.610 659.815 926.710 ;
        RECT 661.385 926.590 667.695 926.710 ;
        RECT 661.385 925.610 663.045 926.590 ;
        RECT 642.050 925.490 663.045 925.610 ;
        RECT 664.145 925.490 664.950 926.590 ;
        RECT 666.050 925.610 667.695 926.590 ;
        RECT 669.265 925.610 683.815 926.710 ;
        RECT 685.385 926.590 691.695 926.710 ;
        RECT 685.385 925.610 687.045 926.590 ;
        RECT 666.050 925.490 687.045 925.610 ;
        RECT 688.145 925.490 688.950 926.590 ;
        RECT 690.050 925.610 691.695 926.590 ;
        RECT 693.265 925.610 707.815 926.710 ;
        RECT 709.385 926.590 715.695 926.710 ;
        RECT 709.385 925.610 711.045 926.590 ;
        RECT 690.050 925.490 711.045 925.610 ;
        RECT 712.145 925.490 712.950 926.590 ;
        RECT 714.050 925.610 715.695 926.590 ;
        RECT 717.265 925.610 731.815 926.710 ;
        RECT 733.385 926.590 739.695 926.710 ;
        RECT 733.385 925.610 735.045 926.590 ;
        RECT 714.050 925.490 735.045 925.610 ;
        RECT 736.145 925.490 736.950 926.590 ;
        RECT 738.050 925.610 739.695 926.590 ;
        RECT 741.265 925.610 755.815 926.710 ;
        RECT 757.385 926.590 763.695 926.710 ;
        RECT 757.385 925.610 759.045 926.590 ;
        RECT 738.050 925.490 759.045 925.610 ;
        RECT 760.145 925.490 760.950 926.590 ;
        RECT 762.050 925.610 763.695 926.590 ;
        RECT 765.265 925.610 779.815 926.710 ;
        RECT 781.385 926.590 787.695 926.710 ;
        RECT 781.385 925.610 783.045 926.590 ;
        RECT 762.050 925.490 783.045 925.610 ;
        RECT 784.145 925.490 784.950 926.590 ;
        RECT 786.050 925.610 787.695 926.590 ;
        RECT 789.265 925.610 803.815 926.710 ;
        RECT 805.385 926.590 811.695 926.710 ;
        RECT 805.385 925.610 807.045 926.590 ;
        RECT 786.050 925.490 807.045 925.610 ;
        RECT 808.145 925.490 808.950 926.590 ;
        RECT 810.050 925.610 811.695 926.590 ;
        RECT 813.265 925.610 827.815 926.710 ;
        RECT 829.385 926.590 835.695 926.710 ;
        RECT 829.385 925.610 831.045 926.590 ;
        RECT 810.050 925.490 831.045 925.610 ;
        RECT 832.145 925.490 832.950 926.590 ;
        RECT 834.050 925.610 835.695 926.590 ;
        RECT 837.265 925.610 851.815 926.710 ;
        RECT 853.385 926.590 859.695 926.710 ;
        RECT 853.385 925.610 855.045 926.590 ;
        RECT 834.050 925.490 855.045 925.610 ;
        RECT 856.145 925.490 856.950 926.590 ;
        RECT 858.050 925.610 859.695 926.590 ;
        RECT 861.265 925.610 875.815 926.710 ;
        RECT 877.385 926.590 883.695 926.710 ;
        RECT 877.385 925.610 879.045 926.590 ;
        RECT 858.050 925.490 879.045 925.610 ;
        RECT 880.145 925.490 880.950 926.590 ;
        RECT 882.050 925.610 883.695 926.590 ;
        RECT 885.265 925.610 899.815 926.710 ;
        RECT 901.385 926.590 907.695 926.710 ;
        RECT 901.385 925.610 903.045 926.590 ;
        RECT 882.050 925.490 903.045 925.610 ;
        RECT 904.145 925.490 904.950 926.590 ;
        RECT 906.050 925.610 907.695 926.590 ;
        RECT 909.265 925.610 923.815 926.710 ;
        RECT 925.385 926.590 931.695 926.710 ;
        RECT 925.385 925.610 927.045 926.590 ;
        RECT 906.050 925.490 927.045 925.610 ;
        RECT 928.145 925.490 928.950 926.590 ;
        RECT 930.050 925.610 931.695 926.590 ;
        RECT 933.265 925.610 947.815 926.710 ;
        RECT 949.385 926.590 955.695 926.710 ;
        RECT 949.385 925.610 951.045 926.590 ;
        RECT 930.050 925.490 951.045 925.610 ;
        RECT 952.145 925.490 952.950 926.590 ;
        RECT 954.050 925.610 955.695 926.590 ;
        RECT 957.265 925.610 971.815 926.710 ;
        RECT 973.385 926.590 979.695 926.710 ;
        RECT 973.385 925.610 975.045 926.590 ;
        RECT 954.050 925.490 975.045 925.610 ;
        RECT 976.145 925.490 976.950 926.590 ;
        RECT 978.050 925.610 979.695 926.590 ;
        RECT 981.265 925.610 995.815 926.710 ;
        RECT 997.385 926.590 1003.695 926.710 ;
        RECT 997.385 925.610 999.045 926.590 ;
        RECT 978.050 925.490 999.045 925.610 ;
        RECT 1000.145 925.490 1000.950 926.590 ;
        RECT 1002.050 925.610 1003.695 926.590 ;
        RECT 1005.265 925.610 1019.815 926.710 ;
        RECT 1021.385 926.590 1027.695 926.710 ;
        RECT 1021.385 925.610 1023.045 926.590 ;
        RECT 1002.050 925.490 1023.045 925.610 ;
        RECT 1024.145 925.490 1024.950 926.590 ;
        RECT 1026.050 925.610 1027.695 926.590 ;
        RECT 1029.265 925.610 1043.815 926.710 ;
        RECT 1045.385 926.590 1051.695 926.710 ;
        RECT 1045.385 925.610 1047.045 926.590 ;
        RECT 1026.050 925.490 1047.045 925.610 ;
        RECT 1048.145 925.490 1048.950 926.590 ;
        RECT 1050.050 925.610 1051.695 926.590 ;
        RECT 1053.265 925.610 1067.815 926.710 ;
        RECT 1069.385 926.590 1075.695 926.710 ;
        RECT 1069.385 925.610 1071.045 926.590 ;
        RECT 1050.050 925.490 1071.045 925.610 ;
        RECT 1072.145 925.490 1072.950 926.590 ;
        RECT 1074.050 925.610 1075.695 926.590 ;
        RECT 1077.265 925.610 1091.815 926.710 ;
        RECT 1093.385 926.590 1099.695 926.710 ;
        RECT 1093.385 925.610 1095.045 926.590 ;
        RECT 1074.050 925.490 1095.045 925.610 ;
        RECT 1096.145 925.490 1096.950 926.590 ;
        RECT 1098.050 925.610 1099.695 926.590 ;
        RECT 1101.265 925.610 1115.815 926.710 ;
        RECT 1117.385 926.590 1123.695 926.710 ;
        RECT 1117.385 925.610 1119.045 926.590 ;
        RECT 1098.050 925.490 1119.045 925.610 ;
        RECT 1120.145 925.490 1120.950 926.590 ;
        RECT 1122.050 925.610 1123.695 926.590 ;
        RECT 1125.265 925.610 1139.815 926.710 ;
        RECT 1141.385 926.590 1147.695 926.710 ;
        RECT 1141.385 925.610 1143.045 926.590 ;
        RECT 1122.050 925.490 1143.045 925.610 ;
        RECT 1144.145 925.490 1144.950 926.590 ;
        RECT 1146.050 925.610 1147.695 926.590 ;
        RECT 1149.265 925.610 1163.815 926.710 ;
        RECT 1165.385 926.590 1171.695 926.710 ;
        RECT 1165.385 925.610 1167.045 926.590 ;
        RECT 1146.050 925.490 1167.045 925.610 ;
        RECT 1168.145 925.490 1168.950 926.590 ;
        RECT 1170.050 925.610 1171.695 926.590 ;
        RECT 1173.265 925.610 1187.815 926.710 ;
        RECT 1189.385 926.590 1195.695 926.710 ;
        RECT 1189.385 925.610 1191.045 926.590 ;
        RECT 1170.050 925.490 1191.045 925.610 ;
        RECT 1192.145 925.490 1192.950 926.590 ;
        RECT 1194.050 925.610 1195.695 926.590 ;
        RECT 1197.265 925.610 1211.815 926.710 ;
        RECT 1213.385 926.590 1219.695 926.710 ;
        RECT 1213.385 925.610 1215.045 926.590 ;
        RECT 1194.050 925.490 1215.045 925.610 ;
        RECT 1216.145 925.490 1216.950 926.590 ;
        RECT 1218.050 925.610 1219.695 926.590 ;
        RECT 1221.265 925.610 1235.815 926.710 ;
        RECT 1237.385 926.590 1243.695 926.710 ;
        RECT 1237.385 925.610 1239.045 926.590 ;
        RECT 1218.050 925.490 1239.045 925.610 ;
        RECT 1240.145 925.490 1240.950 926.590 ;
        RECT 1242.050 925.610 1243.695 926.590 ;
        RECT 1245.265 925.610 1259.815 926.710 ;
        RECT 1261.385 926.590 1267.695 926.710 ;
        RECT 1261.385 925.610 1263.045 926.590 ;
        RECT 1242.050 925.490 1263.045 925.610 ;
        RECT 1264.145 925.490 1264.950 926.590 ;
        RECT 1266.050 925.610 1267.695 926.590 ;
        RECT 1269.265 925.610 1283.815 926.710 ;
        RECT 1285.385 926.590 1291.695 926.710 ;
        RECT 1285.385 925.610 1287.045 926.590 ;
        RECT 1266.050 925.490 1287.045 925.610 ;
        RECT 1288.145 925.490 1288.950 926.590 ;
        RECT 1290.050 925.610 1291.695 926.590 ;
        RECT 1293.265 925.610 1307.815 926.710 ;
        RECT 1309.385 926.590 1315.695 926.710 ;
        RECT 1309.385 925.610 1311.045 926.590 ;
        RECT 1290.050 925.490 1311.045 925.610 ;
        RECT 1312.145 925.490 1312.950 926.590 ;
        RECT 1314.050 925.610 1315.695 926.590 ;
        RECT 1317.265 925.610 1331.815 926.710 ;
        RECT 1333.385 926.590 1339.695 926.710 ;
        RECT 1333.385 925.610 1335.045 926.590 ;
        RECT 1314.050 925.490 1335.045 925.610 ;
        RECT 1336.145 925.490 1336.950 926.590 ;
        RECT 1338.050 925.610 1339.695 926.590 ;
        RECT 1341.265 925.610 1355.815 926.710 ;
        RECT 1357.385 926.590 1363.695 926.710 ;
        RECT 1357.385 925.610 1359.045 926.590 ;
        RECT 1338.050 925.490 1359.045 925.610 ;
        RECT 1360.145 925.490 1360.950 926.590 ;
        RECT 1362.050 925.610 1363.695 926.590 ;
        RECT 1365.265 925.610 1379.815 926.710 ;
        RECT 1381.385 926.590 1387.695 926.710 ;
        RECT 1381.385 925.610 1383.045 926.590 ;
        RECT 1362.050 925.490 1383.045 925.610 ;
        RECT 1384.145 925.490 1384.950 926.590 ;
        RECT 1386.050 925.610 1387.695 926.590 ;
        RECT 1389.265 925.610 1403.815 926.710 ;
        RECT 1405.385 926.590 1411.695 926.710 ;
        RECT 1405.385 925.610 1407.045 926.590 ;
        RECT 1386.050 925.490 1407.045 925.610 ;
        RECT 1408.145 925.490 1408.950 926.590 ;
        RECT 1410.050 925.610 1411.695 926.590 ;
        RECT 1413.265 925.610 1427.815 926.710 ;
        RECT 1429.385 926.590 1435.695 926.710 ;
        RECT 1429.385 925.610 1431.045 926.590 ;
        RECT 1410.050 925.490 1431.045 925.610 ;
        RECT 1432.145 925.490 1432.950 926.590 ;
        RECT 1434.050 925.610 1435.695 926.590 ;
        RECT 1437.265 925.610 1451.815 926.710 ;
        RECT 1453.385 926.590 1459.695 926.710 ;
        RECT 1453.385 925.610 1455.045 926.590 ;
        RECT 1434.050 925.490 1455.045 925.610 ;
        RECT 1456.145 925.490 1456.950 926.590 ;
        RECT 1458.050 925.610 1459.695 926.590 ;
        RECT 1461.265 925.610 1475.815 926.710 ;
        RECT 1477.385 926.590 1483.695 926.710 ;
        RECT 1477.385 925.610 1479.045 926.590 ;
        RECT 1458.050 925.490 1479.045 925.610 ;
        RECT 1480.145 925.490 1480.950 926.590 ;
        RECT 1482.050 925.610 1483.695 926.590 ;
        RECT 1485.265 925.610 1499.815 926.710 ;
        RECT 1501.385 926.590 1507.695 926.710 ;
        RECT 1501.385 925.610 1503.045 926.590 ;
        RECT 1482.050 925.490 1503.045 925.610 ;
        RECT 1504.145 925.490 1504.950 926.590 ;
        RECT 1506.050 925.610 1507.695 926.590 ;
        RECT 1509.265 925.610 1523.815 926.710 ;
        RECT 1525.385 926.590 1531.695 926.710 ;
        RECT 1525.385 925.610 1527.045 926.590 ;
        RECT 1506.050 925.490 1527.045 925.610 ;
        RECT 1528.145 925.490 1528.950 926.590 ;
        RECT 1530.050 925.610 1531.695 926.590 ;
        RECT 1533.265 925.610 1547.815 926.710 ;
        RECT 1549.385 926.590 1555.695 926.710 ;
        RECT 1549.385 925.610 1551.045 926.590 ;
        RECT 1530.050 925.490 1551.045 925.610 ;
        RECT 1552.145 925.490 1552.950 926.590 ;
        RECT 1554.050 925.610 1555.695 926.590 ;
        RECT 1557.265 925.610 1571.815 926.710 ;
        RECT 1573.385 926.590 1579.695 926.710 ;
        RECT 1573.385 925.610 1575.045 926.590 ;
        RECT 1554.050 925.490 1575.045 925.610 ;
        RECT 1576.145 925.490 1576.950 926.590 ;
        RECT 1578.050 925.610 1579.695 926.590 ;
        RECT 1581.265 925.610 1595.815 926.710 ;
        RECT 1597.385 926.590 1603.695 926.710 ;
        RECT 1597.385 925.610 1599.045 926.590 ;
        RECT 1578.050 925.490 1599.045 925.610 ;
        RECT 1600.145 925.490 1600.950 926.590 ;
        RECT 1602.050 925.610 1603.695 926.590 ;
        RECT 1605.265 925.610 1619.815 926.710 ;
        RECT 1621.385 926.590 1627.695 926.710 ;
        RECT 1621.385 925.610 1623.045 926.590 ;
        RECT 1602.050 925.490 1623.045 925.610 ;
        RECT 1624.145 925.490 1624.950 926.590 ;
        RECT 1626.050 925.610 1627.695 926.590 ;
        RECT 1629.265 925.610 1643.815 926.710 ;
        RECT 1645.385 926.590 1651.695 926.710 ;
        RECT 1645.385 925.610 1647.045 926.590 ;
        RECT 1626.050 925.490 1647.045 925.610 ;
        RECT 1648.145 925.490 1648.950 926.590 ;
        RECT 1650.050 925.610 1651.695 926.590 ;
        RECT 1653.265 925.610 1667.815 926.710 ;
        RECT 1669.385 926.590 1675.695 926.710 ;
        RECT 1669.385 925.610 1671.045 926.590 ;
        RECT 1650.050 925.490 1671.045 925.610 ;
        RECT 1672.145 925.490 1672.950 926.590 ;
        RECT 1674.050 925.610 1675.695 926.590 ;
        RECT 1677.265 925.610 1691.815 926.710 ;
        RECT 1693.385 926.590 1699.695 926.710 ;
        RECT 1693.385 925.610 1695.045 926.590 ;
        RECT 1674.050 925.490 1695.045 925.610 ;
        RECT 1696.145 925.490 1696.950 926.590 ;
        RECT 1698.050 925.610 1699.695 926.590 ;
        RECT 1701.265 925.610 1715.815 926.710 ;
        RECT 1717.385 926.590 1723.695 926.710 ;
        RECT 1717.385 925.610 1719.045 926.590 ;
        RECT 1698.050 925.490 1719.045 925.610 ;
        RECT 1720.145 925.490 1720.950 926.590 ;
        RECT 1722.050 925.610 1723.695 926.590 ;
        RECT 1725.265 925.610 1739.815 926.710 ;
        RECT 1741.385 926.590 1747.695 926.710 ;
        RECT 1741.385 925.610 1743.045 926.590 ;
        RECT 1722.050 925.490 1743.045 925.610 ;
        RECT 1744.145 925.490 1744.950 926.590 ;
        RECT 1746.050 925.610 1747.695 926.590 ;
        RECT 1749.265 925.610 1763.815 926.710 ;
        RECT 1765.385 926.590 1771.695 926.710 ;
        RECT 1765.385 925.610 1767.045 926.590 ;
        RECT 1746.050 925.490 1767.045 925.610 ;
        RECT 1768.145 925.490 1768.950 926.590 ;
        RECT 1770.050 925.610 1771.695 926.590 ;
        RECT 1773.265 925.610 1787.815 926.710 ;
        RECT 1789.385 926.590 1795.695 926.710 ;
        RECT 1789.385 925.610 1791.045 926.590 ;
        RECT 1770.050 925.490 1791.045 925.610 ;
        RECT 1792.145 925.490 1792.950 926.590 ;
        RECT 1794.050 925.610 1795.695 926.590 ;
        RECT 1797.265 925.610 1811.815 926.710 ;
        RECT 1813.385 926.590 1833.870 926.710 ;
        RECT 1813.385 925.610 1815.045 926.590 ;
        RECT 1794.050 925.490 1815.045 925.610 ;
        RECT 1816.145 925.490 1833.870 926.590 ;
        RECT 278.615 867.855 1833.870 925.490 ;
        RECT 278.615 867.455 278.655 867.855 ;
        RECT 278.615 867.430 279.055 867.455 ;
        RECT 278.615 867.150 278.660 867.430 ;
        RECT 278.615 867.125 279.055 867.150 ;
        RECT 278.615 866.725 278.655 867.125 ;
        RECT 278.615 866.700 279.055 866.725 ;
        RECT 278.615 866.420 278.660 866.700 ;
        RECT 278.615 866.395 279.055 866.420 ;
        RECT 278.615 865.995 278.655 866.395 ;
        RECT 279.785 865.995 1833.870 867.855 ;
        RECT 278.615 865.775 1833.870 865.995 ;
        RECT 278.615 865.375 278.655 865.775 ;
        RECT 278.615 865.350 279.055 865.375 ;
        RECT 278.615 865.070 278.660 865.350 ;
        RECT 278.615 865.045 279.055 865.070 ;
        RECT 278.615 864.645 278.655 865.045 ;
        RECT 278.615 864.620 279.055 864.645 ;
        RECT 278.615 864.340 278.660 864.620 ;
        RECT 278.615 864.315 279.055 864.340 ;
        RECT 278.615 863.915 278.655 864.315 ;
        RECT 279.785 863.915 1833.870 865.775 ;
        RECT 278.615 843.855 1833.870 863.915 ;
        RECT 278.615 843.455 278.655 843.855 ;
        RECT 278.615 843.430 279.055 843.455 ;
        RECT 278.615 843.150 278.660 843.430 ;
        RECT 278.615 843.125 279.055 843.150 ;
        RECT 278.615 842.725 278.655 843.125 ;
        RECT 278.615 842.700 279.055 842.725 ;
        RECT 278.615 842.420 278.660 842.700 ;
        RECT 278.615 842.395 279.055 842.420 ;
        RECT 278.615 841.995 278.655 842.395 ;
        RECT 279.785 841.995 1833.870 843.855 ;
        RECT 278.615 841.775 1833.870 841.995 ;
        RECT 278.615 841.375 278.655 841.775 ;
        RECT 278.615 841.350 279.055 841.375 ;
        RECT 278.615 841.070 278.660 841.350 ;
        RECT 278.615 841.045 279.055 841.070 ;
        RECT 278.615 840.645 278.655 841.045 ;
        RECT 278.615 840.620 279.055 840.645 ;
        RECT 278.615 840.340 278.660 840.620 ;
        RECT 278.615 840.315 279.055 840.340 ;
        RECT 278.615 839.915 278.655 840.315 ;
        RECT 279.785 839.915 1833.870 841.775 ;
        RECT 278.615 819.855 1833.870 839.915 ;
        RECT 278.615 819.455 278.655 819.855 ;
        RECT 278.615 819.430 279.055 819.455 ;
        RECT 278.615 819.150 278.660 819.430 ;
        RECT 278.615 819.125 279.055 819.150 ;
        RECT 278.615 818.725 278.655 819.125 ;
        RECT 278.615 818.700 279.055 818.725 ;
        RECT 278.615 818.420 278.660 818.700 ;
        RECT 278.615 818.395 279.055 818.420 ;
        RECT 278.615 817.995 278.655 818.395 ;
        RECT 279.785 817.995 1833.870 819.855 ;
        RECT 278.615 817.775 1833.870 817.995 ;
        RECT 278.615 817.375 278.655 817.775 ;
        RECT 278.615 817.350 279.055 817.375 ;
        RECT 278.615 817.070 278.660 817.350 ;
        RECT 278.615 817.045 279.055 817.070 ;
        RECT 278.615 816.645 278.655 817.045 ;
        RECT 278.615 816.620 279.055 816.645 ;
        RECT 278.615 816.340 278.660 816.620 ;
        RECT 278.615 816.315 279.055 816.340 ;
        RECT 278.615 815.915 278.655 816.315 ;
        RECT 279.785 815.915 1833.870 817.775 ;
        RECT 278.615 795.855 1833.870 815.915 ;
        RECT 278.615 795.455 278.655 795.855 ;
        RECT 278.615 795.430 279.055 795.455 ;
        RECT 278.615 795.150 278.660 795.430 ;
        RECT 278.615 795.125 279.055 795.150 ;
        RECT 278.615 794.725 278.655 795.125 ;
        RECT 278.615 794.700 279.055 794.725 ;
        RECT 278.615 794.420 278.660 794.700 ;
        RECT 278.615 794.395 279.055 794.420 ;
        RECT 278.615 793.995 278.655 794.395 ;
        RECT 279.785 793.995 1833.870 795.855 ;
        RECT 278.615 793.775 1833.870 793.995 ;
        RECT 278.615 793.375 278.655 793.775 ;
        RECT 278.615 793.350 279.055 793.375 ;
        RECT 278.615 793.070 278.660 793.350 ;
        RECT 278.615 793.045 279.055 793.070 ;
        RECT 278.615 792.645 278.655 793.045 ;
        RECT 278.615 792.620 279.055 792.645 ;
        RECT 278.615 792.340 278.660 792.620 ;
        RECT 278.615 792.315 279.055 792.340 ;
        RECT 278.615 791.915 278.655 792.315 ;
        RECT 279.785 791.915 1833.870 793.775 ;
        RECT 278.615 771.855 1833.870 791.915 ;
        RECT 278.615 771.455 278.655 771.855 ;
        RECT 278.615 771.430 279.055 771.455 ;
        RECT 278.615 771.150 278.660 771.430 ;
        RECT 278.615 771.125 279.055 771.150 ;
        RECT 278.615 770.725 278.655 771.125 ;
        RECT 278.615 770.700 279.055 770.725 ;
        RECT 278.615 770.420 278.660 770.700 ;
        RECT 278.615 770.395 279.055 770.420 ;
        RECT 278.615 769.995 278.655 770.395 ;
        RECT 279.785 769.995 1833.870 771.855 ;
        RECT 278.615 769.775 1833.870 769.995 ;
        RECT 278.615 769.375 278.655 769.775 ;
        RECT 278.615 769.350 279.055 769.375 ;
        RECT 278.615 769.070 278.660 769.350 ;
        RECT 278.615 769.045 279.055 769.070 ;
        RECT 278.615 768.645 278.655 769.045 ;
        RECT 278.615 768.620 279.055 768.645 ;
        RECT 278.615 768.340 278.660 768.620 ;
        RECT 278.615 768.315 279.055 768.340 ;
        RECT 278.615 767.915 278.655 768.315 ;
        RECT 279.785 767.915 1833.870 769.775 ;
        RECT 278.615 747.855 1833.870 767.915 ;
        RECT 278.615 747.455 278.655 747.855 ;
        RECT 278.615 747.430 279.055 747.455 ;
        RECT 278.615 747.150 278.660 747.430 ;
        RECT 278.615 747.125 279.055 747.150 ;
        RECT 278.615 746.725 278.655 747.125 ;
        RECT 278.615 746.700 279.055 746.725 ;
        RECT 278.615 746.420 278.660 746.700 ;
        RECT 278.615 746.395 279.055 746.420 ;
        RECT 278.615 745.995 278.655 746.395 ;
        RECT 279.785 745.995 1833.870 747.855 ;
        RECT 278.615 745.775 1833.870 745.995 ;
        RECT 278.615 745.375 278.655 745.775 ;
        RECT 278.615 745.350 279.055 745.375 ;
        RECT 278.615 745.070 278.660 745.350 ;
        RECT 278.615 745.045 279.055 745.070 ;
        RECT 278.615 744.645 278.655 745.045 ;
        RECT 278.615 744.620 279.055 744.645 ;
        RECT 278.615 744.340 278.660 744.620 ;
        RECT 278.615 744.315 279.055 744.340 ;
        RECT 278.615 743.915 278.655 744.315 ;
        RECT 279.785 743.915 1833.870 745.775 ;
        RECT 278.615 723.855 1833.870 743.915 ;
        RECT 278.615 723.455 278.655 723.855 ;
        RECT 278.615 723.430 279.055 723.455 ;
        RECT 278.615 723.150 278.660 723.430 ;
        RECT 278.615 723.125 279.055 723.150 ;
        RECT 278.615 722.725 278.655 723.125 ;
        RECT 278.615 722.700 279.055 722.725 ;
        RECT 278.615 722.420 278.660 722.700 ;
        RECT 278.615 722.395 279.055 722.420 ;
        RECT 278.615 721.995 278.655 722.395 ;
        RECT 279.785 721.995 1833.870 723.855 ;
        RECT 278.615 721.775 1833.870 721.995 ;
        RECT 278.615 721.375 278.655 721.775 ;
        RECT 278.615 721.350 279.055 721.375 ;
        RECT 278.615 721.070 278.660 721.350 ;
        RECT 278.615 721.045 279.055 721.070 ;
        RECT 278.615 720.645 278.655 721.045 ;
        RECT 278.615 720.620 279.055 720.645 ;
        RECT 278.615 720.340 278.660 720.620 ;
        RECT 278.615 720.315 279.055 720.340 ;
        RECT 278.615 719.915 278.655 720.315 ;
        RECT 279.785 719.915 1833.870 721.775 ;
        RECT 278.615 699.855 1833.870 719.915 ;
        RECT 278.615 699.455 278.655 699.855 ;
        RECT 278.615 699.430 279.055 699.455 ;
        RECT 278.615 699.150 278.660 699.430 ;
        RECT 278.615 699.125 279.055 699.150 ;
        RECT 278.615 698.725 278.655 699.125 ;
        RECT 278.615 698.700 279.055 698.725 ;
        RECT 278.615 698.420 278.660 698.700 ;
        RECT 278.615 698.395 279.055 698.420 ;
        RECT 278.615 697.995 278.655 698.395 ;
        RECT 279.785 697.995 1833.870 699.855 ;
        RECT 278.615 697.775 1833.870 697.995 ;
        RECT 278.615 697.375 278.655 697.775 ;
        RECT 278.615 697.350 279.055 697.375 ;
        RECT 278.615 697.070 278.660 697.350 ;
        RECT 278.615 697.045 279.055 697.070 ;
        RECT 278.615 696.645 278.655 697.045 ;
        RECT 278.615 696.620 279.055 696.645 ;
        RECT 278.615 696.340 278.660 696.620 ;
        RECT 278.615 696.315 279.055 696.340 ;
        RECT 278.615 695.915 278.655 696.315 ;
        RECT 279.785 695.915 1833.870 697.775 ;
        RECT 278.615 675.855 1833.870 695.915 ;
        RECT 278.615 675.455 278.655 675.855 ;
        RECT 278.615 675.430 279.055 675.455 ;
        RECT 278.615 675.150 278.660 675.430 ;
        RECT 278.615 675.125 279.055 675.150 ;
        RECT 278.615 674.725 278.655 675.125 ;
        RECT 278.615 674.700 279.055 674.725 ;
        RECT 278.615 674.420 278.660 674.700 ;
        RECT 278.615 674.395 279.055 674.420 ;
        RECT 278.615 673.995 278.655 674.395 ;
        RECT 279.785 673.995 1833.870 675.855 ;
        RECT 278.615 673.775 1833.870 673.995 ;
        RECT 278.615 673.375 278.655 673.775 ;
        RECT 278.615 673.350 279.055 673.375 ;
        RECT 278.615 673.070 278.660 673.350 ;
        RECT 278.615 673.045 279.055 673.070 ;
        RECT 278.615 672.645 278.655 673.045 ;
        RECT 278.615 672.620 279.055 672.645 ;
        RECT 278.615 672.340 278.660 672.620 ;
        RECT 278.615 672.315 279.055 672.340 ;
        RECT 278.615 671.915 278.655 672.315 ;
        RECT 279.785 671.915 1833.870 673.775 ;
        RECT 278.615 651.855 1833.870 671.915 ;
        RECT 278.615 651.455 278.655 651.855 ;
        RECT 278.615 651.430 279.055 651.455 ;
        RECT 278.615 651.150 278.660 651.430 ;
        RECT 278.615 651.125 279.055 651.150 ;
        RECT 278.615 650.725 278.655 651.125 ;
        RECT 278.615 650.700 279.055 650.725 ;
        RECT 278.615 650.420 278.660 650.700 ;
        RECT 278.615 650.395 279.055 650.420 ;
        RECT 278.615 649.995 278.655 650.395 ;
        RECT 279.785 649.995 1833.870 651.855 ;
        RECT 278.615 649.775 1833.870 649.995 ;
        RECT 278.615 649.375 278.655 649.775 ;
        RECT 278.615 649.350 279.055 649.375 ;
        RECT 278.615 649.070 278.660 649.350 ;
        RECT 278.615 649.045 279.055 649.070 ;
        RECT 278.615 648.645 278.655 649.045 ;
        RECT 278.615 648.620 279.055 648.645 ;
        RECT 278.615 648.340 278.660 648.620 ;
        RECT 278.615 648.315 279.055 648.340 ;
        RECT 278.615 647.915 278.655 648.315 ;
        RECT 279.785 647.915 1833.870 649.775 ;
        RECT 278.615 627.855 1833.870 647.915 ;
        RECT 278.615 627.455 278.655 627.855 ;
        RECT 278.615 627.430 279.055 627.455 ;
        RECT 278.615 627.150 278.660 627.430 ;
        RECT 278.615 627.125 279.055 627.150 ;
        RECT 278.615 626.725 278.655 627.125 ;
        RECT 278.615 626.700 279.055 626.725 ;
        RECT 278.615 626.420 278.660 626.700 ;
        RECT 278.615 626.395 279.055 626.420 ;
        RECT 278.615 625.995 278.655 626.395 ;
        RECT 279.785 625.995 1833.870 627.855 ;
        RECT 278.615 625.775 1833.870 625.995 ;
        RECT 278.615 625.375 278.655 625.775 ;
        RECT 278.615 625.350 279.055 625.375 ;
        RECT 278.615 625.070 278.660 625.350 ;
        RECT 278.615 625.045 279.055 625.070 ;
        RECT 278.615 624.645 278.655 625.045 ;
        RECT 278.615 624.620 279.055 624.645 ;
        RECT 278.615 624.340 278.660 624.620 ;
        RECT 278.615 624.315 279.055 624.340 ;
        RECT 278.615 623.915 278.655 624.315 ;
        RECT 279.785 623.915 1833.870 625.775 ;
        RECT 278.615 603.855 1833.870 623.915 ;
        RECT 278.615 603.455 278.655 603.855 ;
        RECT 278.615 603.430 279.055 603.455 ;
        RECT 278.615 603.150 278.660 603.430 ;
        RECT 278.615 603.125 279.055 603.150 ;
        RECT 278.615 602.725 278.655 603.125 ;
        RECT 278.615 602.700 279.055 602.725 ;
        RECT 278.615 602.420 278.660 602.700 ;
        RECT 278.615 602.395 279.055 602.420 ;
        RECT 278.615 601.995 278.655 602.395 ;
        RECT 279.785 601.995 1833.870 603.855 ;
        RECT 278.615 601.775 1833.870 601.995 ;
        RECT 278.615 601.375 278.655 601.775 ;
        RECT 278.615 601.350 279.055 601.375 ;
        RECT 278.615 601.070 278.660 601.350 ;
        RECT 278.615 601.045 279.055 601.070 ;
        RECT 278.615 600.645 278.655 601.045 ;
        RECT 278.615 600.620 279.055 600.645 ;
        RECT 278.615 600.340 278.660 600.620 ;
        RECT 278.615 600.315 279.055 600.340 ;
        RECT 278.615 599.915 278.655 600.315 ;
        RECT 279.785 599.915 1833.870 601.775 ;
        RECT 278.615 579.855 1833.870 599.915 ;
        RECT 278.615 579.455 278.655 579.855 ;
        RECT 278.615 579.430 279.055 579.455 ;
        RECT 278.615 579.150 278.660 579.430 ;
        RECT 278.615 579.125 279.055 579.150 ;
        RECT 278.615 578.725 278.655 579.125 ;
        RECT 278.615 578.700 279.055 578.725 ;
        RECT 278.615 578.420 278.660 578.700 ;
        RECT 278.615 578.395 279.055 578.420 ;
        RECT 278.615 577.995 278.655 578.395 ;
        RECT 279.785 577.995 1833.870 579.855 ;
        RECT 278.615 577.775 1833.870 577.995 ;
        RECT 278.615 577.375 278.655 577.775 ;
        RECT 278.615 577.350 279.055 577.375 ;
        RECT 278.615 577.070 278.660 577.350 ;
        RECT 278.615 577.045 279.055 577.070 ;
        RECT 278.615 576.645 278.655 577.045 ;
        RECT 278.615 576.620 279.055 576.645 ;
        RECT 278.615 576.340 278.660 576.620 ;
        RECT 278.615 576.315 279.055 576.340 ;
        RECT 278.615 575.915 278.655 576.315 ;
        RECT 279.785 575.915 1833.870 577.775 ;
        RECT 278.615 555.855 1833.870 575.915 ;
        RECT 278.615 555.455 278.655 555.855 ;
        RECT 278.615 555.430 279.055 555.455 ;
        RECT 278.615 555.150 278.660 555.430 ;
        RECT 278.615 555.125 279.055 555.150 ;
        RECT 278.615 554.725 278.655 555.125 ;
        RECT 278.615 554.700 279.055 554.725 ;
        RECT 278.615 554.420 278.660 554.700 ;
        RECT 278.615 554.395 279.055 554.420 ;
        RECT 278.615 553.995 278.655 554.395 ;
        RECT 279.785 553.995 1833.870 555.855 ;
        RECT 278.615 553.775 1833.870 553.995 ;
        RECT 278.615 553.375 278.655 553.775 ;
        RECT 278.615 553.350 279.055 553.375 ;
        RECT 278.615 553.070 278.660 553.350 ;
        RECT 278.615 553.045 279.055 553.070 ;
        RECT 278.615 552.645 278.655 553.045 ;
        RECT 278.615 552.620 279.055 552.645 ;
        RECT 278.615 552.340 278.660 552.620 ;
        RECT 278.615 552.315 279.055 552.340 ;
        RECT 278.615 551.915 278.655 552.315 ;
        RECT 279.785 551.915 1833.870 553.775 ;
        RECT 278.615 531.855 1833.870 551.915 ;
        RECT 278.615 531.455 278.655 531.855 ;
        RECT 278.615 531.430 279.055 531.455 ;
        RECT 278.615 531.150 278.660 531.430 ;
        RECT 278.615 531.125 279.055 531.150 ;
        RECT 278.615 530.725 278.655 531.125 ;
        RECT 278.615 530.700 279.055 530.725 ;
        RECT 278.615 530.420 278.660 530.700 ;
        RECT 278.615 530.395 279.055 530.420 ;
        RECT 278.615 529.995 278.655 530.395 ;
        RECT 279.785 529.995 1833.870 531.855 ;
        RECT 278.615 529.775 1833.870 529.995 ;
        RECT 278.615 529.375 278.655 529.775 ;
        RECT 278.615 529.350 279.055 529.375 ;
        RECT 278.615 529.070 278.660 529.350 ;
        RECT 278.615 529.045 279.055 529.070 ;
        RECT 278.615 528.645 278.655 529.045 ;
        RECT 278.615 528.620 279.055 528.645 ;
        RECT 278.615 528.340 278.660 528.620 ;
        RECT 278.615 528.315 279.055 528.340 ;
        RECT 278.615 527.915 278.655 528.315 ;
        RECT 279.785 527.915 1833.870 529.775 ;
        RECT 278.615 507.855 1833.870 527.915 ;
        RECT 278.615 507.455 278.655 507.855 ;
        RECT 278.615 507.430 279.055 507.455 ;
        RECT 278.615 507.150 278.660 507.430 ;
        RECT 278.615 507.125 279.055 507.150 ;
        RECT 278.615 506.725 278.655 507.125 ;
        RECT 278.615 506.700 279.055 506.725 ;
        RECT 278.615 506.420 278.660 506.700 ;
        RECT 278.615 506.395 279.055 506.420 ;
        RECT 278.615 505.995 278.655 506.395 ;
        RECT 279.785 505.995 1833.870 507.855 ;
        RECT 278.615 505.775 1833.870 505.995 ;
        RECT 278.615 505.375 278.655 505.775 ;
        RECT 278.615 505.350 279.055 505.375 ;
        RECT 278.615 505.070 278.660 505.350 ;
        RECT 278.615 505.045 279.055 505.070 ;
        RECT 278.615 504.645 278.655 505.045 ;
        RECT 278.615 504.620 279.055 504.645 ;
        RECT 278.615 504.340 278.660 504.620 ;
        RECT 278.615 504.315 279.055 504.340 ;
        RECT 278.615 503.915 278.655 504.315 ;
        RECT 279.785 503.915 1833.870 505.775 ;
        RECT 278.615 483.855 1833.870 503.915 ;
        RECT 278.615 483.455 278.655 483.855 ;
        RECT 278.615 483.430 279.055 483.455 ;
        RECT 278.615 483.150 278.660 483.430 ;
        RECT 278.615 483.125 279.055 483.150 ;
        RECT 278.615 482.725 278.655 483.125 ;
        RECT 278.615 482.700 279.055 482.725 ;
        RECT 278.615 482.420 278.660 482.700 ;
        RECT 278.615 482.395 279.055 482.420 ;
        RECT 278.615 481.995 278.655 482.395 ;
        RECT 279.785 481.995 1833.870 483.855 ;
        RECT 278.615 481.775 1833.870 481.995 ;
        RECT 278.615 481.375 278.655 481.775 ;
        RECT 278.615 481.350 279.055 481.375 ;
        RECT 278.615 481.070 278.660 481.350 ;
        RECT 278.615 481.045 279.055 481.070 ;
        RECT 278.615 480.645 278.655 481.045 ;
        RECT 278.615 480.620 279.055 480.645 ;
        RECT 278.615 480.340 278.660 480.620 ;
        RECT 278.615 480.315 279.055 480.340 ;
        RECT 278.615 479.915 278.655 480.315 ;
        RECT 279.785 479.915 1833.870 481.775 ;
        RECT 278.615 459.855 1833.870 479.915 ;
        RECT 278.615 459.455 278.655 459.855 ;
        RECT 278.615 459.430 279.055 459.455 ;
        RECT 278.615 459.150 278.660 459.430 ;
        RECT 278.615 459.125 279.055 459.150 ;
        RECT 278.615 458.725 278.655 459.125 ;
        RECT 278.615 458.700 279.055 458.725 ;
        RECT 278.615 458.420 278.660 458.700 ;
        RECT 278.615 458.395 279.055 458.420 ;
        RECT 278.615 457.995 278.655 458.395 ;
        RECT 279.785 457.995 1833.870 459.855 ;
        RECT 278.615 457.775 1833.870 457.995 ;
        RECT 278.615 457.375 278.655 457.775 ;
        RECT 278.615 457.350 279.055 457.375 ;
        RECT 278.615 457.070 278.660 457.350 ;
        RECT 278.615 457.045 279.055 457.070 ;
        RECT 278.615 456.645 278.655 457.045 ;
        RECT 278.615 456.620 279.055 456.645 ;
        RECT 278.615 456.340 278.660 456.620 ;
        RECT 278.615 456.315 279.055 456.340 ;
        RECT 278.615 455.915 278.655 456.315 ;
        RECT 279.785 455.915 1833.870 457.775 ;
        RECT 278.615 435.855 1833.870 455.915 ;
        RECT 278.615 435.455 278.655 435.855 ;
        RECT 278.615 435.430 279.055 435.455 ;
        RECT 278.615 435.150 278.660 435.430 ;
        RECT 278.615 435.125 279.055 435.150 ;
        RECT 278.615 434.725 278.655 435.125 ;
        RECT 278.615 434.700 279.055 434.725 ;
        RECT 278.615 434.420 278.660 434.700 ;
        RECT 278.615 434.395 279.055 434.420 ;
        RECT 278.615 433.995 278.655 434.395 ;
        RECT 279.785 433.995 1833.870 435.855 ;
        RECT 278.615 433.775 1833.870 433.995 ;
        RECT 278.615 433.375 278.655 433.775 ;
        RECT 278.615 433.350 279.055 433.375 ;
        RECT 278.615 433.070 278.660 433.350 ;
        RECT 278.615 433.045 279.055 433.070 ;
        RECT 278.615 432.645 278.655 433.045 ;
        RECT 278.615 432.620 279.055 432.645 ;
        RECT 278.615 432.340 278.660 432.620 ;
        RECT 278.615 432.315 279.055 432.340 ;
        RECT 278.615 431.915 278.655 432.315 ;
        RECT 279.785 431.915 1833.870 433.775 ;
        RECT 278.615 411.855 1833.870 431.915 ;
        RECT 278.615 411.455 278.655 411.855 ;
        RECT 278.615 411.430 279.055 411.455 ;
        RECT 278.615 411.150 278.660 411.430 ;
        RECT 278.615 411.125 279.055 411.150 ;
        RECT 278.615 410.725 278.655 411.125 ;
        RECT 278.615 410.700 279.055 410.725 ;
        RECT 278.615 410.420 278.660 410.700 ;
        RECT 278.615 410.395 279.055 410.420 ;
        RECT 278.615 409.995 278.655 410.395 ;
        RECT 279.785 409.995 1833.870 411.855 ;
        RECT 278.615 409.775 1833.870 409.995 ;
        RECT 278.615 409.375 278.655 409.775 ;
        RECT 278.615 409.350 279.055 409.375 ;
        RECT 278.615 409.070 278.660 409.350 ;
        RECT 278.615 409.045 279.055 409.070 ;
        RECT 278.615 408.645 278.655 409.045 ;
        RECT 278.615 408.620 279.055 408.645 ;
        RECT 278.615 408.340 278.660 408.620 ;
        RECT 278.615 408.315 279.055 408.340 ;
        RECT 278.615 407.915 278.655 408.315 ;
        RECT 279.785 407.915 1833.870 409.775 ;
        RECT 278.615 387.855 1833.870 407.915 ;
        RECT 278.615 387.455 278.655 387.855 ;
        RECT 278.615 387.430 279.055 387.455 ;
        RECT 278.615 387.150 278.660 387.430 ;
        RECT 278.615 387.125 279.055 387.150 ;
        RECT 278.615 386.725 278.655 387.125 ;
        RECT 278.615 386.700 279.055 386.725 ;
        RECT 278.615 386.420 278.660 386.700 ;
        RECT 278.615 386.395 279.055 386.420 ;
        RECT 278.615 385.995 278.655 386.395 ;
        RECT 279.785 385.995 1833.870 387.855 ;
        RECT 278.615 385.775 1833.870 385.995 ;
        RECT 278.615 385.375 278.655 385.775 ;
        RECT 278.615 385.350 279.055 385.375 ;
        RECT 278.615 385.070 278.660 385.350 ;
        RECT 278.615 385.045 279.055 385.070 ;
        RECT 278.615 384.645 278.655 385.045 ;
        RECT 278.615 384.620 279.055 384.645 ;
        RECT 278.615 384.340 278.660 384.620 ;
        RECT 278.615 384.315 279.055 384.340 ;
        RECT 278.615 383.915 278.655 384.315 ;
        RECT 279.785 383.915 1833.870 385.775 ;
        RECT 278.615 363.855 1833.870 383.915 ;
        RECT 278.615 363.455 278.655 363.855 ;
        RECT 278.615 363.430 279.055 363.455 ;
        RECT 278.615 363.150 278.660 363.430 ;
        RECT 278.615 363.125 279.055 363.150 ;
        RECT 278.615 362.725 278.655 363.125 ;
        RECT 278.615 362.700 279.055 362.725 ;
        RECT 278.615 362.420 278.660 362.700 ;
        RECT 278.615 362.395 279.055 362.420 ;
        RECT 278.615 361.995 278.655 362.395 ;
        RECT 279.785 361.995 1833.870 363.855 ;
        RECT 278.615 361.775 1833.870 361.995 ;
        RECT 278.615 361.375 278.655 361.775 ;
        RECT 278.615 361.350 279.055 361.375 ;
        RECT 278.615 361.070 278.660 361.350 ;
        RECT 278.615 361.045 279.055 361.070 ;
        RECT 278.615 360.645 278.655 361.045 ;
        RECT 278.615 360.620 279.055 360.645 ;
        RECT 278.615 360.340 278.660 360.620 ;
        RECT 278.615 360.315 279.055 360.340 ;
        RECT 278.615 359.915 278.655 360.315 ;
        RECT 279.785 359.915 1833.870 361.775 ;
        RECT 278.615 339.855 1833.870 359.915 ;
        RECT 278.615 339.455 278.655 339.855 ;
        RECT 278.615 339.430 279.055 339.455 ;
        RECT 278.615 339.150 278.660 339.430 ;
        RECT 278.615 339.125 279.055 339.150 ;
        RECT 278.615 338.725 278.655 339.125 ;
        RECT 278.615 338.700 279.055 338.725 ;
        RECT 278.615 338.420 278.660 338.700 ;
        RECT 278.615 338.395 279.055 338.420 ;
        RECT 278.615 337.995 278.655 338.395 ;
        RECT 279.785 337.995 1833.870 339.855 ;
        RECT 278.615 337.775 1833.870 337.995 ;
        RECT 278.615 337.375 278.655 337.775 ;
        RECT 278.615 337.350 279.055 337.375 ;
        RECT 278.615 337.070 278.660 337.350 ;
        RECT 278.615 337.045 279.055 337.070 ;
        RECT 278.615 336.645 278.655 337.045 ;
        RECT 278.615 336.620 279.055 336.645 ;
        RECT 278.615 336.340 278.660 336.620 ;
        RECT 278.615 336.315 279.055 336.340 ;
        RECT 278.615 335.915 278.655 336.315 ;
        RECT 279.785 335.915 1833.870 337.775 ;
        RECT 278.615 315.855 1833.870 335.915 ;
        RECT 278.615 315.455 278.655 315.855 ;
        RECT 278.615 315.430 279.055 315.455 ;
        RECT 278.615 315.150 278.660 315.430 ;
        RECT 278.615 315.125 279.055 315.150 ;
        RECT 278.615 314.725 278.655 315.125 ;
        RECT 278.615 314.700 279.055 314.725 ;
        RECT 278.615 314.420 278.660 314.700 ;
        RECT 278.615 314.395 279.055 314.420 ;
        RECT 278.615 313.995 278.655 314.395 ;
        RECT 279.785 313.995 1833.870 315.855 ;
        RECT 278.615 313.775 1833.870 313.995 ;
        RECT 278.615 313.375 278.655 313.775 ;
        RECT 278.615 313.350 279.055 313.375 ;
        RECT 278.615 313.070 278.660 313.350 ;
        RECT 278.615 313.045 279.055 313.070 ;
        RECT 278.615 312.645 278.655 313.045 ;
        RECT 278.615 312.620 279.055 312.645 ;
        RECT 278.615 312.340 278.660 312.620 ;
        RECT 278.615 312.315 279.055 312.340 ;
        RECT 278.615 311.915 278.655 312.315 ;
        RECT 279.785 311.915 1833.870 313.775 ;
        RECT 278.615 291.855 1833.870 311.915 ;
        RECT 278.615 291.455 278.655 291.855 ;
        RECT 278.615 291.430 279.055 291.455 ;
        RECT 278.615 291.150 278.660 291.430 ;
        RECT 278.615 291.125 279.055 291.150 ;
        RECT 278.615 290.725 278.655 291.125 ;
        RECT 278.615 290.700 279.055 290.725 ;
        RECT 278.615 290.420 278.660 290.700 ;
        RECT 278.615 290.395 279.055 290.420 ;
        RECT 278.615 289.995 278.655 290.395 ;
        RECT 279.785 289.995 1833.870 291.855 ;
        RECT 278.615 289.775 1833.870 289.995 ;
        RECT 278.615 289.375 278.655 289.775 ;
        RECT 278.615 289.350 279.055 289.375 ;
        RECT 278.615 289.070 278.660 289.350 ;
        RECT 278.615 289.045 279.055 289.070 ;
        RECT 278.615 288.645 278.655 289.045 ;
        RECT 278.615 288.620 279.055 288.645 ;
        RECT 278.615 288.340 278.660 288.620 ;
        RECT 278.615 288.315 279.055 288.340 ;
        RECT 278.615 287.915 278.655 288.315 ;
        RECT 279.785 287.915 1833.870 289.775 ;
        RECT 278.615 267.855 1833.870 287.915 ;
        RECT 278.615 267.455 278.655 267.855 ;
        RECT 278.615 267.430 279.055 267.455 ;
        RECT 278.615 267.150 278.660 267.430 ;
        RECT 278.615 267.125 279.055 267.150 ;
        RECT 278.615 266.725 278.655 267.125 ;
        RECT 278.615 266.700 279.055 266.725 ;
        RECT 278.615 266.420 278.660 266.700 ;
        RECT 278.615 266.395 279.055 266.420 ;
        RECT 278.615 265.995 278.655 266.395 ;
        RECT 279.785 265.995 1833.870 267.855 ;
        RECT 278.615 265.775 1833.870 265.995 ;
        RECT 278.615 265.375 278.655 265.775 ;
        RECT 278.615 265.350 279.055 265.375 ;
        RECT 278.615 265.070 278.660 265.350 ;
        RECT 278.615 265.045 279.055 265.070 ;
        RECT 278.615 264.645 278.655 265.045 ;
        RECT 278.615 264.620 279.055 264.645 ;
        RECT 278.615 264.340 278.660 264.620 ;
        RECT 278.615 264.315 279.055 264.340 ;
        RECT 278.615 263.915 278.655 264.315 ;
        RECT 279.785 263.915 1833.870 265.775 ;
        RECT 278.615 243.855 1833.870 263.915 ;
        RECT 278.615 243.455 278.655 243.855 ;
        RECT 278.615 243.430 279.055 243.455 ;
        RECT 278.615 243.150 278.660 243.430 ;
        RECT 278.615 243.125 279.055 243.150 ;
        RECT 278.615 242.725 278.655 243.125 ;
        RECT 278.615 242.700 279.055 242.725 ;
        RECT 278.615 242.420 278.660 242.700 ;
        RECT 278.615 242.395 279.055 242.420 ;
        RECT 278.615 241.995 278.655 242.395 ;
        RECT 279.785 241.995 1833.870 243.855 ;
        RECT 278.615 241.775 1833.870 241.995 ;
        RECT 278.615 241.375 278.655 241.775 ;
        RECT 278.615 241.350 279.055 241.375 ;
        RECT 278.615 241.070 278.660 241.350 ;
        RECT 278.615 241.045 279.055 241.070 ;
        RECT 278.615 240.645 278.655 241.045 ;
        RECT 278.615 240.620 279.055 240.645 ;
        RECT 278.615 240.340 278.660 240.620 ;
        RECT 278.615 240.315 279.055 240.340 ;
        RECT 278.615 239.915 278.655 240.315 ;
        RECT 279.785 239.915 1833.870 241.775 ;
        RECT 278.615 219.855 1833.870 239.915 ;
        RECT 278.615 219.455 278.655 219.855 ;
        RECT 278.615 219.430 279.055 219.455 ;
        RECT 278.615 219.150 278.660 219.430 ;
        RECT 278.615 219.125 279.055 219.150 ;
        RECT 278.615 218.725 278.655 219.125 ;
        RECT 278.615 218.700 279.055 218.725 ;
        RECT 278.615 218.420 278.660 218.700 ;
        RECT 278.615 218.395 279.055 218.420 ;
        RECT 278.615 217.995 278.655 218.395 ;
        RECT 279.785 217.995 1833.870 219.855 ;
        RECT 278.615 217.775 1833.870 217.995 ;
        RECT 278.615 217.375 278.655 217.775 ;
        RECT 278.615 217.350 279.055 217.375 ;
        RECT 278.615 217.070 278.660 217.350 ;
        RECT 278.615 217.045 279.055 217.070 ;
        RECT 278.615 216.645 278.655 217.045 ;
        RECT 278.615 216.620 279.055 216.645 ;
        RECT 278.615 216.340 278.660 216.620 ;
        RECT 278.615 216.315 279.055 216.340 ;
        RECT 278.615 215.915 278.655 216.315 ;
        RECT 279.785 215.915 1833.870 217.775 ;
        RECT 278.615 195.855 1833.870 215.915 ;
        RECT 278.615 195.455 278.655 195.855 ;
        RECT 278.615 195.430 279.055 195.455 ;
        RECT 278.615 195.150 278.660 195.430 ;
        RECT 278.615 195.125 279.055 195.150 ;
        RECT 278.615 194.725 278.655 195.125 ;
        RECT 278.615 194.700 279.055 194.725 ;
        RECT 278.615 194.420 278.660 194.700 ;
        RECT 278.615 194.395 279.055 194.420 ;
        RECT 278.615 193.995 278.655 194.395 ;
        RECT 279.785 193.995 1833.870 195.855 ;
        RECT 278.615 193.775 1833.870 193.995 ;
        RECT 278.615 193.375 278.655 193.775 ;
        RECT 278.615 193.350 279.055 193.375 ;
        RECT 278.615 193.070 278.660 193.350 ;
        RECT 278.615 193.045 279.055 193.070 ;
        RECT 278.615 192.645 278.655 193.045 ;
        RECT 278.615 192.620 279.055 192.645 ;
        RECT 278.615 192.340 278.660 192.620 ;
        RECT 278.615 192.315 279.055 192.340 ;
        RECT 278.615 191.915 278.655 192.315 ;
        RECT 279.785 191.915 1833.870 193.775 ;
        RECT 278.615 171.855 1833.870 191.915 ;
        RECT 278.615 171.455 278.655 171.855 ;
        RECT 278.615 171.430 279.055 171.455 ;
        RECT 278.615 171.150 278.660 171.430 ;
        RECT 278.615 171.125 279.055 171.150 ;
        RECT 278.615 170.725 278.655 171.125 ;
        RECT 278.615 170.700 279.055 170.725 ;
        RECT 278.615 170.420 278.660 170.700 ;
        RECT 278.615 170.395 279.055 170.420 ;
        RECT 278.615 169.995 278.655 170.395 ;
        RECT 279.785 169.995 1833.870 171.855 ;
        RECT 278.615 169.775 1833.870 169.995 ;
        RECT 278.615 169.375 278.655 169.775 ;
        RECT 278.615 169.350 279.055 169.375 ;
        RECT 278.615 169.070 278.660 169.350 ;
        RECT 278.615 169.045 279.055 169.070 ;
        RECT 278.615 168.645 278.655 169.045 ;
        RECT 278.615 168.620 279.055 168.645 ;
        RECT 278.615 168.340 278.660 168.620 ;
        RECT 278.615 168.315 279.055 168.340 ;
        RECT 278.615 167.915 278.655 168.315 ;
        RECT 279.785 167.915 1833.870 169.775 ;
        RECT 278.615 147.855 1833.870 167.915 ;
        RECT 278.615 147.455 278.655 147.855 ;
        RECT 278.615 147.430 279.055 147.455 ;
        RECT 278.615 147.150 278.660 147.430 ;
        RECT 278.615 147.125 279.055 147.150 ;
        RECT 278.615 146.725 278.655 147.125 ;
        RECT 278.615 146.700 279.055 146.725 ;
        RECT 278.615 146.420 278.660 146.700 ;
        RECT 278.615 146.395 279.055 146.420 ;
        RECT 278.615 145.995 278.655 146.395 ;
        RECT 279.785 145.995 1833.870 147.855 ;
        RECT 278.615 145.775 1833.870 145.995 ;
        RECT 278.615 145.375 278.655 145.775 ;
        RECT 278.615 145.350 279.055 145.375 ;
        RECT 278.615 145.070 278.660 145.350 ;
        RECT 278.615 145.045 279.055 145.070 ;
        RECT 278.615 144.645 278.655 145.045 ;
        RECT 278.615 144.620 279.055 144.645 ;
        RECT 278.615 144.340 278.660 144.620 ;
        RECT 278.615 144.315 279.055 144.340 ;
        RECT 278.615 143.915 278.655 144.315 ;
        RECT 279.785 143.915 1833.870 145.775 ;
        RECT 278.615 123.855 1833.870 143.915 ;
        RECT 278.615 123.455 278.655 123.855 ;
        RECT 278.615 123.430 279.055 123.455 ;
        RECT 278.615 123.150 278.660 123.430 ;
        RECT 278.615 123.125 279.055 123.150 ;
        RECT 278.615 122.725 278.655 123.125 ;
        RECT 278.615 122.700 279.055 122.725 ;
        RECT 278.615 122.420 278.660 122.700 ;
        RECT 278.615 122.395 279.055 122.420 ;
        RECT 278.615 121.995 278.655 122.395 ;
        RECT 279.785 121.995 1833.870 123.855 ;
        RECT 278.615 121.775 1833.870 121.995 ;
        RECT 278.615 121.375 278.655 121.775 ;
        RECT 278.615 121.350 279.055 121.375 ;
        RECT 278.615 121.070 278.660 121.350 ;
        RECT 278.615 121.045 279.055 121.070 ;
        RECT 278.615 120.645 278.655 121.045 ;
        RECT 278.615 120.620 279.055 120.645 ;
        RECT 278.615 120.340 278.660 120.620 ;
        RECT 278.615 120.315 279.055 120.340 ;
        RECT 278.615 119.915 278.655 120.315 ;
        RECT 279.785 119.915 1833.870 121.775 ;
        RECT 278.615 115.285 1833.870 119.915 ;
        RECT 278.615 104.485 1832.480 115.285 ;
        RECT 1833.780 104.485 1833.870 115.285 ;
        RECT 278.615 99.855 1833.870 104.485 ;
        RECT 278.615 99.455 278.655 99.855 ;
        RECT 278.615 99.430 279.055 99.455 ;
        RECT 278.615 99.150 278.660 99.430 ;
        RECT 278.615 99.125 279.055 99.150 ;
        RECT 278.615 98.725 278.655 99.125 ;
        RECT 278.615 98.700 279.055 98.725 ;
        RECT 278.615 98.420 278.660 98.700 ;
        RECT 278.615 98.395 279.055 98.420 ;
        RECT 278.615 97.995 278.655 98.395 ;
        RECT 279.785 97.995 1833.870 99.855 ;
        RECT 278.615 97.775 1833.870 97.995 ;
        RECT 278.615 97.375 278.655 97.775 ;
        RECT 278.615 97.350 279.055 97.375 ;
        RECT 278.615 97.070 278.660 97.350 ;
        RECT 278.615 97.045 279.055 97.070 ;
        RECT 278.615 96.645 278.655 97.045 ;
        RECT 278.615 96.620 279.055 96.645 ;
        RECT 278.615 96.340 278.660 96.620 ;
        RECT 278.615 96.315 279.055 96.340 ;
        RECT 278.615 95.915 278.655 96.315 ;
        RECT 279.785 95.915 1833.870 97.775 ;
        RECT 278.615 75.855 1833.870 95.915 ;
        RECT 278.615 75.455 278.655 75.855 ;
        RECT 278.615 75.430 279.055 75.455 ;
        RECT 278.615 75.150 278.660 75.430 ;
        RECT 278.615 75.125 279.055 75.150 ;
        RECT 278.615 74.725 278.655 75.125 ;
        RECT 278.615 74.700 279.055 74.725 ;
        RECT 278.615 74.420 278.660 74.700 ;
        RECT 278.615 74.395 279.055 74.420 ;
        RECT 278.615 73.995 278.655 74.395 ;
        RECT 279.785 73.995 1833.870 75.855 ;
        RECT 278.615 73.775 1833.870 73.995 ;
        RECT 278.615 73.375 278.655 73.775 ;
        RECT 278.615 73.350 279.055 73.375 ;
        RECT 278.615 73.070 278.660 73.350 ;
        RECT 278.615 73.045 279.055 73.070 ;
        RECT 278.615 72.645 278.655 73.045 ;
        RECT 278.615 72.620 279.055 72.645 ;
        RECT 278.615 72.340 278.660 72.620 ;
        RECT 278.615 72.315 279.055 72.340 ;
        RECT 278.615 71.915 278.655 72.315 ;
        RECT 279.785 71.915 1833.870 73.775 ;
        RECT 278.615 51.855 1833.870 71.915 ;
        RECT 278.615 51.455 278.655 51.855 ;
        RECT 278.615 51.430 279.055 51.455 ;
        RECT 278.615 51.150 278.660 51.430 ;
        RECT 278.615 51.125 279.055 51.150 ;
        RECT 278.615 50.725 278.655 51.125 ;
        RECT 278.615 50.700 279.055 50.725 ;
        RECT 278.615 50.420 278.660 50.700 ;
        RECT 278.615 50.395 279.055 50.420 ;
        RECT 278.615 49.995 278.655 50.395 ;
        RECT 279.785 49.995 1833.870 51.855 ;
        RECT 278.615 49.775 1833.870 49.995 ;
        RECT 278.615 49.375 278.655 49.775 ;
        RECT 278.615 49.350 279.055 49.375 ;
        RECT 278.615 49.070 278.660 49.350 ;
        RECT 278.615 49.045 279.055 49.070 ;
        RECT 278.615 48.645 278.655 49.045 ;
        RECT 278.615 48.620 279.055 48.645 ;
        RECT 278.615 48.340 278.660 48.620 ;
        RECT 278.615 48.315 279.055 48.340 ;
        RECT 278.615 47.915 278.655 48.315 ;
        RECT 279.785 47.915 1833.870 49.775 ;
        RECT 278.615 27.855 1833.870 47.915 ;
        RECT 278.615 27.455 278.655 27.855 ;
        RECT 278.615 27.430 279.055 27.455 ;
        RECT 278.615 27.150 278.660 27.430 ;
        RECT 278.615 27.125 279.055 27.150 ;
        RECT 278.615 26.725 278.655 27.125 ;
        RECT 278.615 26.700 279.055 26.725 ;
        RECT 278.615 26.420 278.660 26.700 ;
        RECT 278.615 26.395 279.055 26.420 ;
        RECT 278.615 25.995 278.655 26.395 ;
        RECT 279.785 25.995 1833.870 27.855 ;
        RECT 278.615 25.775 1833.870 25.995 ;
        RECT 278.615 25.375 278.655 25.775 ;
        RECT 278.615 25.350 279.055 25.375 ;
        RECT 278.615 25.070 278.660 25.350 ;
        RECT 278.615 25.045 279.055 25.070 ;
        RECT 278.615 24.645 278.655 25.045 ;
        RECT 278.615 24.620 279.055 24.645 ;
        RECT 278.615 24.340 278.660 24.620 ;
        RECT 278.615 24.315 279.055 24.340 ;
        RECT 278.615 23.915 278.655 24.315 ;
        RECT 279.785 23.915 1833.870 25.775 ;
        RECT 278.615 3.855 1833.870 23.915 ;
        RECT 278.615 3.455 278.655 3.855 ;
        RECT 278.615 3.430 279.055 3.455 ;
        RECT 278.615 3.150 278.660 3.430 ;
        RECT 278.615 3.125 279.055 3.150 ;
        RECT 278.615 2.725 278.655 3.125 ;
        RECT 278.615 2.700 279.055 2.725 ;
        RECT 278.615 2.420 278.660 2.700 ;
        RECT 278.615 2.395 279.055 2.420 ;
        RECT 278.615 1.995 278.655 2.395 ;
        RECT 279.785 1.995 1833.870 3.855 ;
        RECT 278.615 1.775 1833.870 1.995 ;
        RECT 278.615 1.375 278.655 1.775 ;
        RECT 278.615 1.350 279.055 1.375 ;
        RECT 278.615 1.070 278.660 1.350 ;
        RECT 278.615 1.045 279.055 1.070 ;
        RECT 278.615 0.645 278.655 1.045 ;
        RECT 278.615 0.620 279.055 0.645 ;
        RECT 278.615 0.340 278.660 0.620 ;
        RECT 278.615 0.315 279.055 0.340 ;
        RECT 278.615 -0.085 278.655 0.315 ;
        RECT 279.785 -0.085 1833.870 1.775 ;
        RECT 278.615 -20.145 1833.870 -0.085 ;
        RECT 278.615 -20.545 278.655 -20.145 ;
        RECT 278.615 -20.570 279.055 -20.545 ;
        RECT 278.615 -20.850 278.660 -20.570 ;
        RECT 278.615 -20.875 279.055 -20.850 ;
        RECT 278.615 -21.275 278.655 -20.875 ;
        RECT 278.615 -21.300 279.055 -21.275 ;
        RECT 278.615 -21.580 278.660 -21.300 ;
        RECT 278.615 -21.605 279.055 -21.580 ;
        RECT 278.615 -22.005 278.655 -21.605 ;
        RECT 279.785 -22.005 1833.870 -20.145 ;
        RECT 278.615 -22.225 1833.870 -22.005 ;
        RECT 278.615 -22.625 278.655 -22.225 ;
        RECT 278.615 -22.650 279.055 -22.625 ;
        RECT 278.615 -22.930 278.660 -22.650 ;
        RECT 278.615 -22.955 279.055 -22.930 ;
        RECT 278.615 -23.355 278.655 -22.955 ;
        RECT 278.615 -23.380 279.055 -23.355 ;
        RECT 278.615 -23.660 278.660 -23.380 ;
        RECT 278.615 -23.685 279.055 -23.660 ;
        RECT 278.615 -24.085 278.655 -23.685 ;
        RECT 279.785 -24.085 1833.870 -22.225 ;
        RECT 278.615 -44.145 1833.870 -24.085 ;
        RECT 278.615 -44.545 278.655 -44.145 ;
        RECT 278.615 -44.570 279.055 -44.545 ;
        RECT 278.615 -44.850 278.660 -44.570 ;
        RECT 278.615 -44.875 279.055 -44.850 ;
        RECT 278.615 -45.275 278.655 -44.875 ;
        RECT 278.615 -45.300 279.055 -45.275 ;
        RECT 278.615 -45.580 278.660 -45.300 ;
        RECT 278.615 -45.605 279.055 -45.580 ;
        RECT 278.615 -46.005 278.655 -45.605 ;
        RECT 279.785 -46.005 1833.870 -44.145 ;
        RECT 278.615 -46.225 1833.870 -46.005 ;
        RECT 278.615 -46.625 278.655 -46.225 ;
        RECT 278.615 -46.650 279.055 -46.625 ;
        RECT 278.615 -46.930 278.660 -46.650 ;
        RECT 278.615 -46.955 279.055 -46.930 ;
        RECT 278.615 -47.355 278.655 -46.955 ;
        RECT 278.615 -47.380 279.055 -47.355 ;
        RECT 278.615 -47.660 278.660 -47.380 ;
        RECT 278.615 -47.685 279.055 -47.660 ;
        RECT 278.615 -48.085 278.655 -47.685 ;
        RECT 279.785 -48.085 1833.870 -46.225 ;
        RECT 278.615 -68.145 1833.870 -48.085 ;
        RECT 278.615 -68.545 278.655 -68.145 ;
        RECT 278.615 -68.570 279.055 -68.545 ;
        RECT 278.615 -68.850 278.660 -68.570 ;
        RECT 278.615 -68.875 279.055 -68.850 ;
        RECT 278.615 -69.275 278.655 -68.875 ;
        RECT 278.615 -69.300 279.055 -69.275 ;
        RECT 278.615 -69.580 278.660 -69.300 ;
        RECT 278.615 -69.605 279.055 -69.580 ;
        RECT 278.615 -70.005 278.655 -69.605 ;
        RECT 279.785 -70.005 1833.870 -68.145 ;
        RECT 278.615 -70.225 1833.870 -70.005 ;
        RECT 278.615 -70.625 278.655 -70.225 ;
        RECT 278.615 -70.650 279.055 -70.625 ;
        RECT 278.615 -70.930 278.660 -70.650 ;
        RECT 278.615 -70.955 279.055 -70.930 ;
        RECT 278.615 -71.355 278.655 -70.955 ;
        RECT 278.615 -71.380 279.055 -71.355 ;
        RECT 278.615 -71.660 278.660 -71.380 ;
        RECT 278.615 -71.685 279.055 -71.660 ;
        RECT 278.615 -72.085 278.655 -71.685 ;
        RECT 279.785 -72.085 1833.870 -70.225 ;
        RECT 278.615 -92.145 1833.870 -72.085 ;
        RECT 278.615 -92.545 278.655 -92.145 ;
        RECT 278.615 -92.570 279.055 -92.545 ;
        RECT 278.615 -92.850 278.660 -92.570 ;
        RECT 278.615 -92.875 279.055 -92.850 ;
        RECT 278.615 -93.275 278.655 -92.875 ;
        RECT 278.615 -93.300 279.055 -93.275 ;
        RECT 278.615 -93.580 278.660 -93.300 ;
        RECT 278.615 -93.605 279.055 -93.580 ;
        RECT 278.615 -94.005 278.655 -93.605 ;
        RECT 279.785 -94.005 1833.870 -92.145 ;
        RECT 278.615 -94.225 1833.870 -94.005 ;
        RECT 278.615 -94.625 278.655 -94.225 ;
        RECT 278.615 -94.650 279.055 -94.625 ;
        RECT 278.615 -94.930 278.660 -94.650 ;
        RECT 278.615 -94.955 279.055 -94.930 ;
        RECT 278.615 -95.355 278.655 -94.955 ;
        RECT 278.615 -95.380 279.055 -95.355 ;
        RECT 278.615 -95.660 278.660 -95.380 ;
        RECT 278.615 -95.685 279.055 -95.660 ;
        RECT 278.615 -96.085 278.655 -95.685 ;
        RECT 279.785 -96.085 1833.870 -94.225 ;
        RECT 278.615 -116.145 1833.870 -96.085 ;
        RECT 278.615 -116.545 278.655 -116.145 ;
        RECT 278.615 -116.570 279.055 -116.545 ;
        RECT 278.615 -116.850 278.660 -116.570 ;
        RECT 278.615 -116.875 279.055 -116.850 ;
        RECT 278.615 -117.275 278.655 -116.875 ;
        RECT 278.615 -117.300 279.055 -117.275 ;
        RECT 278.615 -117.580 278.660 -117.300 ;
        RECT 278.615 -117.605 279.055 -117.580 ;
        RECT 278.615 -118.005 278.655 -117.605 ;
        RECT 279.785 -118.005 1833.870 -116.145 ;
        RECT 278.615 -118.225 1833.870 -118.005 ;
        RECT 278.615 -118.625 278.655 -118.225 ;
        RECT 278.615 -118.650 279.055 -118.625 ;
        RECT 278.615 -118.930 278.660 -118.650 ;
        RECT 278.615 -118.955 279.055 -118.930 ;
        RECT 278.615 -119.355 278.655 -118.955 ;
        RECT 278.615 -119.380 279.055 -119.355 ;
        RECT 278.615 -119.660 278.660 -119.380 ;
        RECT 278.615 -119.685 279.055 -119.660 ;
        RECT 278.615 -120.085 278.655 -119.685 ;
        RECT 279.785 -120.085 1833.870 -118.225 ;
        RECT 278.615 -140.145 1833.870 -120.085 ;
        RECT 278.615 -140.545 278.655 -140.145 ;
        RECT 278.615 -140.570 279.055 -140.545 ;
        RECT 278.615 -140.850 278.660 -140.570 ;
        RECT 278.615 -140.875 279.055 -140.850 ;
        RECT 278.615 -141.275 278.655 -140.875 ;
        RECT 278.615 -141.300 279.055 -141.275 ;
        RECT 278.615 -141.580 278.660 -141.300 ;
        RECT 278.615 -141.605 279.055 -141.580 ;
        RECT 278.615 -142.005 278.655 -141.605 ;
        RECT 279.785 -142.005 1833.870 -140.145 ;
        RECT 278.615 -142.225 1833.870 -142.005 ;
        RECT 278.615 -142.625 278.655 -142.225 ;
        RECT 278.615 -142.650 279.055 -142.625 ;
        RECT 278.615 -142.930 278.660 -142.650 ;
        RECT 278.615 -142.955 279.055 -142.930 ;
        RECT 278.615 -143.355 278.655 -142.955 ;
        RECT 278.615 -143.380 279.055 -143.355 ;
        RECT 278.615 -143.660 278.660 -143.380 ;
        RECT 278.615 -143.685 279.055 -143.660 ;
        RECT 278.615 -144.085 278.655 -143.685 ;
        RECT 279.785 -144.085 1833.870 -142.225 ;
        RECT 278.615 -164.145 1833.870 -144.085 ;
        RECT 278.615 -164.545 278.655 -164.145 ;
        RECT 278.615 -164.570 279.055 -164.545 ;
        RECT 278.615 -164.850 278.660 -164.570 ;
        RECT 278.615 -164.875 279.055 -164.850 ;
        RECT 278.615 -165.275 278.655 -164.875 ;
        RECT 278.615 -165.300 279.055 -165.275 ;
        RECT 278.615 -165.580 278.660 -165.300 ;
        RECT 278.615 -165.605 279.055 -165.580 ;
        RECT 278.615 -166.005 278.655 -165.605 ;
        RECT 279.785 -166.005 1833.870 -164.145 ;
        RECT 278.615 -166.225 1833.870 -166.005 ;
        RECT 278.615 -166.625 278.655 -166.225 ;
        RECT 278.615 -166.650 279.055 -166.625 ;
        RECT 278.615 -166.930 278.660 -166.650 ;
        RECT 278.615 -166.955 279.055 -166.930 ;
        RECT 278.615 -167.355 278.655 -166.955 ;
        RECT 278.615 -167.380 279.055 -167.355 ;
        RECT 278.615 -167.660 278.660 -167.380 ;
        RECT 278.615 -167.685 279.055 -167.660 ;
        RECT 278.615 -168.085 278.655 -167.685 ;
        RECT 279.785 -168.085 1833.870 -166.225 ;
        RECT 278.615 -188.145 1833.870 -168.085 ;
        RECT 278.615 -188.545 278.655 -188.145 ;
        RECT 278.615 -188.570 279.055 -188.545 ;
        RECT 278.615 -188.850 278.660 -188.570 ;
        RECT 278.615 -188.875 279.055 -188.850 ;
        RECT 278.615 -189.275 278.655 -188.875 ;
        RECT 278.615 -189.300 279.055 -189.275 ;
        RECT 278.615 -189.580 278.660 -189.300 ;
        RECT 278.615 -189.605 279.055 -189.580 ;
        RECT 278.615 -190.005 278.655 -189.605 ;
        RECT 279.785 -190.005 1833.870 -188.145 ;
        RECT 278.615 -190.225 1833.870 -190.005 ;
        RECT 278.615 -190.625 278.655 -190.225 ;
        RECT 278.615 -190.650 279.055 -190.625 ;
        RECT 278.615 -190.930 278.660 -190.650 ;
        RECT 278.615 -190.955 279.055 -190.930 ;
        RECT 278.615 -191.355 278.655 -190.955 ;
        RECT 278.615 -191.380 279.055 -191.355 ;
        RECT 278.615 -191.660 278.660 -191.380 ;
        RECT 278.615 -191.685 279.055 -191.660 ;
        RECT 278.615 -192.085 278.655 -191.685 ;
        RECT 279.785 -192.085 1833.870 -190.225 ;
        RECT 278.615 -212.145 1833.870 -192.085 ;
        RECT 278.615 -212.545 278.655 -212.145 ;
        RECT 278.615 -212.570 279.055 -212.545 ;
        RECT 278.615 -212.850 278.660 -212.570 ;
        RECT 278.615 -212.875 279.055 -212.850 ;
        RECT 278.615 -213.275 278.655 -212.875 ;
        RECT 278.615 -213.300 279.055 -213.275 ;
        RECT 278.615 -213.580 278.660 -213.300 ;
        RECT 278.615 -213.605 279.055 -213.580 ;
        RECT 278.615 -214.005 278.655 -213.605 ;
        RECT 279.785 -214.005 1833.870 -212.145 ;
        RECT 278.615 -214.225 1833.870 -214.005 ;
        RECT 278.615 -214.625 278.655 -214.225 ;
        RECT 278.615 -214.650 279.055 -214.625 ;
        RECT 278.615 -214.930 278.660 -214.650 ;
        RECT 278.615 -214.955 279.055 -214.930 ;
        RECT 278.615 -215.355 278.655 -214.955 ;
        RECT 278.615 -215.380 279.055 -215.355 ;
        RECT 278.615 -215.660 278.660 -215.380 ;
        RECT 278.615 -215.685 279.055 -215.660 ;
        RECT 278.615 -216.085 278.655 -215.685 ;
        RECT 279.785 -216.085 1833.870 -214.225 ;
        RECT 278.615 -236.145 1833.870 -216.085 ;
        RECT 278.615 -236.545 278.655 -236.145 ;
        RECT 278.615 -236.570 279.055 -236.545 ;
        RECT 278.615 -236.850 278.660 -236.570 ;
        RECT 278.615 -236.875 279.055 -236.850 ;
        RECT 278.615 -237.275 278.655 -236.875 ;
        RECT 278.615 -237.300 279.055 -237.275 ;
        RECT 278.615 -237.580 278.660 -237.300 ;
        RECT 278.615 -237.605 279.055 -237.580 ;
        RECT 278.615 -238.005 278.655 -237.605 ;
        RECT 279.785 -238.005 1833.870 -236.145 ;
        RECT 278.615 -238.225 1833.870 -238.005 ;
        RECT 278.615 -238.625 278.655 -238.225 ;
        RECT 278.615 -238.650 279.055 -238.625 ;
        RECT 278.615 -238.930 278.660 -238.650 ;
        RECT 278.615 -238.955 279.055 -238.930 ;
        RECT 278.615 -239.355 278.655 -238.955 ;
        RECT 278.615 -239.380 279.055 -239.355 ;
        RECT 278.615 -239.660 278.660 -239.380 ;
        RECT 278.615 -239.685 279.055 -239.660 ;
        RECT 278.615 -240.085 278.655 -239.685 ;
        RECT 279.785 -240.085 1833.870 -238.225 ;
        RECT 278.615 -260.145 1833.870 -240.085 ;
        RECT 278.615 -260.545 278.655 -260.145 ;
        RECT 278.615 -260.570 279.055 -260.545 ;
        RECT 278.615 -260.850 278.660 -260.570 ;
        RECT 278.615 -260.875 279.055 -260.850 ;
        RECT 278.615 -261.275 278.655 -260.875 ;
        RECT 278.615 -261.300 279.055 -261.275 ;
        RECT 278.615 -261.580 278.660 -261.300 ;
        RECT 278.615 -261.605 279.055 -261.580 ;
        RECT 278.615 -262.005 278.655 -261.605 ;
        RECT 279.785 -262.005 1833.870 -260.145 ;
        RECT 278.615 -262.225 1833.870 -262.005 ;
        RECT 278.615 -262.625 278.655 -262.225 ;
        RECT 278.615 -262.650 279.055 -262.625 ;
        RECT 278.615 -262.930 278.660 -262.650 ;
        RECT 278.615 -262.955 279.055 -262.930 ;
        RECT 278.615 -263.355 278.655 -262.955 ;
        RECT 278.615 -263.380 279.055 -263.355 ;
        RECT 278.615 -263.660 278.660 -263.380 ;
        RECT 278.615 -263.685 279.055 -263.660 ;
        RECT 278.615 -264.085 278.655 -263.685 ;
        RECT 279.785 -264.085 1833.870 -262.225 ;
        RECT 278.615 -284.145 1833.870 -264.085 ;
        RECT 278.615 -284.545 278.655 -284.145 ;
        RECT 278.615 -284.570 279.055 -284.545 ;
        RECT 278.615 -284.850 278.660 -284.570 ;
        RECT 278.615 -284.875 279.055 -284.850 ;
        RECT 278.615 -285.275 278.655 -284.875 ;
        RECT 278.615 -285.300 279.055 -285.275 ;
        RECT 278.615 -285.580 278.660 -285.300 ;
        RECT 278.615 -285.605 279.055 -285.580 ;
        RECT 278.615 -286.005 278.655 -285.605 ;
        RECT 279.785 -286.005 1833.870 -284.145 ;
        RECT 278.615 -286.225 1833.870 -286.005 ;
        RECT 278.615 -286.625 278.655 -286.225 ;
        RECT 278.615 -286.650 279.055 -286.625 ;
        RECT 278.615 -286.930 278.660 -286.650 ;
        RECT 278.615 -286.955 279.055 -286.930 ;
        RECT 278.615 -287.355 278.655 -286.955 ;
        RECT 278.615 -287.380 279.055 -287.355 ;
        RECT 278.615 -287.660 278.660 -287.380 ;
        RECT 278.615 -287.685 279.055 -287.660 ;
        RECT 278.615 -288.085 278.655 -287.685 ;
        RECT 279.785 -288.085 1833.870 -286.225 ;
        RECT 278.615 -308.145 1833.870 -288.085 ;
        RECT 278.615 -308.545 278.655 -308.145 ;
        RECT 278.615 -308.570 279.055 -308.545 ;
        RECT 278.615 -308.850 278.660 -308.570 ;
        RECT 278.615 -308.875 279.055 -308.850 ;
        RECT 278.615 -309.275 278.655 -308.875 ;
        RECT 278.615 -309.300 279.055 -309.275 ;
        RECT 278.615 -309.580 278.660 -309.300 ;
        RECT 278.615 -309.605 279.055 -309.580 ;
        RECT 278.615 -310.005 278.655 -309.605 ;
        RECT 279.785 -310.005 1833.870 -308.145 ;
        RECT 278.615 -310.225 1833.870 -310.005 ;
        RECT 278.615 -310.625 278.655 -310.225 ;
        RECT 278.615 -310.650 279.055 -310.625 ;
        RECT 278.615 -310.930 278.660 -310.650 ;
        RECT 278.615 -310.955 279.055 -310.930 ;
        RECT 278.615 -311.355 278.655 -310.955 ;
        RECT 278.615 -311.380 279.055 -311.355 ;
        RECT 278.615 -311.660 278.660 -311.380 ;
        RECT 278.615 -311.685 279.055 -311.660 ;
        RECT 278.615 -312.085 278.655 -311.685 ;
        RECT 279.785 -312.085 1833.870 -310.225 ;
        RECT 278.615 -332.145 1833.870 -312.085 ;
        RECT 278.615 -332.545 278.655 -332.145 ;
        RECT 278.615 -332.570 279.055 -332.545 ;
        RECT 278.615 -332.850 278.660 -332.570 ;
        RECT 278.615 -332.875 279.055 -332.850 ;
        RECT 278.615 -333.275 278.655 -332.875 ;
        RECT 278.615 -333.300 279.055 -333.275 ;
        RECT 278.615 -333.580 278.660 -333.300 ;
        RECT 278.615 -333.605 279.055 -333.580 ;
        RECT 278.615 -334.005 278.655 -333.605 ;
        RECT 279.785 -334.005 1833.870 -332.145 ;
        RECT 278.615 -334.225 1833.870 -334.005 ;
        RECT 278.615 -334.625 278.655 -334.225 ;
        RECT 278.615 -334.650 279.055 -334.625 ;
        RECT 278.615 -334.930 278.660 -334.650 ;
        RECT 278.615 -334.955 279.055 -334.930 ;
        RECT 278.615 -335.355 278.655 -334.955 ;
        RECT 278.615 -335.380 279.055 -335.355 ;
        RECT 278.615 -335.660 278.660 -335.380 ;
        RECT 278.615 -335.685 279.055 -335.660 ;
        RECT 278.615 -336.085 278.655 -335.685 ;
        RECT 279.785 -336.085 1833.870 -334.225 ;
        RECT 278.615 -356.145 1833.870 -336.085 ;
        RECT 278.615 -356.545 278.655 -356.145 ;
        RECT 278.615 -356.570 279.055 -356.545 ;
        RECT 278.615 -356.850 278.660 -356.570 ;
        RECT 278.615 -356.875 279.055 -356.850 ;
        RECT 278.615 -357.275 278.655 -356.875 ;
        RECT 278.615 -357.300 279.055 -357.275 ;
        RECT 278.615 -357.580 278.660 -357.300 ;
        RECT 278.615 -357.605 279.055 -357.580 ;
        RECT 278.615 -358.005 278.655 -357.605 ;
        RECT 279.785 -358.005 1833.870 -356.145 ;
        RECT 278.615 -358.225 1833.870 -358.005 ;
        RECT 278.615 -358.625 278.655 -358.225 ;
        RECT 278.615 -358.650 279.055 -358.625 ;
        RECT 278.615 -358.930 278.660 -358.650 ;
        RECT 278.615 -358.955 279.055 -358.930 ;
        RECT 278.615 -359.355 278.655 -358.955 ;
        RECT 278.615 -359.380 279.055 -359.355 ;
        RECT 278.615 -359.660 278.660 -359.380 ;
        RECT 278.615 -359.685 279.055 -359.660 ;
        RECT 278.615 -360.085 278.655 -359.685 ;
        RECT 279.785 -360.085 1833.870 -358.225 ;
        RECT 278.615 -380.145 1833.870 -360.085 ;
        RECT 278.615 -380.545 278.655 -380.145 ;
        RECT 278.615 -380.570 279.055 -380.545 ;
        RECT 278.615 -380.850 278.660 -380.570 ;
        RECT 278.615 -380.875 279.055 -380.850 ;
        RECT 278.615 -381.275 278.655 -380.875 ;
        RECT 278.615 -381.300 279.055 -381.275 ;
        RECT 278.615 -381.580 278.660 -381.300 ;
        RECT 278.615 -381.605 279.055 -381.580 ;
        RECT 278.615 -382.005 278.655 -381.605 ;
        RECT 279.785 -382.005 1833.870 -380.145 ;
        RECT 278.615 -382.225 1833.870 -382.005 ;
        RECT 278.615 -382.625 278.655 -382.225 ;
        RECT 278.615 -382.650 279.055 -382.625 ;
        RECT 278.615 -382.930 278.660 -382.650 ;
        RECT 278.615 -382.955 279.055 -382.930 ;
        RECT 278.615 -383.355 278.655 -382.955 ;
        RECT 278.615 -383.380 279.055 -383.355 ;
        RECT 278.615 -383.660 278.660 -383.380 ;
        RECT 278.615 -383.685 279.055 -383.660 ;
        RECT 278.615 -384.085 278.655 -383.685 ;
        RECT 279.785 -384.085 1833.870 -382.225 ;
        RECT 278.615 -404.145 1833.870 -384.085 ;
        RECT 278.615 -404.545 278.655 -404.145 ;
        RECT 278.615 -404.570 279.055 -404.545 ;
        RECT 278.615 -404.850 278.660 -404.570 ;
        RECT 278.615 -404.875 279.055 -404.850 ;
        RECT 278.615 -405.275 278.655 -404.875 ;
        RECT 278.615 -405.300 279.055 -405.275 ;
        RECT 278.615 -405.580 278.660 -405.300 ;
        RECT 278.615 -405.605 279.055 -405.580 ;
        RECT 278.615 -406.005 278.655 -405.605 ;
        RECT 279.785 -406.005 1833.870 -404.145 ;
        RECT 278.615 -406.225 1833.870 -406.005 ;
        RECT 278.615 -406.625 278.655 -406.225 ;
        RECT 278.615 -406.650 279.055 -406.625 ;
        RECT 278.615 -406.930 278.660 -406.650 ;
        RECT 278.615 -406.955 279.055 -406.930 ;
        RECT 278.615 -407.355 278.655 -406.955 ;
        RECT 278.615 -407.380 279.055 -407.355 ;
        RECT 278.615 -407.660 278.660 -407.380 ;
        RECT 278.615 -407.685 279.055 -407.660 ;
        RECT 278.615 -408.085 278.655 -407.685 ;
        RECT 279.785 -408.085 1833.870 -406.225 ;
        RECT 278.615 -428.145 1833.870 -408.085 ;
        RECT 278.615 -428.545 278.655 -428.145 ;
        RECT 278.615 -428.570 279.055 -428.545 ;
        RECT 278.615 -428.850 278.660 -428.570 ;
        RECT 278.615 -428.875 279.055 -428.850 ;
        RECT 278.615 -429.275 278.655 -428.875 ;
        RECT 278.615 -429.300 279.055 -429.275 ;
        RECT 278.615 -429.580 278.660 -429.300 ;
        RECT 278.615 -429.605 279.055 -429.580 ;
        RECT 278.615 -430.005 278.655 -429.605 ;
        RECT 279.785 -430.005 1833.870 -428.145 ;
        RECT 278.615 -430.225 1833.870 -430.005 ;
        RECT 278.615 -430.625 278.655 -430.225 ;
        RECT 278.615 -430.650 279.055 -430.625 ;
        RECT 278.615 -430.930 278.660 -430.650 ;
        RECT 278.615 -430.955 279.055 -430.930 ;
        RECT 278.615 -431.355 278.655 -430.955 ;
        RECT 278.615 -431.380 279.055 -431.355 ;
        RECT 278.615 -431.660 278.660 -431.380 ;
        RECT 278.615 -431.685 279.055 -431.660 ;
        RECT 278.615 -432.085 278.655 -431.685 ;
        RECT 279.785 -432.085 1833.870 -430.225 ;
        RECT 278.615 -452.145 1833.870 -432.085 ;
        RECT 278.615 -452.545 278.655 -452.145 ;
        RECT 278.615 -452.570 279.055 -452.545 ;
        RECT 278.615 -452.850 278.660 -452.570 ;
        RECT 278.615 -452.875 279.055 -452.850 ;
        RECT 278.615 -453.275 278.655 -452.875 ;
        RECT 278.615 -453.300 279.055 -453.275 ;
        RECT 278.615 -453.580 278.660 -453.300 ;
        RECT 278.615 -453.605 279.055 -453.580 ;
        RECT 278.615 -454.005 278.655 -453.605 ;
        RECT 279.785 -454.005 1833.870 -452.145 ;
        RECT 278.615 -454.225 1833.870 -454.005 ;
        RECT 278.615 -454.625 278.655 -454.225 ;
        RECT 278.615 -454.650 279.055 -454.625 ;
        RECT 278.615 -454.930 278.660 -454.650 ;
        RECT 278.615 -454.955 279.055 -454.930 ;
        RECT 278.615 -455.355 278.655 -454.955 ;
        RECT 278.615 -455.380 279.055 -455.355 ;
        RECT 278.615 -455.660 278.660 -455.380 ;
        RECT 278.615 -455.685 279.055 -455.660 ;
        RECT 278.615 -456.085 278.655 -455.685 ;
        RECT 279.785 -456.085 1833.870 -454.225 ;
        RECT 278.615 -476.145 1833.870 -456.085 ;
        RECT 278.615 -476.545 278.655 -476.145 ;
        RECT 278.615 -476.570 279.055 -476.545 ;
        RECT 278.615 -476.850 278.660 -476.570 ;
        RECT 278.615 -476.875 279.055 -476.850 ;
        RECT 278.615 -477.275 278.655 -476.875 ;
        RECT 278.615 -477.300 279.055 -477.275 ;
        RECT 278.615 -477.580 278.660 -477.300 ;
        RECT 278.615 -477.605 279.055 -477.580 ;
        RECT 278.615 -478.005 278.655 -477.605 ;
        RECT 279.785 -478.005 1833.870 -476.145 ;
        RECT 278.615 -478.225 1833.870 -478.005 ;
        RECT 278.615 -478.625 278.655 -478.225 ;
        RECT 278.615 -478.650 279.055 -478.625 ;
        RECT 278.615 -478.930 278.660 -478.650 ;
        RECT 278.615 -478.955 279.055 -478.930 ;
        RECT 278.615 -479.355 278.655 -478.955 ;
        RECT 278.615 -479.380 279.055 -479.355 ;
        RECT 278.615 -479.660 278.660 -479.380 ;
        RECT 278.615 -479.685 279.055 -479.660 ;
        RECT 278.615 -480.085 278.655 -479.685 ;
        RECT 279.785 -480.085 1833.870 -478.225 ;
        RECT 278.615 -500.145 1833.870 -480.085 ;
        RECT 278.615 -500.545 278.655 -500.145 ;
        RECT 278.615 -500.570 279.055 -500.545 ;
        RECT 278.615 -500.850 278.660 -500.570 ;
        RECT 278.615 -500.875 279.055 -500.850 ;
        RECT 278.615 -501.275 278.655 -500.875 ;
        RECT 278.615 -501.300 279.055 -501.275 ;
        RECT 278.615 -501.580 278.660 -501.300 ;
        RECT 278.615 -501.605 279.055 -501.580 ;
        RECT 278.615 -502.005 278.655 -501.605 ;
        RECT 279.785 -502.005 1833.870 -500.145 ;
        RECT 278.615 -502.225 1833.870 -502.005 ;
        RECT 278.615 -502.625 278.655 -502.225 ;
        RECT 278.615 -502.650 279.055 -502.625 ;
        RECT 278.615 -502.930 278.660 -502.650 ;
        RECT 278.615 -502.955 279.055 -502.930 ;
        RECT 278.615 -503.355 278.655 -502.955 ;
        RECT 278.615 -503.380 279.055 -503.355 ;
        RECT 278.615 -503.660 278.660 -503.380 ;
        RECT 278.615 -503.685 279.055 -503.660 ;
        RECT 278.615 -504.085 278.655 -503.685 ;
        RECT 279.785 -504.085 1833.870 -502.225 ;
        RECT 278.615 -524.145 1833.870 -504.085 ;
        RECT 278.615 -524.545 278.655 -524.145 ;
        RECT 278.615 -524.570 279.055 -524.545 ;
        RECT 278.615 -524.850 278.660 -524.570 ;
        RECT 278.615 -524.875 279.055 -524.850 ;
        RECT 278.615 -525.275 278.655 -524.875 ;
        RECT 278.615 -525.300 279.055 -525.275 ;
        RECT 278.615 -525.580 278.660 -525.300 ;
        RECT 278.615 -525.605 279.055 -525.580 ;
        RECT 278.615 -526.005 278.655 -525.605 ;
        RECT 279.785 -526.005 1833.870 -524.145 ;
        RECT 278.615 -526.225 1833.870 -526.005 ;
        RECT 278.615 -526.625 278.655 -526.225 ;
        RECT 278.615 -526.650 279.055 -526.625 ;
        RECT 278.615 -526.930 278.660 -526.650 ;
        RECT 278.615 -526.955 279.055 -526.930 ;
        RECT 278.615 -527.355 278.655 -526.955 ;
        RECT 278.615 -527.380 279.055 -527.355 ;
        RECT 278.615 -527.660 278.660 -527.380 ;
        RECT 278.615 -527.685 279.055 -527.660 ;
        RECT 278.615 -528.085 278.655 -527.685 ;
        RECT 279.785 -528.085 1833.870 -526.225 ;
        RECT 278.615 -548.145 1833.870 -528.085 ;
        RECT 278.615 -548.545 278.655 -548.145 ;
        RECT 278.615 -548.570 279.055 -548.545 ;
        RECT 278.615 -548.850 278.660 -548.570 ;
        RECT 278.615 -548.875 279.055 -548.850 ;
        RECT 278.615 -549.275 278.655 -548.875 ;
        RECT 278.615 -549.300 279.055 -549.275 ;
        RECT 278.615 -549.580 278.660 -549.300 ;
        RECT 278.615 -549.605 279.055 -549.580 ;
        RECT 278.615 -550.005 278.655 -549.605 ;
        RECT 279.785 -550.005 1833.870 -548.145 ;
        RECT 278.615 -550.225 1833.870 -550.005 ;
        RECT 278.615 -550.625 278.655 -550.225 ;
        RECT 278.615 -550.650 279.055 -550.625 ;
        RECT 278.615 -550.930 278.660 -550.650 ;
        RECT 278.615 -550.955 279.055 -550.930 ;
        RECT 278.615 -551.355 278.655 -550.955 ;
        RECT 278.615 -551.380 279.055 -551.355 ;
        RECT 278.615 -551.660 278.660 -551.380 ;
        RECT 278.615 -551.685 279.055 -551.660 ;
        RECT 278.615 -552.085 278.655 -551.685 ;
        RECT 279.785 -552.085 1833.870 -550.225 ;
        RECT 278.615 -572.145 1833.870 -552.085 ;
        RECT 278.615 -572.545 278.655 -572.145 ;
        RECT 278.615 -572.570 279.055 -572.545 ;
        RECT 278.615 -572.850 278.660 -572.570 ;
        RECT 278.615 -572.875 279.055 -572.850 ;
        RECT 278.615 -573.275 278.655 -572.875 ;
        RECT 278.615 -573.300 279.055 -573.275 ;
        RECT 278.615 -573.580 278.660 -573.300 ;
        RECT 278.615 -573.605 279.055 -573.580 ;
        RECT 278.615 -574.005 278.655 -573.605 ;
        RECT 279.785 -574.005 1833.870 -572.145 ;
        RECT 278.615 -574.225 1833.870 -574.005 ;
        RECT 278.615 -574.625 278.655 -574.225 ;
        RECT 278.615 -574.650 279.055 -574.625 ;
        RECT 278.615 -574.930 278.660 -574.650 ;
        RECT 278.615 -574.955 279.055 -574.930 ;
        RECT 278.615 -575.355 278.655 -574.955 ;
        RECT 278.615 -575.380 279.055 -575.355 ;
        RECT 278.615 -575.660 278.660 -575.380 ;
        RECT 278.615 -575.685 279.055 -575.660 ;
        RECT 278.615 -576.085 278.655 -575.685 ;
        RECT 279.785 -576.085 1833.870 -574.225 ;
        RECT 278.615 -596.145 1833.870 -576.085 ;
        RECT 278.615 -596.545 278.655 -596.145 ;
        RECT 278.615 -596.570 279.055 -596.545 ;
        RECT 278.615 -596.850 278.660 -596.570 ;
        RECT 278.615 -596.875 279.055 -596.850 ;
        RECT 278.615 -597.275 278.655 -596.875 ;
        RECT 278.615 -597.300 279.055 -597.275 ;
        RECT 278.615 -597.580 278.660 -597.300 ;
        RECT 278.615 -597.605 279.055 -597.580 ;
        RECT 278.615 -598.005 278.655 -597.605 ;
        RECT 279.785 -598.005 1833.870 -596.145 ;
        RECT 278.615 -598.225 1833.870 -598.005 ;
        RECT 278.615 -598.625 278.655 -598.225 ;
        RECT 278.615 -598.650 279.055 -598.625 ;
        RECT 278.615 -598.930 278.660 -598.650 ;
        RECT 278.615 -598.955 279.055 -598.930 ;
        RECT 278.615 -599.355 278.655 -598.955 ;
        RECT 278.615 -599.380 279.055 -599.355 ;
        RECT 278.615 -599.660 278.660 -599.380 ;
        RECT 278.615 -599.685 279.055 -599.660 ;
        RECT 278.615 -600.085 278.655 -599.685 ;
        RECT 279.785 -600.085 1833.870 -598.225 ;
        RECT 278.615 -620.145 1833.870 -600.085 ;
        RECT 278.615 -620.545 278.655 -620.145 ;
        RECT 278.615 -620.570 279.055 -620.545 ;
        RECT 278.615 -620.850 278.660 -620.570 ;
        RECT 278.615 -620.875 279.055 -620.850 ;
        RECT 278.615 -621.275 278.655 -620.875 ;
        RECT 278.615 -621.300 279.055 -621.275 ;
        RECT 278.615 -621.580 278.660 -621.300 ;
        RECT 278.615 -621.605 279.055 -621.580 ;
        RECT 278.615 -622.005 278.655 -621.605 ;
        RECT 279.785 -622.005 1833.870 -620.145 ;
        RECT 278.615 -622.225 1833.870 -622.005 ;
        RECT 278.615 -622.625 278.655 -622.225 ;
        RECT 278.615 -622.650 279.055 -622.625 ;
        RECT 278.615 -622.930 278.660 -622.650 ;
        RECT 278.615 -622.955 279.055 -622.930 ;
        RECT 278.615 -623.355 278.655 -622.955 ;
        RECT 278.615 -623.380 279.055 -623.355 ;
        RECT 278.615 -623.660 278.660 -623.380 ;
        RECT 278.615 -623.685 279.055 -623.660 ;
        RECT 278.615 -624.085 278.655 -623.685 ;
        RECT 279.785 -624.085 1833.870 -622.225 ;
        RECT 278.615 -644.145 1833.870 -624.085 ;
        RECT 278.615 -644.545 278.655 -644.145 ;
        RECT 278.615 -644.570 279.055 -644.545 ;
        RECT 278.615 -644.850 278.660 -644.570 ;
        RECT 278.615 -644.875 279.055 -644.850 ;
        RECT 278.615 -645.275 278.655 -644.875 ;
        RECT 278.615 -645.300 279.055 -645.275 ;
        RECT 278.615 -645.580 278.660 -645.300 ;
        RECT 278.615 -645.605 279.055 -645.580 ;
        RECT 278.615 -646.005 278.655 -645.605 ;
        RECT 279.785 -646.005 1833.870 -644.145 ;
        RECT 278.615 -646.225 1833.870 -646.005 ;
        RECT 278.615 -646.625 278.655 -646.225 ;
        RECT 278.615 -646.650 279.055 -646.625 ;
        RECT 278.615 -646.930 278.660 -646.650 ;
        RECT 278.615 -646.955 279.055 -646.930 ;
        RECT 278.615 -647.355 278.655 -646.955 ;
        RECT 278.615 -647.380 279.055 -647.355 ;
        RECT 278.615 -647.660 278.660 -647.380 ;
        RECT 278.615 -647.685 279.055 -647.660 ;
        RECT 278.615 -648.085 278.655 -647.685 ;
        RECT 279.785 -648.085 1833.870 -646.225 ;
        RECT 278.615 -707.055 1833.870 -648.085 ;
        RECT 278.615 -707.140 303.045 -707.055 ;
        RECT 278.615 -707.960 280.950 -707.140 ;
        RECT 282.050 -707.175 303.045 -707.140 ;
        RECT 282.050 -707.960 283.695 -707.175 ;
        RECT 285.265 -707.960 299.815 -707.175 ;
        RECT 301.385 -707.960 303.045 -707.175 ;
        RECT 304.145 -707.960 304.950 -707.055 ;
        RECT 306.050 -707.175 327.045 -707.055 ;
        RECT 306.050 -707.960 307.695 -707.175 ;
        RECT 309.265 -707.960 323.815 -707.175 ;
        RECT 325.385 -707.960 327.045 -707.175 ;
        RECT 328.145 -707.960 328.950 -707.055 ;
        RECT 330.050 -707.175 351.045 -707.055 ;
        RECT 330.050 -707.960 331.695 -707.175 ;
        RECT 333.265 -707.960 347.815 -707.175 ;
        RECT 349.385 -707.960 351.045 -707.175 ;
        RECT 352.145 -707.960 352.950 -707.055 ;
        RECT 354.050 -707.175 375.045 -707.055 ;
        RECT 354.050 -707.960 355.695 -707.175 ;
        RECT 357.265 -707.960 371.815 -707.175 ;
        RECT 373.385 -707.960 375.045 -707.175 ;
        RECT 376.145 -707.960 376.950 -707.055 ;
        RECT 378.050 -707.175 399.045 -707.055 ;
        RECT 378.050 -707.960 379.695 -707.175 ;
        RECT 381.265 -707.960 395.815 -707.175 ;
        RECT 397.385 -707.960 399.045 -707.175 ;
        RECT 400.145 -707.960 400.950 -707.055 ;
        RECT 402.050 -707.175 423.045 -707.055 ;
        RECT 402.050 -707.960 403.695 -707.175 ;
        RECT 405.265 -707.960 419.815 -707.175 ;
        RECT 421.385 -707.960 423.045 -707.175 ;
        RECT 424.145 -707.960 424.950 -707.055 ;
        RECT 426.050 -707.175 447.045 -707.055 ;
        RECT 426.050 -707.960 427.695 -707.175 ;
        RECT 429.265 -707.960 443.815 -707.175 ;
        RECT 445.385 -707.960 447.045 -707.175 ;
        RECT 448.145 -707.960 448.950 -707.055 ;
        RECT 450.050 -707.175 471.045 -707.055 ;
        RECT 450.050 -707.960 451.695 -707.175 ;
        RECT 453.265 -707.960 467.815 -707.175 ;
        RECT 469.385 -707.960 471.045 -707.175 ;
        RECT 472.145 -707.960 472.950 -707.055 ;
        RECT 474.050 -707.175 495.045 -707.055 ;
        RECT 474.050 -707.960 475.695 -707.175 ;
        RECT 477.265 -707.960 491.815 -707.175 ;
        RECT 493.385 -707.960 495.045 -707.175 ;
        RECT 496.145 -707.960 496.950 -707.055 ;
        RECT 498.050 -707.175 519.045 -707.055 ;
        RECT 498.050 -707.960 499.695 -707.175 ;
        RECT 501.265 -707.960 515.815 -707.175 ;
        RECT 517.385 -707.960 519.045 -707.175 ;
        RECT 520.145 -707.960 520.950 -707.055 ;
        RECT 522.050 -707.175 543.045 -707.055 ;
        RECT 522.050 -707.960 523.695 -707.175 ;
        RECT 525.265 -707.960 539.815 -707.175 ;
        RECT 541.385 -707.960 543.045 -707.175 ;
        RECT 544.145 -707.960 544.950 -707.055 ;
        RECT 546.050 -707.175 567.045 -707.055 ;
        RECT 546.050 -707.960 547.695 -707.175 ;
        RECT 549.265 -707.960 563.815 -707.175 ;
        RECT 565.385 -707.960 567.045 -707.175 ;
        RECT 568.145 -707.960 568.950 -707.055 ;
        RECT 570.050 -707.175 591.045 -707.055 ;
        RECT 570.050 -707.960 571.695 -707.175 ;
        RECT 573.265 -707.960 587.815 -707.175 ;
        RECT 589.385 -707.960 591.045 -707.175 ;
        RECT 592.145 -707.960 592.950 -707.055 ;
        RECT 594.050 -707.175 615.045 -707.055 ;
        RECT 594.050 -707.960 595.695 -707.175 ;
        RECT 597.265 -707.960 611.815 -707.175 ;
        RECT 613.385 -707.960 615.045 -707.175 ;
        RECT 616.145 -707.960 616.950 -707.055 ;
        RECT 618.050 -707.175 639.045 -707.055 ;
        RECT 618.050 -707.960 619.695 -707.175 ;
        RECT 621.265 -707.960 635.815 -707.175 ;
        RECT 637.385 -707.960 639.045 -707.175 ;
        RECT 640.145 -707.960 640.950 -707.055 ;
        RECT 642.050 -707.175 663.045 -707.055 ;
        RECT 642.050 -707.960 643.695 -707.175 ;
        RECT 645.265 -707.960 659.815 -707.175 ;
        RECT 661.385 -707.960 663.045 -707.175 ;
        RECT 664.145 -707.960 664.950 -707.055 ;
        RECT 666.050 -707.175 687.045 -707.055 ;
        RECT 666.050 -707.960 667.695 -707.175 ;
        RECT 669.265 -707.960 683.815 -707.175 ;
        RECT 685.385 -707.960 687.045 -707.175 ;
        RECT 688.145 -707.960 688.950 -707.055 ;
        RECT 690.050 -707.175 711.045 -707.055 ;
        RECT 690.050 -707.960 691.695 -707.175 ;
        RECT 693.265 -707.960 707.815 -707.175 ;
        RECT 709.385 -707.960 711.045 -707.175 ;
        RECT 712.145 -707.960 712.950 -707.055 ;
        RECT 714.050 -707.175 735.045 -707.055 ;
        RECT 714.050 -707.960 715.695 -707.175 ;
        RECT 717.265 -707.960 731.815 -707.175 ;
        RECT 733.385 -707.960 735.045 -707.175 ;
        RECT 736.145 -707.960 736.950 -707.055 ;
        RECT 738.050 -707.175 759.045 -707.055 ;
        RECT 738.050 -707.960 739.695 -707.175 ;
        RECT 741.265 -707.960 755.815 -707.175 ;
        RECT 757.385 -707.960 759.045 -707.175 ;
        RECT 760.145 -707.960 760.950 -707.055 ;
        RECT 762.050 -707.175 783.045 -707.055 ;
        RECT 762.050 -707.960 763.695 -707.175 ;
        RECT 765.265 -707.960 779.815 -707.175 ;
        RECT 781.385 -707.960 783.045 -707.175 ;
        RECT 784.145 -707.960 784.950 -707.055 ;
        RECT 786.050 -707.175 807.045 -707.055 ;
        RECT 786.050 -707.960 787.695 -707.175 ;
        RECT 789.265 -707.960 803.815 -707.175 ;
        RECT 805.385 -707.960 807.045 -707.175 ;
        RECT 808.145 -707.960 808.950 -707.055 ;
        RECT 810.050 -707.175 831.045 -707.055 ;
        RECT 810.050 -707.960 811.695 -707.175 ;
        RECT 813.265 -707.960 827.815 -707.175 ;
        RECT 829.385 -707.960 831.045 -707.175 ;
        RECT 832.145 -707.960 832.950 -707.055 ;
        RECT 834.050 -707.175 855.045 -707.055 ;
        RECT 834.050 -707.960 835.695 -707.175 ;
        RECT 837.265 -707.960 851.815 -707.175 ;
        RECT 853.385 -707.960 855.045 -707.175 ;
        RECT 856.145 -707.960 856.950 -707.055 ;
        RECT 858.050 -707.175 879.045 -707.055 ;
        RECT 858.050 -707.960 859.695 -707.175 ;
        RECT 861.265 -707.960 875.815 -707.175 ;
        RECT 877.385 -707.960 879.045 -707.175 ;
        RECT 880.145 -707.960 880.950 -707.055 ;
        RECT 882.050 -707.175 903.045 -707.055 ;
        RECT 882.050 -707.960 883.695 -707.175 ;
        RECT 885.265 -707.960 899.815 -707.175 ;
        RECT 901.385 -707.960 903.045 -707.175 ;
        RECT 904.145 -707.960 904.950 -707.055 ;
        RECT 906.050 -707.175 927.045 -707.055 ;
        RECT 906.050 -707.960 907.695 -707.175 ;
        RECT 909.265 -707.960 923.815 -707.175 ;
        RECT 925.385 -707.960 927.045 -707.175 ;
        RECT 928.145 -707.960 928.950 -707.055 ;
        RECT 930.050 -707.175 951.045 -707.055 ;
        RECT 930.050 -707.960 931.695 -707.175 ;
        RECT 933.265 -707.960 947.815 -707.175 ;
        RECT 949.385 -707.960 951.045 -707.175 ;
        RECT 952.145 -707.960 952.950 -707.055 ;
        RECT 954.050 -707.175 975.045 -707.055 ;
        RECT 954.050 -707.960 955.695 -707.175 ;
        RECT 957.265 -707.960 971.815 -707.175 ;
        RECT 973.385 -707.960 975.045 -707.175 ;
        RECT 976.145 -707.960 976.950 -707.055 ;
        RECT 978.050 -707.175 999.045 -707.055 ;
        RECT 978.050 -707.960 979.695 -707.175 ;
        RECT 981.265 -707.960 995.815 -707.175 ;
        RECT 997.385 -707.960 999.045 -707.175 ;
        RECT 1000.145 -707.960 1000.950 -707.055 ;
        RECT 1002.050 -707.175 1023.045 -707.055 ;
        RECT 1002.050 -707.960 1003.695 -707.175 ;
        RECT 1005.265 -707.960 1019.815 -707.175 ;
        RECT 1021.385 -707.960 1023.045 -707.175 ;
        RECT 1024.145 -707.960 1024.950 -707.055 ;
        RECT 1026.050 -707.175 1047.045 -707.055 ;
        RECT 1026.050 -707.960 1027.695 -707.175 ;
        RECT 1029.265 -707.960 1043.815 -707.175 ;
        RECT 1045.385 -707.960 1047.045 -707.175 ;
        RECT 1048.145 -707.140 1071.045 -707.055 ;
        RECT 1048.145 -707.960 1048.950 -707.140 ;
        RECT 1050.050 -707.175 1071.045 -707.140 ;
        RECT 1050.050 -707.960 1051.695 -707.175 ;
        RECT 1053.265 -707.960 1067.815 -707.175 ;
        RECT 1069.385 -707.960 1071.045 -707.175 ;
        RECT 1072.145 -707.960 1072.950 -707.055 ;
        RECT 1074.050 -707.175 1095.045 -707.055 ;
        RECT 1074.050 -707.960 1075.695 -707.175 ;
        RECT 1077.265 -707.960 1091.815 -707.175 ;
        RECT 1093.385 -707.960 1095.045 -707.175 ;
        RECT 1096.145 -707.960 1096.950 -707.055 ;
        RECT 1098.050 -707.175 1119.045 -707.055 ;
        RECT 1098.050 -707.960 1099.695 -707.175 ;
        RECT 1101.265 -707.960 1115.815 -707.175 ;
        RECT 1117.385 -707.960 1119.045 -707.175 ;
        RECT 1120.145 -707.960 1120.950 -707.055 ;
        RECT 1122.050 -707.175 1143.045 -707.055 ;
        RECT 1122.050 -707.960 1123.695 -707.175 ;
        RECT 1125.265 -707.960 1139.815 -707.175 ;
        RECT 1141.385 -707.960 1143.045 -707.175 ;
        RECT 1144.145 -707.960 1144.950 -707.055 ;
        RECT 1146.050 -707.175 1167.045 -707.055 ;
        RECT 1146.050 -707.960 1147.695 -707.175 ;
        RECT 1149.265 -707.960 1163.815 -707.175 ;
        RECT 1165.385 -707.960 1167.045 -707.175 ;
        RECT 1168.145 -707.960 1168.950 -707.055 ;
        RECT 1170.050 -707.175 1191.045 -707.055 ;
        RECT 1170.050 -707.960 1171.695 -707.175 ;
        RECT 1173.265 -707.960 1187.815 -707.175 ;
        RECT 1189.385 -707.960 1191.045 -707.175 ;
        RECT 1192.145 -707.960 1192.950 -707.055 ;
        RECT 1194.050 -707.175 1215.045 -707.055 ;
        RECT 1194.050 -707.960 1195.695 -707.175 ;
        RECT 1197.265 -707.960 1211.815 -707.175 ;
        RECT 1213.385 -707.960 1215.045 -707.175 ;
        RECT 1216.145 -707.960 1216.950 -707.055 ;
        RECT 1218.050 -707.175 1239.045 -707.055 ;
        RECT 1218.050 -707.960 1219.695 -707.175 ;
        RECT 1221.265 -707.960 1235.815 -707.175 ;
        RECT 1237.385 -707.960 1239.045 -707.175 ;
        RECT 1240.145 -707.960 1240.950 -707.055 ;
        RECT 1242.050 -707.175 1263.045 -707.055 ;
        RECT 1242.050 -707.960 1243.695 -707.175 ;
        RECT 1245.265 -707.960 1259.815 -707.175 ;
        RECT 1261.385 -707.960 1263.045 -707.175 ;
        RECT 1264.145 -707.960 1264.950 -707.055 ;
        RECT 1266.050 -707.175 1287.045 -707.055 ;
        RECT 1266.050 -707.960 1267.695 -707.175 ;
        RECT 1269.265 -707.960 1283.815 -707.175 ;
        RECT 1285.385 -707.960 1287.045 -707.175 ;
        RECT 1288.145 -707.960 1288.950 -707.055 ;
        RECT 1290.050 -707.175 1311.045 -707.055 ;
        RECT 1290.050 -707.960 1291.695 -707.175 ;
        RECT 1293.265 -707.960 1307.815 -707.175 ;
        RECT 1309.385 -707.960 1311.045 -707.175 ;
        RECT 1312.145 -707.960 1312.950 -707.055 ;
        RECT 1314.050 -707.175 1335.045 -707.055 ;
        RECT 1314.050 -707.960 1315.695 -707.175 ;
        RECT 1317.265 -707.960 1331.815 -707.175 ;
        RECT 1333.385 -707.960 1335.045 -707.175 ;
        RECT 1336.145 -707.960 1336.950 -707.055 ;
        RECT 1338.050 -707.175 1359.045 -707.055 ;
        RECT 1338.050 -707.960 1339.695 -707.175 ;
        RECT 1341.265 -707.960 1355.815 -707.175 ;
        RECT 1357.385 -707.960 1359.045 -707.175 ;
        RECT 1360.145 -707.960 1360.950 -707.055 ;
        RECT 1362.050 -707.175 1383.045 -707.055 ;
        RECT 1362.050 -707.960 1363.695 -707.175 ;
        RECT 1365.265 -707.960 1379.815 -707.175 ;
        RECT 1381.385 -707.960 1383.045 -707.175 ;
        RECT 1384.145 -707.960 1384.950 -707.055 ;
        RECT 1386.050 -707.175 1407.045 -707.055 ;
        RECT 1386.050 -707.960 1387.695 -707.175 ;
        RECT 1389.265 -707.960 1403.815 -707.175 ;
        RECT 1405.385 -707.960 1407.045 -707.175 ;
        RECT 1408.145 -707.960 1408.950 -707.055 ;
        RECT 1410.050 -707.175 1431.045 -707.055 ;
        RECT 1410.050 -707.960 1411.695 -707.175 ;
        RECT 1413.265 -707.960 1427.815 -707.175 ;
        RECT 1429.385 -707.960 1431.045 -707.175 ;
        RECT 1432.145 -707.960 1432.950 -707.055 ;
        RECT 1434.050 -707.175 1455.045 -707.055 ;
        RECT 1434.050 -707.960 1435.695 -707.175 ;
        RECT 1437.265 -707.960 1451.815 -707.175 ;
        RECT 1453.385 -707.960 1455.045 -707.175 ;
        RECT 1456.145 -707.960 1456.950 -707.055 ;
        RECT 1458.050 -707.175 1479.045 -707.055 ;
        RECT 1458.050 -707.960 1459.695 -707.175 ;
        RECT 1461.265 -707.960 1475.815 -707.175 ;
        RECT 1477.385 -707.960 1479.045 -707.175 ;
        RECT 1480.145 -707.960 1480.950 -707.055 ;
        RECT 1482.050 -707.175 1503.045 -707.055 ;
        RECT 1482.050 -707.960 1483.695 -707.175 ;
        RECT 1485.265 -707.960 1499.815 -707.175 ;
        RECT 1501.385 -707.960 1503.045 -707.175 ;
        RECT 1504.145 -707.960 1504.950 -707.055 ;
        RECT 1506.050 -707.175 1527.045 -707.055 ;
        RECT 1506.050 -707.960 1507.695 -707.175 ;
        RECT 1509.265 -707.960 1523.815 -707.175 ;
        RECT 1525.385 -707.960 1527.045 -707.175 ;
        RECT 1528.145 -707.960 1528.950 -707.055 ;
        RECT 1530.050 -707.175 1551.045 -707.055 ;
        RECT 1530.050 -707.960 1531.695 -707.175 ;
        RECT 1533.265 -707.960 1547.815 -707.175 ;
        RECT 1549.385 -707.960 1551.045 -707.175 ;
        RECT 1552.145 -707.960 1552.950 -707.055 ;
        RECT 1554.050 -707.175 1575.045 -707.055 ;
        RECT 1554.050 -707.960 1555.695 -707.175 ;
        RECT 1557.265 -707.960 1571.815 -707.175 ;
        RECT 1573.385 -707.960 1575.045 -707.175 ;
        RECT 1576.145 -707.960 1576.950 -707.055 ;
        RECT 1578.050 -707.175 1599.045 -707.055 ;
        RECT 1578.050 -707.960 1579.695 -707.175 ;
        RECT 1581.265 -707.960 1595.815 -707.175 ;
        RECT 1597.385 -707.960 1599.045 -707.175 ;
        RECT 1600.145 -707.960 1600.950 -707.055 ;
        RECT 1602.050 -707.175 1623.045 -707.055 ;
        RECT 1602.050 -707.960 1603.695 -707.175 ;
        RECT 1605.265 -707.960 1619.815 -707.175 ;
        RECT 1621.385 -707.960 1623.045 -707.175 ;
        RECT 1624.145 -707.960 1624.950 -707.055 ;
        RECT 1626.050 -707.175 1647.045 -707.055 ;
        RECT 1626.050 -707.960 1627.695 -707.175 ;
        RECT 1629.265 -707.960 1643.815 -707.175 ;
        RECT 1645.385 -707.960 1647.045 -707.175 ;
        RECT 1648.145 -707.960 1648.950 -707.055 ;
        RECT 1650.050 -707.175 1671.045 -707.055 ;
        RECT 1650.050 -707.960 1651.695 -707.175 ;
        RECT 1653.265 -707.960 1667.815 -707.175 ;
        RECT 1669.385 -707.960 1671.045 -707.175 ;
        RECT 1672.145 -707.960 1672.950 -707.055 ;
        RECT 1674.050 -707.175 1695.045 -707.055 ;
        RECT 1674.050 -707.960 1675.695 -707.175 ;
        RECT 1677.265 -707.960 1691.815 -707.175 ;
        RECT 1693.385 -707.960 1695.045 -707.175 ;
        RECT 1696.145 -707.960 1696.950 -707.055 ;
        RECT 1698.050 -707.175 1719.045 -707.055 ;
        RECT 1698.050 -707.960 1699.695 -707.175 ;
        RECT 1701.265 -707.960 1715.815 -707.175 ;
        RECT 1717.385 -707.960 1719.045 -707.175 ;
        RECT 1720.145 -707.960 1720.950 -707.055 ;
        RECT 1722.050 -707.175 1743.045 -707.055 ;
        RECT 1722.050 -707.960 1723.695 -707.175 ;
        RECT 1725.265 -707.960 1739.815 -707.175 ;
        RECT 1741.385 -707.960 1743.045 -707.175 ;
        RECT 1744.145 -707.960 1744.950 -707.055 ;
        RECT 1746.050 -707.175 1767.045 -707.055 ;
        RECT 1746.050 -707.960 1747.695 -707.175 ;
        RECT 1749.265 -707.960 1763.815 -707.175 ;
        RECT 1765.385 -707.960 1767.045 -707.175 ;
        RECT 1768.145 -707.960 1768.950 -707.055 ;
        RECT 1770.050 -707.175 1791.045 -707.055 ;
        RECT 1770.050 -707.960 1771.695 -707.175 ;
        RECT 1773.265 -707.960 1787.815 -707.175 ;
        RECT 1789.385 -707.960 1791.045 -707.175 ;
        RECT 1792.145 -707.960 1792.950 -707.055 ;
        RECT 1794.050 -707.175 1815.045 -707.055 ;
        RECT 1794.050 -707.960 1795.695 -707.175 ;
        RECT 1797.265 -707.960 1811.815 -707.175 ;
        RECT 1813.385 -707.960 1815.045 -707.175 ;
        RECT 1816.145 -707.960 1833.870 -707.055 ;
      LAYER met4 ;
        RECT 279.415 -707.935 1817.665 927.705 ;
  END
END pixel_4tile
END LIBRARY

